VERSION 5.8 ;
BUSBITCHARS "[]" ;
DIVIDERCHAR "/" ;
UNITS
    DATABASE MICRONS 1000 ;
END UNITS

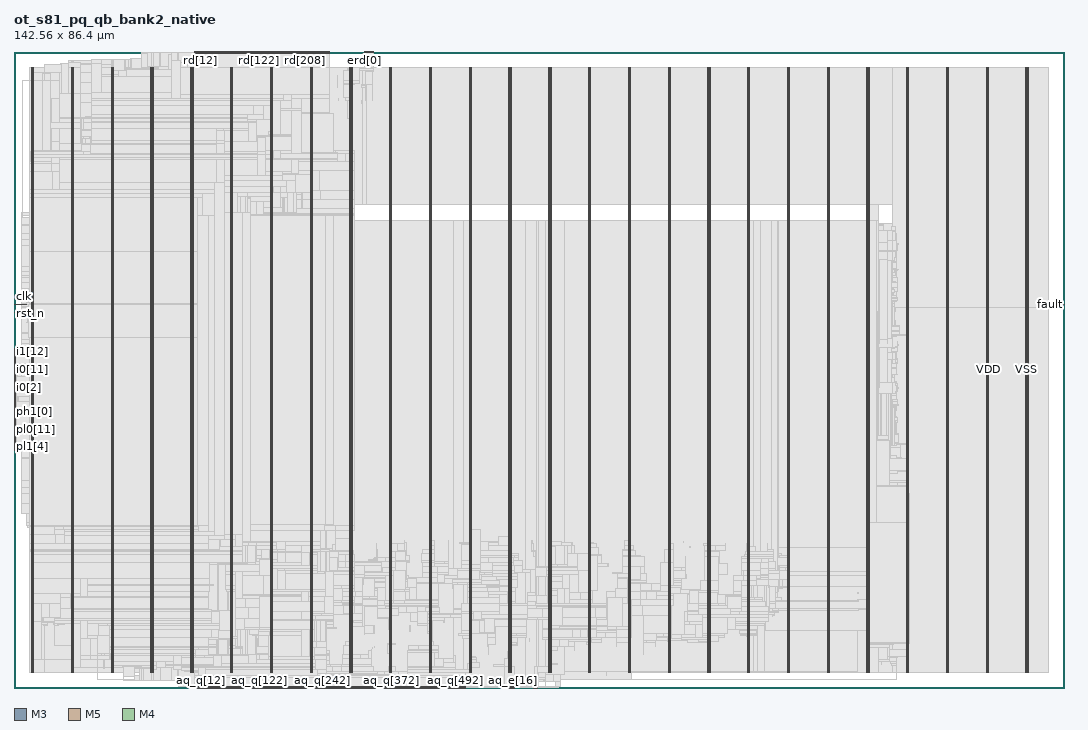
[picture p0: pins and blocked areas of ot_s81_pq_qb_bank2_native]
MACRO ot_s81_pq_qb_bank2_native
  FOREIGN ot_s81_pq_qb_bank2_native 0 0 ;
  CLASS BLOCK ;
  SIZE 142.56 BY 86.4 ;
  PIN aq_e[0]
    DIRECTION INPUT ;
    USE SIGNAL ;
    PORT
      LAYER M3 ;
        RECT  66.528 0 66.546 0.144 ;
    END
  END aq_e[0]
  PIN aq_e[10]
    DIRECTION INPUT ;
    USE SIGNAL ;
    PORT
      LAYER M3 ;
        RECT  67.248 0 67.266 0.144 ;
    END
  END aq_e[10]
  PIN aq_e[11]
    DIRECTION INPUT ;
    USE SIGNAL ;
    PORT
      LAYER M5 ;
        RECT  67.296 0 67.32 0.192 ;
    END
  END aq_e[11]
  PIN aq_e[12]
    DIRECTION INPUT ;
    USE SIGNAL ;
    PORT
      LAYER M3 ;
        RECT  67.392 0 67.41 0.144 ;
    END
  END aq_e[12]
  PIN aq_e[13]
    DIRECTION INPUT ;
    USE SIGNAL ;
    PORT
      LAYER M5 ;
        RECT  67.44 0 67.464 0.192 ;
    END
  END aq_e[13]
  PIN aq_e[14]
    DIRECTION INPUT ;
    USE SIGNAL ;
    PORT
      LAYER M3 ;
        RECT  67.536 0 67.554 0.144 ;
    END
  END aq_e[14]
  PIN aq_e[15]
    DIRECTION INPUT ;
    USE SIGNAL ;
    PORT
      LAYER M5 ;
        RECT  67.584 0 67.608 0.192 ;
    END
  END aq_e[15]
  PIN aq_e[16]
    DIRECTION INPUT ;
    USE SIGNAL ;
    PORT
      LAYER M3 ;
        RECT  67.68 0 67.698 0.144 ;
    END
  END aq_e[16]
  PIN aq_e[17]
    DIRECTION INPUT ;
    USE SIGNAL ;
    PORT
      LAYER M5 ;
        RECT  67.728 0 67.752 0.192 ;
    END
  END aq_e[17]
  PIN aq_e[18]
    DIRECTION INPUT ;
    USE SIGNAL ;
    PORT
      LAYER M3 ;
        RECT  67.824 0 67.842 0.144 ;
    END
  END aq_e[18]
  PIN aq_e[19]
    DIRECTION INPUT ;
    USE SIGNAL ;
    PORT
      LAYER M5 ;
        RECT  67.872 0 67.896 0.192 ;
    END
  END aq_e[19]
  PIN aq_e[1]
    DIRECTION INPUT ;
    USE SIGNAL ;
    PORT
      LAYER M5 ;
        RECT  66.576 0 66.6 0.192 ;
    END
  END aq_e[1]
  PIN aq_e[2]
    DIRECTION INPUT ;
    USE SIGNAL ;
    PORT
      LAYER M3 ;
        RECT  66.672 0 66.69 0.144 ;
    END
  END aq_e[2]
  PIN aq_e[3]
    DIRECTION INPUT ;
    USE SIGNAL ;
    PORT
      LAYER M5 ;
        RECT  66.72 0 66.744 0.192 ;
    END
  END aq_e[3]
  PIN aq_e[4]
    DIRECTION INPUT ;
    USE SIGNAL ;
    PORT
      LAYER M3 ;
        RECT  66.816 0 66.834 0.144 ;
    END
  END aq_e[4]
  PIN aq_e[5]
    DIRECTION INPUT ;
    USE SIGNAL ;
    PORT
      LAYER M5 ;
        RECT  66.864 0 66.888 0.192 ;
    END
  END aq_e[5]
  PIN aq_e[6]
    DIRECTION INPUT ;
    USE SIGNAL ;
    PORT
      LAYER M3 ;
        RECT  66.96 0 66.978 0.144 ;
    END
  END aq_e[6]
  PIN aq_e[7]
    DIRECTION INPUT ;
    USE SIGNAL ;
    PORT
      LAYER M5 ;
        RECT  67.008 0 67.032 0.192 ;
    END
  END aq_e[7]
  PIN aq_e[8]
    DIRECTION INPUT ;
    USE SIGNAL ;
    PORT
      LAYER M3 ;
        RECT  67.104 0 67.122 0.144 ;
    END
  END aq_e[8]
  PIN aq_e[9]
    DIRECTION INPUT ;
    USE SIGNAL ;
    PORT
      LAYER M5 ;
        RECT  67.152 0 67.176 0.192 ;
    END
  END aq_e[9]
  PIN aq_p[0]
    DIRECTION INPUT ;
    USE SIGNAL ;
    PORT
      LAYER M3 ;
        RECT  70.488 0 70.506 0.144 ;
    END
  END aq_p[0]
  PIN aq_p[1]
    DIRECTION INPUT ;
    USE SIGNAL ;
    PORT
      LAYER M5 ;
        RECT  70.512 0 70.536 0.192 ;
    END
  END aq_p[1]
  PIN aq_p[2]
    DIRECTION INPUT ;
    USE SIGNAL ;
    PORT
      LAYER M3 ;
        RECT  70.632 0 70.65 0.144 ;
    END
  END aq_p[2]
  PIN aq_p[3]
    DIRECTION INPUT ;
    USE SIGNAL ;
    PORT
      LAYER M5 ;
        RECT  70.656 0 70.68 0.192 ;
    END
  END aq_p[3]
  PIN aq_p[4]
    DIRECTION INPUT ;
    USE SIGNAL ;
    PORT
      LAYER M3 ;
        RECT  70.776 0 70.794 0.144 ;
    END
  END aq_p[4]
  PIN aq_p[5]
    DIRECTION INPUT ;
    USE SIGNAL ;
    PORT
      LAYER M5 ;
        RECT  70.8 0 70.824 0.192 ;
    END
  END aq_p[5]
  PIN aq_p[6]
    DIRECTION INPUT ;
    USE SIGNAL ;
    PORT
      LAYER M3 ;
        RECT  70.92 0 70.938 0.144 ;
    END
  END aq_p[6]
  PIN aq_p[7]
    DIRECTION INPUT ;
    USE SIGNAL ;
    PORT
      LAYER M5 ;
        RECT  70.944 0 70.968 0.192 ;
    END
  END aq_p[7]
  PIN aq_p[8]
    DIRECTION INPUT ;
    USE SIGNAL ;
    PORT
      LAYER M3 ;
        RECT  71.064 0 71.082 0.144 ;
    END
  END aq_p[8]
  PIN aq_p[9]
    DIRECTION INPUT ;
    USE SIGNAL ;
    PORT
      LAYER M5 ;
        RECT  71.088 0 71.112 0.192 ;
    END
  END aq_p[9]
  PIN aq_q[0]
    DIRECTION INPUT ;
    USE SIGNAL ;
    PORT
      LAYER M3 ;
        RECT  24.48 0 24.498 0.144 ;
    END
  END aq_q[0]
  PIN aq_q[100]
    DIRECTION INPUT ;
    USE SIGNAL ;
    PORT
      LAYER M3 ;
        RECT  31.68 0 31.698 0.144 ;
    END
  END aq_q[100]
  PIN aq_q[101]
    DIRECTION INPUT ;
    USE SIGNAL ;
    PORT
      LAYER M5 ;
        RECT  31.728 0 31.752 0.192 ;
    END
  END aq_q[101]
  PIN aq_q[102]
    DIRECTION INPUT ;
    USE SIGNAL ;
    PORT
      LAYER M3 ;
        RECT  31.824 0 31.842 0.144 ;
    END
  END aq_q[102]
  PIN aq_q[103]
    DIRECTION INPUT ;
    USE SIGNAL ;
    PORT
      LAYER M5 ;
        RECT  31.872 0 31.896 0.192 ;
    END
  END aq_q[103]
  PIN aq_q[104]
    DIRECTION INPUT ;
    USE SIGNAL ;
    PORT
      LAYER M3 ;
        RECT  31.968 0 31.986 0.144 ;
    END
  END aq_q[104]
  PIN aq_q[105]
    DIRECTION INPUT ;
    USE SIGNAL ;
    PORT
      LAYER M5 ;
        RECT  32.016 0 32.04 0.192 ;
    END
  END aq_q[105]
  PIN aq_q[106]
    DIRECTION INPUT ;
    USE SIGNAL ;
    PORT
      LAYER M3 ;
        RECT  32.112 0 32.13 0.144 ;
    END
  END aq_q[106]
  PIN aq_q[107]
    DIRECTION INPUT ;
    USE SIGNAL ;
    PORT
      LAYER M5 ;
        RECT  32.16 0 32.184 0.192 ;
    END
  END aq_q[107]
  PIN aq_q[108]
    DIRECTION INPUT ;
    USE SIGNAL ;
    PORT
      LAYER M3 ;
        RECT  32.256 0 32.274 0.144 ;
    END
  END aq_q[108]
  PIN aq_q[109]
    DIRECTION INPUT ;
    USE SIGNAL ;
    PORT
      LAYER M5 ;
        RECT  32.304 0 32.328 0.192 ;
    END
  END aq_q[109]
  PIN aq_q[10]
    DIRECTION INPUT ;
    USE SIGNAL ;
    PORT
      LAYER M3 ;
        RECT  25.2 0 25.218 0.144 ;
    END
  END aq_q[10]
  PIN aq_q[110]
    DIRECTION INPUT ;
    USE SIGNAL ;
    PORT
      LAYER M3 ;
        RECT  32.4 0 32.418 0.144 ;
    END
  END aq_q[110]
  PIN aq_q[111]
    DIRECTION INPUT ;
    USE SIGNAL ;
    PORT
      LAYER M5 ;
        RECT  32.448 0 32.472 0.192 ;
    END
  END aq_q[111]
  PIN aq_q[112]
    DIRECTION INPUT ;
    USE SIGNAL ;
    PORT
      LAYER M3 ;
        RECT  32.544 0 32.562 0.144 ;
    END
  END aq_q[112]
  PIN aq_q[113]
    DIRECTION INPUT ;
    USE SIGNAL ;
    PORT
      LAYER M5 ;
        RECT  32.592 0 32.616 0.192 ;
    END
  END aq_q[113]
  PIN aq_q[114]
    DIRECTION INPUT ;
    USE SIGNAL ;
    PORT
      LAYER M3 ;
        RECT  32.688 0 32.706 0.144 ;
    END
  END aq_q[114]
  PIN aq_q[115]
    DIRECTION INPUT ;
    USE SIGNAL ;
    PORT
      LAYER M5 ;
        RECT  32.736 0 32.76 0.192 ;
    END
  END aq_q[115]
  PIN aq_q[116]
    DIRECTION INPUT ;
    USE SIGNAL ;
    PORT
      LAYER M3 ;
        RECT  32.832 0 32.85 0.144 ;
    END
  END aq_q[116]
  PIN aq_q[117]
    DIRECTION INPUT ;
    USE SIGNAL ;
    PORT
      LAYER M5 ;
        RECT  32.88 0 32.904 0.192 ;
    END
  END aq_q[117]
  PIN aq_q[118]
    DIRECTION INPUT ;
    USE SIGNAL ;
    PORT
      LAYER M3 ;
        RECT  32.976 0 32.994 0.144 ;
    END
  END aq_q[118]
  PIN aq_q[119]
    DIRECTION INPUT ;
    USE SIGNAL ;
    PORT
      LAYER M5 ;
        RECT  33.024 0 33.048 0.192 ;
    END
  END aq_q[119]
  PIN aq_q[11]
    DIRECTION INPUT ;
    USE SIGNAL ;
    PORT
      LAYER M5 ;
        RECT  25.248 0 25.272 0.192 ;
    END
  END aq_q[11]
  PIN aq_q[120]
    DIRECTION INPUT ;
    USE SIGNAL ;
    PORT
      LAYER M3 ;
        RECT  33.12 0 33.138 0.144 ;
    END
  END aq_q[120]
  PIN aq_q[121]
    DIRECTION INPUT ;
    USE SIGNAL ;
    PORT
      LAYER M5 ;
        RECT  33.168 0 33.192 0.192 ;
    END
  END aq_q[121]
  PIN aq_q[122]
    DIRECTION INPUT ;
    USE SIGNAL ;
    PORT
      LAYER M3 ;
        RECT  33.264 0 33.282 0.144 ;
    END
  END aq_q[122]
  PIN aq_q[123]
    DIRECTION INPUT ;
    USE SIGNAL ;
    PORT
      LAYER M5 ;
        RECT  33.312 0 33.336 0.192 ;
    END
  END aq_q[123]
  PIN aq_q[124]
    DIRECTION INPUT ;
    USE SIGNAL ;
    PORT
      LAYER M3 ;
        RECT  33.408 0 33.426 0.144 ;
    END
  END aq_q[124]
  PIN aq_q[125]
    DIRECTION INPUT ;
    USE SIGNAL ;
    PORT
      LAYER M5 ;
        RECT  33.456 0 33.48 0.192 ;
    END
  END aq_q[125]
  PIN aq_q[126]
    DIRECTION INPUT ;
    USE SIGNAL ;
    PORT
      LAYER M3 ;
        RECT  33.552 0 33.57 0.144 ;
    END
  END aq_q[126]
  PIN aq_q[127]
    DIRECTION INPUT ;
    USE SIGNAL ;
    PORT
      LAYER M5 ;
        RECT  33.6 0 33.624 0.192 ;
    END
  END aq_q[127]
  PIN aq_q[128]
    DIRECTION INPUT ;
    USE SIGNAL ;
    PORT
      LAYER M3 ;
        RECT  33.696 0 33.714 0.144 ;
    END
  END aq_q[128]
  PIN aq_q[129]
    DIRECTION INPUT ;
    USE SIGNAL ;
    PORT
      LAYER M5 ;
        RECT  33.744 0 33.768 0.192 ;
    END
  END aq_q[129]
  PIN aq_q[12]
    DIRECTION INPUT ;
    USE SIGNAL ;
    PORT
      LAYER M3 ;
        RECT  25.344 0 25.362 0.144 ;
    END
  END aq_q[12]
  PIN aq_q[130]
    DIRECTION INPUT ;
    USE SIGNAL ;
    PORT
      LAYER M3 ;
        RECT  33.84 0 33.858 0.144 ;
    END
  END aq_q[130]
  PIN aq_q[131]
    DIRECTION INPUT ;
    USE SIGNAL ;
    PORT
      LAYER M5 ;
        RECT  33.888 0 33.912 0.192 ;
    END
  END aq_q[131]
  PIN aq_q[132]
    DIRECTION INPUT ;
    USE SIGNAL ;
    PORT
      LAYER M3 ;
        RECT  33.984 0 34.002 0.144 ;
    END
  END aq_q[132]
  PIN aq_q[133]
    DIRECTION INPUT ;
    USE SIGNAL ;
    PORT
      LAYER M5 ;
        RECT  34.032 0 34.056 0.192 ;
    END
  END aq_q[133]
  PIN aq_q[134]
    DIRECTION INPUT ;
    USE SIGNAL ;
    PORT
      LAYER M3 ;
        RECT  34.128 0 34.146 0.144 ;
    END
  END aq_q[134]
  PIN aq_q[135]
    DIRECTION INPUT ;
    USE SIGNAL ;
    PORT
      LAYER M5 ;
        RECT  34.176 0 34.2 0.192 ;
    END
  END aq_q[135]
  PIN aq_q[136]
    DIRECTION INPUT ;
    USE SIGNAL ;
    PORT
      LAYER M3 ;
        RECT  34.272 0 34.29 0.144 ;
    END
  END aq_q[136]
  PIN aq_q[137]
    DIRECTION INPUT ;
    USE SIGNAL ;
    PORT
      LAYER M5 ;
        RECT  34.32 0 34.344 0.192 ;
    END
  END aq_q[137]
  PIN aq_q[138]
    DIRECTION INPUT ;
    USE SIGNAL ;
    PORT
      LAYER M3 ;
        RECT  34.416 0 34.434 0.144 ;
    END
  END aq_q[138]
  PIN aq_q[139]
    DIRECTION INPUT ;
    USE SIGNAL ;
    PORT
      LAYER M5 ;
        RECT  34.464 0 34.488 0.192 ;
    END
  END aq_q[139]
  PIN aq_q[13]
    DIRECTION INPUT ;
    USE SIGNAL ;
    PORT
      LAYER M5 ;
        RECT  25.392 0 25.416 0.192 ;
    END
  END aq_q[13]
  PIN aq_q[140]
    DIRECTION INPUT ;
    USE SIGNAL ;
    PORT
      LAYER M3 ;
        RECT  34.56 0 34.578 0.144 ;
    END
  END aq_q[140]
  PIN aq_q[141]
    DIRECTION INPUT ;
    USE SIGNAL ;
    PORT
      LAYER M5 ;
        RECT  34.608 0 34.632 0.192 ;
    END
  END aq_q[141]
  PIN aq_q[142]
    DIRECTION INPUT ;
    USE SIGNAL ;
    PORT
      LAYER M3 ;
        RECT  34.704 0 34.722 0.144 ;
    END
  END aq_q[142]
  PIN aq_q[143]
    DIRECTION INPUT ;
    USE SIGNAL ;
    PORT
      LAYER M5 ;
        RECT  34.752 0 34.776 0.192 ;
    END
  END aq_q[143]
  PIN aq_q[144]
    DIRECTION INPUT ;
    USE SIGNAL ;
    PORT
      LAYER M3 ;
        RECT  34.848 0 34.866 0.144 ;
    END
  END aq_q[144]
  PIN aq_q[145]
    DIRECTION INPUT ;
    USE SIGNAL ;
    PORT
      LAYER M5 ;
        RECT  34.896 0 34.92 0.192 ;
    END
  END aq_q[145]
  PIN aq_q[146]
    DIRECTION INPUT ;
    USE SIGNAL ;
    PORT
      LAYER M3 ;
        RECT  34.992 0 35.01 0.144 ;
    END
  END aq_q[146]
  PIN aq_q[147]
    DIRECTION INPUT ;
    USE SIGNAL ;
    PORT
      LAYER M5 ;
        RECT  35.04 0 35.064 0.192 ;
    END
  END aq_q[147]
  PIN aq_q[148]
    DIRECTION INPUT ;
    USE SIGNAL ;
    PORT
      LAYER M3 ;
        RECT  35.136 0 35.154 0.144 ;
    END
  END aq_q[148]
  PIN aq_q[149]
    DIRECTION INPUT ;
    USE SIGNAL ;
    PORT
      LAYER M5 ;
        RECT  35.184 0 35.208 0.192 ;
    END
  END aq_q[149]
  PIN aq_q[14]
    DIRECTION INPUT ;
    USE SIGNAL ;
    PORT
      LAYER M3 ;
        RECT  25.488 0 25.506 0.144 ;
    END
  END aq_q[14]
  PIN aq_q[150]
    DIRECTION INPUT ;
    USE SIGNAL ;
    PORT
      LAYER M3 ;
        RECT  35.28 0 35.298 0.144 ;
    END
  END aq_q[150]
  PIN aq_q[151]
    DIRECTION INPUT ;
    USE SIGNAL ;
    PORT
      LAYER M5 ;
        RECT  35.328 0 35.352 0.192 ;
    END
  END aq_q[151]
  PIN aq_q[152]
    DIRECTION INPUT ;
    USE SIGNAL ;
    PORT
      LAYER M3 ;
        RECT  35.424 0 35.442 0.144 ;
    END
  END aq_q[152]
  PIN aq_q[153]
    DIRECTION INPUT ;
    USE SIGNAL ;
    PORT
      LAYER M5 ;
        RECT  35.472 0 35.496 0.192 ;
    END
  END aq_q[153]
  PIN aq_q[154]
    DIRECTION INPUT ;
    USE SIGNAL ;
    PORT
      LAYER M3 ;
        RECT  35.568 0 35.586 0.144 ;
    END
  END aq_q[154]
  PIN aq_q[155]
    DIRECTION INPUT ;
    USE SIGNAL ;
    PORT
      LAYER M5 ;
        RECT  35.616 0 35.64 0.192 ;
    END
  END aq_q[155]
  PIN aq_q[156]
    DIRECTION INPUT ;
    USE SIGNAL ;
    PORT
      LAYER M3 ;
        RECT  35.712 0 35.73 0.144 ;
    END
  END aq_q[156]
  PIN aq_q[157]
    DIRECTION INPUT ;
    USE SIGNAL ;
    PORT
      LAYER M5 ;
        RECT  35.76 0 35.784 0.192 ;
    END
  END aq_q[157]
  PIN aq_q[158]
    DIRECTION INPUT ;
    USE SIGNAL ;
    PORT
      LAYER M3 ;
        RECT  35.856 0 35.874 0.144 ;
    END
  END aq_q[158]
  PIN aq_q[159]
    DIRECTION INPUT ;
    USE SIGNAL ;
    PORT
      LAYER M5 ;
        RECT  35.904 0 35.928 0.192 ;
    END
  END aq_q[159]
  PIN aq_q[15]
    DIRECTION INPUT ;
    USE SIGNAL ;
    PORT
      LAYER M5 ;
        RECT  25.536 0 25.56 0.192 ;
    END
  END aq_q[15]
  PIN aq_q[160]
    DIRECTION INPUT ;
    USE SIGNAL ;
    PORT
      LAYER M3 ;
        RECT  36 0 36.018 0.144 ;
    END
  END aq_q[160]
  PIN aq_q[161]
    DIRECTION INPUT ;
    USE SIGNAL ;
    PORT
      LAYER M5 ;
        RECT  36.048 0 36.072 0.192 ;
    END
  END aq_q[161]
  PIN aq_q[162]
    DIRECTION INPUT ;
    USE SIGNAL ;
    PORT
      LAYER M3 ;
        RECT  36.144 0 36.162 0.144 ;
    END
  END aq_q[162]
  PIN aq_q[163]
    DIRECTION INPUT ;
    USE SIGNAL ;
    PORT
      LAYER M5 ;
        RECT  36.192 0 36.216 0.192 ;
    END
  END aq_q[163]
  PIN aq_q[164]
    DIRECTION INPUT ;
    USE SIGNAL ;
    PORT
      LAYER M3 ;
        RECT  36.288 0 36.306 0.144 ;
    END
  END aq_q[164]
  PIN aq_q[165]
    DIRECTION INPUT ;
    USE SIGNAL ;
    PORT
      LAYER M5 ;
        RECT  36.336 0 36.36 0.192 ;
    END
  END aq_q[165]
  PIN aq_q[166]
    DIRECTION INPUT ;
    USE SIGNAL ;
    PORT
      LAYER M3 ;
        RECT  36.432 0 36.45 0.144 ;
    END
  END aq_q[166]
  PIN aq_q[167]
    DIRECTION INPUT ;
    USE SIGNAL ;
    PORT
      LAYER M5 ;
        RECT  36.48 0 36.504 0.192 ;
    END
  END aq_q[167]
  PIN aq_q[168]
    DIRECTION INPUT ;
    USE SIGNAL ;
    PORT
      LAYER M3 ;
        RECT  36.576 0 36.594 0.144 ;
    END
  END aq_q[168]
  PIN aq_q[169]
    DIRECTION INPUT ;
    USE SIGNAL ;
    PORT
      LAYER M5 ;
        RECT  36.624 0 36.648 0.192 ;
    END
  END aq_q[169]
  PIN aq_q[16]
    DIRECTION INPUT ;
    USE SIGNAL ;
    PORT
      LAYER M3 ;
        RECT  25.632 0 25.65 0.144 ;
    END
  END aq_q[16]
  PIN aq_q[170]
    DIRECTION INPUT ;
    USE SIGNAL ;
    PORT
      LAYER M3 ;
        RECT  36.72 0 36.738 0.144 ;
    END
  END aq_q[170]
  PIN aq_q[171]
    DIRECTION INPUT ;
    USE SIGNAL ;
    PORT
      LAYER M5 ;
        RECT  36.768 0 36.792 0.192 ;
    END
  END aq_q[171]
  PIN aq_q[172]
    DIRECTION INPUT ;
    USE SIGNAL ;
    PORT
      LAYER M3 ;
        RECT  36.864 0 36.882 0.144 ;
    END
  END aq_q[172]
  PIN aq_q[173]
    DIRECTION INPUT ;
    USE SIGNAL ;
    PORT
      LAYER M5 ;
        RECT  36.912 0 36.936 0.192 ;
    END
  END aq_q[173]
  PIN aq_q[174]
    DIRECTION INPUT ;
    USE SIGNAL ;
    PORT
      LAYER M3 ;
        RECT  37.008 0 37.026 0.144 ;
    END
  END aq_q[174]
  PIN aq_q[175]
    DIRECTION INPUT ;
    USE SIGNAL ;
    PORT
      LAYER M5 ;
        RECT  37.056 0 37.08 0.192 ;
    END
  END aq_q[175]
  PIN aq_q[176]
    DIRECTION INPUT ;
    USE SIGNAL ;
    PORT
      LAYER M3 ;
        RECT  37.152 0 37.17 0.144 ;
    END
  END aq_q[176]
  PIN aq_q[177]
    DIRECTION INPUT ;
    USE SIGNAL ;
    PORT
      LAYER M5 ;
        RECT  37.2 0 37.224 0.192 ;
    END
  END aq_q[177]
  PIN aq_q[178]
    DIRECTION INPUT ;
    USE SIGNAL ;
    PORT
      LAYER M3 ;
        RECT  37.296 0 37.314 0.144 ;
    END
  END aq_q[178]
  PIN aq_q[179]
    DIRECTION INPUT ;
    USE SIGNAL ;
    PORT
      LAYER M5 ;
        RECT  37.344 0 37.368 0.192 ;
    END
  END aq_q[179]
  PIN aq_q[17]
    DIRECTION INPUT ;
    USE SIGNAL ;
    PORT
      LAYER M5 ;
        RECT  25.68 0 25.704 0.192 ;
    END
  END aq_q[17]
  PIN aq_q[180]
    DIRECTION INPUT ;
    USE SIGNAL ;
    PORT
      LAYER M3 ;
        RECT  37.44 0 37.458 0.144 ;
    END
  END aq_q[180]
  PIN aq_q[181]
    DIRECTION INPUT ;
    USE SIGNAL ;
    PORT
      LAYER M5 ;
        RECT  37.488 0 37.512 0.192 ;
    END
  END aq_q[181]
  PIN aq_q[182]
    DIRECTION INPUT ;
    USE SIGNAL ;
    PORT
      LAYER M3 ;
        RECT  37.584 0 37.602 0.144 ;
    END
  END aq_q[182]
  PIN aq_q[183]
    DIRECTION INPUT ;
    USE SIGNAL ;
    PORT
      LAYER M5 ;
        RECT  37.632 0 37.656 0.192 ;
    END
  END aq_q[183]
  PIN aq_q[184]
    DIRECTION INPUT ;
    USE SIGNAL ;
    PORT
      LAYER M3 ;
        RECT  37.728 0 37.746 0.144 ;
    END
  END aq_q[184]
  PIN aq_q[185]
    DIRECTION INPUT ;
    USE SIGNAL ;
    PORT
      LAYER M5 ;
        RECT  37.776 0 37.8 0.192 ;
    END
  END aq_q[185]
  PIN aq_q[186]
    DIRECTION INPUT ;
    USE SIGNAL ;
    PORT
      LAYER M3 ;
        RECT  37.872 0 37.89 0.144 ;
    END
  END aq_q[186]
  PIN aq_q[187]
    DIRECTION INPUT ;
    USE SIGNAL ;
    PORT
      LAYER M5 ;
        RECT  37.92 0 37.944 0.192 ;
    END
  END aq_q[187]
  PIN aq_q[188]
    DIRECTION INPUT ;
    USE SIGNAL ;
    PORT
      LAYER M3 ;
        RECT  38.016 0 38.034 0.144 ;
    END
  END aq_q[188]
  PIN aq_q[189]
    DIRECTION INPUT ;
    USE SIGNAL ;
    PORT
      LAYER M5 ;
        RECT  38.064 0 38.088 0.192 ;
    END
  END aq_q[189]
  PIN aq_q[18]
    DIRECTION INPUT ;
    USE SIGNAL ;
    PORT
      LAYER M3 ;
        RECT  25.776 0 25.794 0.144 ;
    END
  END aq_q[18]
  PIN aq_q[190]
    DIRECTION INPUT ;
    USE SIGNAL ;
    PORT
      LAYER M3 ;
        RECT  38.16 0 38.178 0.144 ;
    END
  END aq_q[190]
  PIN aq_q[191]
    DIRECTION INPUT ;
    USE SIGNAL ;
    PORT
      LAYER M5 ;
        RECT  38.208 0 38.232 0.192 ;
    END
  END aq_q[191]
  PIN aq_q[192]
    DIRECTION INPUT ;
    USE SIGNAL ;
    PORT
      LAYER M3 ;
        RECT  38.304 0 38.322 0.144 ;
    END
  END aq_q[192]
  PIN aq_q[193]
    DIRECTION INPUT ;
    USE SIGNAL ;
    PORT
      LAYER M5 ;
        RECT  38.352 0 38.376 0.192 ;
    END
  END aq_q[193]
  PIN aq_q[194]
    DIRECTION INPUT ;
    USE SIGNAL ;
    PORT
      LAYER M3 ;
        RECT  38.448 0 38.466 0.144 ;
    END
  END aq_q[194]
  PIN aq_q[195]
    DIRECTION INPUT ;
    USE SIGNAL ;
    PORT
      LAYER M5 ;
        RECT  38.496 0 38.52 0.192 ;
    END
  END aq_q[195]
  PIN aq_q[196]
    DIRECTION INPUT ;
    USE SIGNAL ;
    PORT
      LAYER M3 ;
        RECT  38.592 0 38.61 0.144 ;
    END
  END aq_q[196]
  PIN aq_q[197]
    DIRECTION INPUT ;
    USE SIGNAL ;
    PORT
      LAYER M5 ;
        RECT  38.64 0 38.664 0.192 ;
    END
  END aq_q[197]
  PIN aq_q[198]
    DIRECTION INPUT ;
    USE SIGNAL ;
    PORT
      LAYER M3 ;
        RECT  38.736 0 38.754 0.144 ;
    END
  END aq_q[198]
  PIN aq_q[199]
    DIRECTION INPUT ;
    USE SIGNAL ;
    PORT
      LAYER M5 ;
        RECT  38.784 0 38.808 0.192 ;
    END
  END aq_q[199]
  PIN aq_q[19]
    DIRECTION INPUT ;
    USE SIGNAL ;
    PORT
      LAYER M5 ;
        RECT  25.824 0 25.848 0.192 ;
    END
  END aq_q[19]
  PIN aq_q[1]
    DIRECTION INPUT ;
    USE SIGNAL ;
    PORT
      LAYER M5 ;
        RECT  24.528 0 24.552 0.192 ;
    END
  END aq_q[1]
  PIN aq_q[200]
    DIRECTION INPUT ;
    USE SIGNAL ;
    PORT
      LAYER M3 ;
        RECT  38.88 0 38.898 0.144 ;
    END
  END aq_q[200]
  PIN aq_q[201]
    DIRECTION INPUT ;
    USE SIGNAL ;
    PORT
      LAYER M5 ;
        RECT  38.928 0 38.952 0.192 ;
    END
  END aq_q[201]
  PIN aq_q[202]
    DIRECTION INPUT ;
    USE SIGNAL ;
    PORT
      LAYER M3 ;
        RECT  39.024 0 39.042 0.144 ;
    END
  END aq_q[202]
  PIN aq_q[203]
    DIRECTION INPUT ;
    USE SIGNAL ;
    PORT
      LAYER M5 ;
        RECT  39.072 0 39.096 0.192 ;
    END
  END aq_q[203]
  PIN aq_q[204]
    DIRECTION INPUT ;
    USE SIGNAL ;
    PORT
      LAYER M3 ;
        RECT  39.168 0 39.186 0.144 ;
    END
  END aq_q[204]
  PIN aq_q[205]
    DIRECTION INPUT ;
    USE SIGNAL ;
    PORT
      LAYER M5 ;
        RECT  39.216 0 39.24 0.192 ;
    END
  END aq_q[205]
  PIN aq_q[206]
    DIRECTION INPUT ;
    USE SIGNAL ;
    PORT
      LAYER M3 ;
        RECT  39.312 0 39.33 0.144 ;
    END
  END aq_q[206]
  PIN aq_q[207]
    DIRECTION INPUT ;
    USE SIGNAL ;
    PORT
      LAYER M5 ;
        RECT  39.36 0 39.384 0.192 ;
    END
  END aq_q[207]
  PIN aq_q[208]
    DIRECTION INPUT ;
    USE SIGNAL ;
    PORT
      LAYER M3 ;
        RECT  39.456 0 39.474 0.144 ;
    END
  END aq_q[208]
  PIN aq_q[209]
    DIRECTION INPUT ;
    USE SIGNAL ;
    PORT
      LAYER M5 ;
        RECT  39.504 0 39.528 0.192 ;
    END
  END aq_q[209]
  PIN aq_q[20]
    DIRECTION INPUT ;
    USE SIGNAL ;
    PORT
      LAYER M3 ;
        RECT  25.92 0 25.938 0.144 ;
    END
  END aq_q[20]
  PIN aq_q[210]
    DIRECTION INPUT ;
    USE SIGNAL ;
    PORT
      LAYER M3 ;
        RECT  39.6 0 39.618 0.144 ;
    END
  END aq_q[210]
  PIN aq_q[211]
    DIRECTION INPUT ;
    USE SIGNAL ;
    PORT
      LAYER M5 ;
        RECT  39.648 0 39.672 0.192 ;
    END
  END aq_q[211]
  PIN aq_q[212]
    DIRECTION INPUT ;
    USE SIGNAL ;
    PORT
      LAYER M3 ;
        RECT  39.744 0 39.762 0.144 ;
    END
  END aq_q[212]
  PIN aq_q[213]
    DIRECTION INPUT ;
    USE SIGNAL ;
    PORT
      LAYER M5 ;
        RECT  39.792 0 39.816 0.192 ;
    END
  END aq_q[213]
  PIN aq_q[214]
    DIRECTION INPUT ;
    USE SIGNAL ;
    PORT
      LAYER M3 ;
        RECT  39.888 0 39.906 0.144 ;
    END
  END aq_q[214]
  PIN aq_q[215]
    DIRECTION INPUT ;
    USE SIGNAL ;
    PORT
      LAYER M5 ;
        RECT  39.936 0 39.96 0.192 ;
    END
  END aq_q[215]
  PIN aq_q[216]
    DIRECTION INPUT ;
    USE SIGNAL ;
    PORT
      LAYER M3 ;
        RECT  40.032 0 40.05 0.144 ;
    END
  END aq_q[216]
  PIN aq_q[217]
    DIRECTION INPUT ;
    USE SIGNAL ;
    PORT
      LAYER M5 ;
        RECT  40.08 0 40.104 0.192 ;
    END
  END aq_q[217]
  PIN aq_q[218]
    DIRECTION INPUT ;
    USE SIGNAL ;
    PORT
      LAYER M3 ;
        RECT  40.176 0 40.194 0.144 ;
    END
  END aq_q[218]
  PIN aq_q[219]
    DIRECTION INPUT ;
    USE SIGNAL ;
    PORT
      LAYER M5 ;
        RECT  40.224 0 40.248 0.192 ;
    END
  END aq_q[219]
  PIN aq_q[21]
    DIRECTION INPUT ;
    USE SIGNAL ;
    PORT
      LAYER M5 ;
        RECT  25.968 0 25.992 0.192 ;
    END
  END aq_q[21]
  PIN aq_q[220]
    DIRECTION INPUT ;
    USE SIGNAL ;
    PORT
      LAYER M3 ;
        RECT  40.32 0 40.338 0.144 ;
    END
  END aq_q[220]
  PIN aq_q[221]
    DIRECTION INPUT ;
    USE SIGNAL ;
    PORT
      LAYER M5 ;
        RECT  40.368 0 40.392 0.192 ;
    END
  END aq_q[221]
  PIN aq_q[222]
    DIRECTION INPUT ;
    USE SIGNAL ;
    PORT
      LAYER M3 ;
        RECT  40.464 0 40.482 0.144 ;
    END
  END aq_q[222]
  PIN aq_q[223]
    DIRECTION INPUT ;
    USE SIGNAL ;
    PORT
      LAYER M5 ;
        RECT  40.512 0 40.536 0.192 ;
    END
  END aq_q[223]
  PIN aq_q[224]
    DIRECTION INPUT ;
    USE SIGNAL ;
    PORT
      LAYER M3 ;
        RECT  40.608 0 40.626 0.144 ;
    END
  END aq_q[224]
  PIN aq_q[225]
    DIRECTION INPUT ;
    USE SIGNAL ;
    PORT
      LAYER M5 ;
        RECT  40.656 0 40.68 0.192 ;
    END
  END aq_q[225]
  PIN aq_q[226]
    DIRECTION INPUT ;
    USE SIGNAL ;
    PORT
      LAYER M3 ;
        RECT  40.752 0 40.77 0.144 ;
    END
  END aq_q[226]
  PIN aq_q[227]
    DIRECTION INPUT ;
    USE SIGNAL ;
    PORT
      LAYER M5 ;
        RECT  40.8 0 40.824 0.192 ;
    END
  END aq_q[227]
  PIN aq_q[228]
    DIRECTION INPUT ;
    USE SIGNAL ;
    PORT
      LAYER M3 ;
        RECT  40.896 0 40.914 0.144 ;
    END
  END aq_q[228]
  PIN aq_q[229]
    DIRECTION INPUT ;
    USE SIGNAL ;
    PORT
      LAYER M5 ;
        RECT  40.944 0 40.968 0.192 ;
    END
  END aq_q[229]
  PIN aq_q[22]
    DIRECTION INPUT ;
    USE SIGNAL ;
    PORT
      LAYER M3 ;
        RECT  26.064 0 26.082 0.144 ;
    END
  END aq_q[22]
  PIN aq_q[230]
    DIRECTION INPUT ;
    USE SIGNAL ;
    PORT
      LAYER M3 ;
        RECT  41.04 0 41.058 0.144 ;
    END
  END aq_q[230]
  PIN aq_q[231]
    DIRECTION INPUT ;
    USE SIGNAL ;
    PORT
      LAYER M5 ;
        RECT  41.088 0 41.112 0.192 ;
    END
  END aq_q[231]
  PIN aq_q[232]
    DIRECTION INPUT ;
    USE SIGNAL ;
    PORT
      LAYER M3 ;
        RECT  41.184 0 41.202 0.144 ;
    END
  END aq_q[232]
  PIN aq_q[233]
    DIRECTION INPUT ;
    USE SIGNAL ;
    PORT
      LAYER M5 ;
        RECT  41.232 0 41.256 0.192 ;
    END
  END aq_q[233]
  PIN aq_q[234]
    DIRECTION INPUT ;
    USE SIGNAL ;
    PORT
      LAYER M3 ;
        RECT  41.328 0 41.346 0.144 ;
    END
  END aq_q[234]
  PIN aq_q[235]
    DIRECTION INPUT ;
    USE SIGNAL ;
    PORT
      LAYER M5 ;
        RECT  41.376 0 41.4 0.192 ;
    END
  END aq_q[235]
  PIN aq_q[236]
    DIRECTION INPUT ;
    USE SIGNAL ;
    PORT
      LAYER M3 ;
        RECT  41.472 0 41.49 0.144 ;
    END
  END aq_q[236]
  PIN aq_q[237]
    DIRECTION INPUT ;
    USE SIGNAL ;
    PORT
      LAYER M5 ;
        RECT  41.52 0 41.544 0.192 ;
    END
  END aq_q[237]
  PIN aq_q[238]
    DIRECTION INPUT ;
    USE SIGNAL ;
    PORT
      LAYER M3 ;
        RECT  41.616 0 41.634 0.144 ;
    END
  END aq_q[238]
  PIN aq_q[239]
    DIRECTION INPUT ;
    USE SIGNAL ;
    PORT
      LAYER M5 ;
        RECT  41.664 0 41.688 0.192 ;
    END
  END aq_q[239]
  PIN aq_q[23]
    DIRECTION INPUT ;
    USE SIGNAL ;
    PORT
      LAYER M5 ;
        RECT  26.112 0 26.136 0.192 ;
    END
  END aq_q[23]
  PIN aq_q[240]
    DIRECTION INPUT ;
    USE SIGNAL ;
    PORT
      LAYER M3 ;
        RECT  41.76 0 41.778 0.144 ;
    END
  END aq_q[240]
  PIN aq_q[241]
    DIRECTION INPUT ;
    USE SIGNAL ;
    PORT
      LAYER M5 ;
        RECT  41.808 0 41.832 0.192 ;
    END
  END aq_q[241]
  PIN aq_q[242]
    DIRECTION INPUT ;
    USE SIGNAL ;
    PORT
      LAYER M3 ;
        RECT  41.904 0 41.922 0.144 ;
    END
  END aq_q[242]
  PIN aq_q[243]
    DIRECTION INPUT ;
    USE SIGNAL ;
    PORT
      LAYER M5 ;
        RECT  41.952 0 41.976 0.192 ;
    END
  END aq_q[243]
  PIN aq_q[244]
    DIRECTION INPUT ;
    USE SIGNAL ;
    PORT
      LAYER M3 ;
        RECT  42.048 0 42.066 0.144 ;
    END
  END aq_q[244]
  PIN aq_q[245]
    DIRECTION INPUT ;
    USE SIGNAL ;
    PORT
      LAYER M5 ;
        RECT  42.096 0 42.12 0.192 ;
    END
  END aq_q[245]
  PIN aq_q[246]
    DIRECTION INPUT ;
    USE SIGNAL ;
    PORT
      LAYER M3 ;
        RECT  42.192 0 42.21 0.144 ;
    END
  END aq_q[246]
  PIN aq_q[247]
    DIRECTION INPUT ;
    USE SIGNAL ;
    PORT
      LAYER M5 ;
        RECT  42.24 0 42.264 0.192 ;
    END
  END aq_q[247]
  PIN aq_q[248]
    DIRECTION INPUT ;
    USE SIGNAL ;
    PORT
      LAYER M3 ;
        RECT  42.336 0 42.354 0.144 ;
    END
  END aq_q[248]
  PIN aq_q[249]
    DIRECTION INPUT ;
    USE SIGNAL ;
    PORT
      LAYER M5 ;
        RECT  42.384 0 42.408 0.192 ;
    END
  END aq_q[249]
  PIN aq_q[24]
    DIRECTION INPUT ;
    USE SIGNAL ;
    PORT
      LAYER M3 ;
        RECT  26.208 0 26.226 0.144 ;
    END
  END aq_q[24]
  PIN aq_q[250]
    DIRECTION INPUT ;
    USE SIGNAL ;
    PORT
      LAYER M3 ;
        RECT  42.48 0 42.498 0.144 ;
    END
  END aq_q[250]
  PIN aq_q[251]
    DIRECTION INPUT ;
    USE SIGNAL ;
    PORT
      LAYER M5 ;
        RECT  42.528 0 42.552 0.192 ;
    END
  END aq_q[251]
  PIN aq_q[252]
    DIRECTION INPUT ;
    USE SIGNAL ;
    PORT
      LAYER M3 ;
        RECT  42.624 0 42.642 0.144 ;
    END
  END aq_q[252]
  PIN aq_q[253]
    DIRECTION INPUT ;
    USE SIGNAL ;
    PORT
      LAYER M5 ;
        RECT  42.672 0 42.696 0.192 ;
    END
  END aq_q[253]
  PIN aq_q[254]
    DIRECTION INPUT ;
    USE SIGNAL ;
    PORT
      LAYER M3 ;
        RECT  42.768 0 42.786 0.144 ;
    END
  END aq_q[254]
  PIN aq_q[255]
    DIRECTION INPUT ;
    USE SIGNAL ;
    PORT
      LAYER M5 ;
        RECT  42.816 0 42.84 0.192 ;
    END
  END aq_q[255]
  PIN aq_q[256]
    DIRECTION INPUT ;
    USE SIGNAL ;
    PORT
      LAYER M3 ;
        RECT  42.912 0 42.93 0.144 ;
    END
  END aq_q[256]
  PIN aq_q[257]
    DIRECTION INPUT ;
    USE SIGNAL ;
    PORT
      LAYER M5 ;
        RECT  42.96 0 42.984 0.192 ;
    END
  END aq_q[257]
  PIN aq_q[258]
    DIRECTION INPUT ;
    USE SIGNAL ;
    PORT
      LAYER M3 ;
        RECT  43.056 0 43.074 0.144 ;
    END
  END aq_q[258]
  PIN aq_q[259]
    DIRECTION INPUT ;
    USE SIGNAL ;
    PORT
      LAYER M5 ;
        RECT  43.104 0 43.128 0.192 ;
    END
  END aq_q[259]
  PIN aq_q[25]
    DIRECTION INPUT ;
    USE SIGNAL ;
    PORT
      LAYER M5 ;
        RECT  26.256 0 26.28 0.192 ;
    END
  END aq_q[25]
  PIN aq_q[260]
    DIRECTION INPUT ;
    USE SIGNAL ;
    PORT
      LAYER M3 ;
        RECT  43.2 0 43.218 0.144 ;
    END
  END aq_q[260]
  PIN aq_q[261]
    DIRECTION INPUT ;
    USE SIGNAL ;
    PORT
      LAYER M5 ;
        RECT  43.248 0 43.272 0.192 ;
    END
  END aq_q[261]
  PIN aq_q[262]
    DIRECTION INPUT ;
    USE SIGNAL ;
    PORT
      LAYER M3 ;
        RECT  43.344 0 43.362 0.144 ;
    END
  END aq_q[262]
  PIN aq_q[263]
    DIRECTION INPUT ;
    USE SIGNAL ;
    PORT
      LAYER M5 ;
        RECT  43.392 0 43.416 0.192 ;
    END
  END aq_q[263]
  PIN aq_q[264]
    DIRECTION INPUT ;
    USE SIGNAL ;
    PORT
      LAYER M3 ;
        RECT  43.488 0 43.506 0.144 ;
    END
  END aq_q[264]
  PIN aq_q[265]
    DIRECTION INPUT ;
    USE SIGNAL ;
    PORT
      LAYER M5 ;
        RECT  43.536 0 43.56 0.192 ;
    END
  END aq_q[265]
  PIN aq_q[266]
    DIRECTION INPUT ;
    USE SIGNAL ;
    PORT
      LAYER M3 ;
        RECT  43.632 0 43.65 0.144 ;
    END
  END aq_q[266]
  PIN aq_q[267]
    DIRECTION INPUT ;
    USE SIGNAL ;
    PORT
      LAYER M5 ;
        RECT  43.68 0 43.704 0.192 ;
    END
  END aq_q[267]
  PIN aq_q[268]
    DIRECTION INPUT ;
    USE SIGNAL ;
    PORT
      LAYER M3 ;
        RECT  43.776 0 43.794 0.144 ;
    END
  END aq_q[268]
  PIN aq_q[269]
    DIRECTION INPUT ;
    USE SIGNAL ;
    PORT
      LAYER M5 ;
        RECT  43.824 0 43.848 0.192 ;
    END
  END aq_q[269]
  PIN aq_q[26]
    DIRECTION INPUT ;
    USE SIGNAL ;
    PORT
      LAYER M3 ;
        RECT  26.352 0 26.37 0.144 ;
    END
  END aq_q[26]
  PIN aq_q[270]
    DIRECTION INPUT ;
    USE SIGNAL ;
    PORT
      LAYER M3 ;
        RECT  43.92 0 43.938 0.144 ;
    END
  END aq_q[270]
  PIN aq_q[271]
    DIRECTION INPUT ;
    USE SIGNAL ;
    PORT
      LAYER M5 ;
        RECT  43.968 0 43.992 0.192 ;
    END
  END aq_q[271]
  PIN aq_q[272]
    DIRECTION INPUT ;
    USE SIGNAL ;
    PORT
      LAYER M3 ;
        RECT  44.064 0 44.082 0.144 ;
    END
  END aq_q[272]
  PIN aq_q[273]
    DIRECTION INPUT ;
    USE SIGNAL ;
    PORT
      LAYER M5 ;
        RECT  44.112 0 44.136 0.192 ;
    END
  END aq_q[273]
  PIN aq_q[274]
    DIRECTION INPUT ;
    USE SIGNAL ;
    PORT
      LAYER M3 ;
        RECT  44.208 0 44.226 0.144 ;
    END
  END aq_q[274]
  PIN aq_q[275]
    DIRECTION INPUT ;
    USE SIGNAL ;
    PORT
      LAYER M5 ;
        RECT  44.256 0 44.28 0.192 ;
    END
  END aq_q[275]
  PIN aq_q[276]
    DIRECTION INPUT ;
    USE SIGNAL ;
    PORT
      LAYER M3 ;
        RECT  44.352 0 44.37 0.144 ;
    END
  END aq_q[276]
  PIN aq_q[277]
    DIRECTION INPUT ;
    USE SIGNAL ;
    PORT
      LAYER M5 ;
        RECT  44.4 0 44.424 0.192 ;
    END
  END aq_q[277]
  PIN aq_q[278]
    DIRECTION INPUT ;
    USE SIGNAL ;
    PORT
      LAYER M3 ;
        RECT  44.496 0 44.514 0.144 ;
    END
  END aq_q[278]
  PIN aq_q[279]
    DIRECTION INPUT ;
    USE SIGNAL ;
    PORT
      LAYER M5 ;
        RECT  44.544 0 44.568 0.192 ;
    END
  END aq_q[279]
  PIN aq_q[27]
    DIRECTION INPUT ;
    USE SIGNAL ;
    PORT
      LAYER M5 ;
        RECT  26.4 0 26.424 0.192 ;
    END
  END aq_q[27]
  PIN aq_q[280]
    DIRECTION INPUT ;
    USE SIGNAL ;
    PORT
      LAYER M3 ;
        RECT  44.64 0 44.658 0.144 ;
    END
  END aq_q[280]
  PIN aq_q[281]
    DIRECTION INPUT ;
    USE SIGNAL ;
    PORT
      LAYER M5 ;
        RECT  44.688 0 44.712 0.192 ;
    END
  END aq_q[281]
  PIN aq_q[282]
    DIRECTION INPUT ;
    USE SIGNAL ;
    PORT
      LAYER M3 ;
        RECT  44.784 0 44.802 0.144 ;
    END
  END aq_q[282]
  PIN aq_q[283]
    DIRECTION INPUT ;
    USE SIGNAL ;
    PORT
      LAYER M5 ;
        RECT  44.832 0 44.856 0.192 ;
    END
  END aq_q[283]
  PIN aq_q[284]
    DIRECTION INPUT ;
    USE SIGNAL ;
    PORT
      LAYER M3 ;
        RECT  44.928 0 44.946 0.144 ;
    END
  END aq_q[284]
  PIN aq_q[285]
    DIRECTION INPUT ;
    USE SIGNAL ;
    PORT
      LAYER M5 ;
        RECT  44.976 0 45 0.192 ;
    END
  END aq_q[285]
  PIN aq_q[286]
    DIRECTION INPUT ;
    USE SIGNAL ;
    PORT
      LAYER M3 ;
        RECT  45.072 0 45.09 0.144 ;
    END
  END aq_q[286]
  PIN aq_q[287]
    DIRECTION INPUT ;
    USE SIGNAL ;
    PORT
      LAYER M5 ;
        RECT  45.12 0 45.144 0.192 ;
    END
  END aq_q[287]
  PIN aq_q[288]
    DIRECTION INPUT ;
    USE SIGNAL ;
    PORT
      LAYER M3 ;
        RECT  45.216 0 45.234 0.144 ;
    END
  END aq_q[288]
  PIN aq_q[289]
    DIRECTION INPUT ;
    USE SIGNAL ;
    PORT
      LAYER M5 ;
        RECT  45.264 0 45.288 0.192 ;
    END
  END aq_q[289]
  PIN aq_q[28]
    DIRECTION INPUT ;
    USE SIGNAL ;
    PORT
      LAYER M3 ;
        RECT  26.496 0 26.514 0.144 ;
    END
  END aq_q[28]
  PIN aq_q[290]
    DIRECTION INPUT ;
    USE SIGNAL ;
    PORT
      LAYER M3 ;
        RECT  45.36 0 45.378 0.144 ;
    END
  END aq_q[290]
  PIN aq_q[291]
    DIRECTION INPUT ;
    USE SIGNAL ;
    PORT
      LAYER M5 ;
        RECT  45.408 0 45.432 0.192 ;
    END
  END aq_q[291]
  PIN aq_q[292]
    DIRECTION INPUT ;
    USE SIGNAL ;
    PORT
      LAYER M3 ;
        RECT  45.504 0 45.522 0.144 ;
    END
  END aq_q[292]
  PIN aq_q[293]
    DIRECTION INPUT ;
    USE SIGNAL ;
    PORT
      LAYER M5 ;
        RECT  45.552 0 45.576 0.192 ;
    END
  END aq_q[293]
  PIN aq_q[294]
    DIRECTION INPUT ;
    USE SIGNAL ;
    PORT
      LAYER M3 ;
        RECT  45.648 0 45.666 0.144 ;
    END
  END aq_q[294]
  PIN aq_q[295]
    DIRECTION INPUT ;
    USE SIGNAL ;
    PORT
      LAYER M5 ;
        RECT  45.696 0 45.72 0.192 ;
    END
  END aq_q[295]
  PIN aq_q[296]
    DIRECTION INPUT ;
    USE SIGNAL ;
    PORT
      LAYER M3 ;
        RECT  45.792 0 45.81 0.144 ;
    END
  END aq_q[296]
  PIN aq_q[297]
    DIRECTION INPUT ;
    USE SIGNAL ;
    PORT
      LAYER M5 ;
        RECT  45.84 0 45.864 0.192 ;
    END
  END aq_q[297]
  PIN aq_q[298]
    DIRECTION INPUT ;
    USE SIGNAL ;
    PORT
      LAYER M3 ;
        RECT  45.936 0 45.954 0.144 ;
    END
  END aq_q[298]
  PIN aq_q[299]
    DIRECTION INPUT ;
    USE SIGNAL ;
    PORT
      LAYER M5 ;
        RECT  45.984 0 46.008 0.192 ;
    END
  END aq_q[299]
  PIN aq_q[29]
    DIRECTION INPUT ;
    USE SIGNAL ;
    PORT
      LAYER M5 ;
        RECT  26.544 0 26.568 0.192 ;
    END
  END aq_q[29]
  PIN aq_q[2]
    DIRECTION INPUT ;
    USE SIGNAL ;
    PORT
      LAYER M3 ;
        RECT  24.624 0 24.642 0.144 ;
    END
  END aq_q[2]
  PIN aq_q[300]
    DIRECTION INPUT ;
    USE SIGNAL ;
    PORT
      LAYER M3 ;
        RECT  46.08 0 46.098 0.144 ;
    END
  END aq_q[300]
  PIN aq_q[301]
    DIRECTION INPUT ;
    USE SIGNAL ;
    PORT
      LAYER M5 ;
        RECT  46.128 0 46.152 0.192 ;
    END
  END aq_q[301]
  PIN aq_q[302]
    DIRECTION INPUT ;
    USE SIGNAL ;
    PORT
      LAYER M3 ;
        RECT  46.224 0 46.242 0.144 ;
    END
  END aq_q[302]
  PIN aq_q[303]
    DIRECTION INPUT ;
    USE SIGNAL ;
    PORT
      LAYER M5 ;
        RECT  46.272 0 46.296 0.192 ;
    END
  END aq_q[303]
  PIN aq_q[304]
    DIRECTION INPUT ;
    USE SIGNAL ;
    PORT
      LAYER M3 ;
        RECT  46.368 0 46.386 0.144 ;
    END
  END aq_q[304]
  PIN aq_q[305]
    DIRECTION INPUT ;
    USE SIGNAL ;
    PORT
      LAYER M5 ;
        RECT  46.416 0 46.44 0.192 ;
    END
  END aq_q[305]
  PIN aq_q[306]
    DIRECTION INPUT ;
    USE SIGNAL ;
    PORT
      LAYER M3 ;
        RECT  46.512 0 46.53 0.144 ;
    END
  END aq_q[306]
  PIN aq_q[307]
    DIRECTION INPUT ;
    USE SIGNAL ;
    PORT
      LAYER M5 ;
        RECT  46.56 0 46.584 0.192 ;
    END
  END aq_q[307]
  PIN aq_q[308]
    DIRECTION INPUT ;
    USE SIGNAL ;
    PORT
      LAYER M3 ;
        RECT  46.656 0 46.674 0.144 ;
    END
  END aq_q[308]
  PIN aq_q[309]
    DIRECTION INPUT ;
    USE SIGNAL ;
    PORT
      LAYER M5 ;
        RECT  46.704 0 46.728 0.192 ;
    END
  END aq_q[309]
  PIN aq_q[30]
    DIRECTION INPUT ;
    USE SIGNAL ;
    PORT
      LAYER M3 ;
        RECT  26.64 0 26.658 0.144 ;
    END
  END aq_q[30]
  PIN aq_q[310]
    DIRECTION INPUT ;
    USE SIGNAL ;
    PORT
      LAYER M3 ;
        RECT  46.8 0 46.818 0.144 ;
    END
  END aq_q[310]
  PIN aq_q[311]
    DIRECTION INPUT ;
    USE SIGNAL ;
    PORT
      LAYER M5 ;
        RECT  46.848 0 46.872 0.192 ;
    END
  END aq_q[311]
  PIN aq_q[312]
    DIRECTION INPUT ;
    USE SIGNAL ;
    PORT
      LAYER M3 ;
        RECT  46.944 0 46.962 0.144 ;
    END
  END aq_q[312]
  PIN aq_q[313]
    DIRECTION INPUT ;
    USE SIGNAL ;
    PORT
      LAYER M5 ;
        RECT  46.992 0 47.016 0.192 ;
    END
  END aq_q[313]
  PIN aq_q[314]
    DIRECTION INPUT ;
    USE SIGNAL ;
    PORT
      LAYER M3 ;
        RECT  47.088 0 47.106 0.144 ;
    END
  END aq_q[314]
  PIN aq_q[315]
    DIRECTION INPUT ;
    USE SIGNAL ;
    PORT
      LAYER M5 ;
        RECT  47.136 0 47.16 0.192 ;
    END
  END aq_q[315]
  PIN aq_q[316]
    DIRECTION INPUT ;
    USE SIGNAL ;
    PORT
      LAYER M3 ;
        RECT  47.232 0 47.25 0.144 ;
    END
  END aq_q[316]
  PIN aq_q[317]
    DIRECTION INPUT ;
    USE SIGNAL ;
    PORT
      LAYER M5 ;
        RECT  47.28 0 47.304 0.192 ;
    END
  END aq_q[317]
  PIN aq_q[318]
    DIRECTION INPUT ;
    USE SIGNAL ;
    PORT
      LAYER M3 ;
        RECT  47.376 0 47.394 0.144 ;
    END
  END aq_q[318]
  PIN aq_q[319]
    DIRECTION INPUT ;
    USE SIGNAL ;
    PORT
      LAYER M5 ;
        RECT  47.424 0 47.448 0.192 ;
    END
  END aq_q[319]
  PIN aq_q[31]
    DIRECTION INPUT ;
    USE SIGNAL ;
    PORT
      LAYER M5 ;
        RECT  26.688 0 26.712 0.192 ;
    END
  END aq_q[31]
  PIN aq_q[320]
    DIRECTION INPUT ;
    USE SIGNAL ;
    PORT
      LAYER M3 ;
        RECT  47.52 0 47.538 0.144 ;
    END
  END aq_q[320]
  PIN aq_q[321]
    DIRECTION INPUT ;
    USE SIGNAL ;
    PORT
      LAYER M5 ;
        RECT  47.568 0 47.592 0.192 ;
    END
  END aq_q[321]
  PIN aq_q[322]
    DIRECTION INPUT ;
    USE SIGNAL ;
    PORT
      LAYER M3 ;
        RECT  47.664 0 47.682 0.144 ;
    END
  END aq_q[322]
  PIN aq_q[323]
    DIRECTION INPUT ;
    USE SIGNAL ;
    PORT
      LAYER M5 ;
        RECT  47.712 0 47.736 0.192 ;
    END
  END aq_q[323]
  PIN aq_q[324]
    DIRECTION INPUT ;
    USE SIGNAL ;
    PORT
      LAYER M3 ;
        RECT  47.808 0 47.826 0.144 ;
    END
  END aq_q[324]
  PIN aq_q[325]
    DIRECTION INPUT ;
    USE SIGNAL ;
    PORT
      LAYER M5 ;
        RECT  47.856 0 47.88 0.192 ;
    END
  END aq_q[325]
  PIN aq_q[326]
    DIRECTION INPUT ;
    USE SIGNAL ;
    PORT
      LAYER M3 ;
        RECT  47.952 0 47.97 0.144 ;
    END
  END aq_q[326]
  PIN aq_q[327]
    DIRECTION INPUT ;
    USE SIGNAL ;
    PORT
      LAYER M5 ;
        RECT  48 0 48.024 0.192 ;
    END
  END aq_q[327]
  PIN aq_q[328]
    DIRECTION INPUT ;
    USE SIGNAL ;
    PORT
      LAYER M3 ;
        RECT  48.096 0 48.114 0.144 ;
    END
  END aq_q[328]
  PIN aq_q[329]
    DIRECTION INPUT ;
    USE SIGNAL ;
    PORT
      LAYER M5 ;
        RECT  48.144 0 48.168 0.192 ;
    END
  END aq_q[329]
  PIN aq_q[32]
    DIRECTION INPUT ;
    USE SIGNAL ;
    PORT
      LAYER M3 ;
        RECT  26.784 0 26.802 0.144 ;
    END
  END aq_q[32]
  PIN aq_q[330]
    DIRECTION INPUT ;
    USE SIGNAL ;
    PORT
      LAYER M3 ;
        RECT  48.24 0 48.258 0.144 ;
    END
  END aq_q[330]
  PIN aq_q[331]
    DIRECTION INPUT ;
    USE SIGNAL ;
    PORT
      LAYER M5 ;
        RECT  48.288 0 48.312 0.192 ;
    END
  END aq_q[331]
  PIN aq_q[332]
    DIRECTION INPUT ;
    USE SIGNAL ;
    PORT
      LAYER M3 ;
        RECT  48.384 0 48.402 0.144 ;
    END
  END aq_q[332]
  PIN aq_q[333]
    DIRECTION INPUT ;
    USE SIGNAL ;
    PORT
      LAYER M5 ;
        RECT  48.432 0 48.456 0.192 ;
    END
  END aq_q[333]
  PIN aq_q[334]
    DIRECTION INPUT ;
    USE SIGNAL ;
    PORT
      LAYER M3 ;
        RECT  48.528 0 48.546 0.144 ;
    END
  END aq_q[334]
  PIN aq_q[335]
    DIRECTION INPUT ;
    USE SIGNAL ;
    PORT
      LAYER M5 ;
        RECT  48.576 0 48.6 0.192 ;
    END
  END aq_q[335]
  PIN aq_q[336]
    DIRECTION INPUT ;
    USE SIGNAL ;
    PORT
      LAYER M3 ;
        RECT  48.672 0 48.69 0.144 ;
    END
  END aq_q[336]
  PIN aq_q[337]
    DIRECTION INPUT ;
    USE SIGNAL ;
    PORT
      LAYER M5 ;
        RECT  48.72 0 48.744 0.192 ;
    END
  END aq_q[337]
  PIN aq_q[338]
    DIRECTION INPUT ;
    USE SIGNAL ;
    PORT
      LAYER M3 ;
        RECT  48.816 0 48.834 0.144 ;
    END
  END aq_q[338]
  PIN aq_q[339]
    DIRECTION INPUT ;
    USE SIGNAL ;
    PORT
      LAYER M5 ;
        RECT  48.864 0 48.888 0.192 ;
    END
  END aq_q[339]
  PIN aq_q[33]
    DIRECTION INPUT ;
    USE SIGNAL ;
    PORT
      LAYER M5 ;
        RECT  26.832 0 26.856 0.192 ;
    END
  END aq_q[33]
  PIN aq_q[340]
    DIRECTION INPUT ;
    USE SIGNAL ;
    PORT
      LAYER M3 ;
        RECT  48.96 0 48.978 0.144 ;
    END
  END aq_q[340]
  PIN aq_q[341]
    DIRECTION INPUT ;
    USE SIGNAL ;
    PORT
      LAYER M5 ;
        RECT  49.008 0 49.032 0.192 ;
    END
  END aq_q[341]
  PIN aq_q[342]
    DIRECTION INPUT ;
    USE SIGNAL ;
    PORT
      LAYER M3 ;
        RECT  49.104 0 49.122 0.144 ;
    END
  END aq_q[342]
  PIN aq_q[343]
    DIRECTION INPUT ;
    USE SIGNAL ;
    PORT
      LAYER M5 ;
        RECT  49.152 0 49.176 0.192 ;
    END
  END aq_q[343]
  PIN aq_q[344]
    DIRECTION INPUT ;
    USE SIGNAL ;
    PORT
      LAYER M3 ;
        RECT  49.248 0 49.266 0.144 ;
    END
  END aq_q[344]
  PIN aq_q[345]
    DIRECTION INPUT ;
    USE SIGNAL ;
    PORT
      LAYER M5 ;
        RECT  49.296 0 49.32 0.192 ;
    END
  END aq_q[345]
  PIN aq_q[346]
    DIRECTION INPUT ;
    USE SIGNAL ;
    PORT
      LAYER M3 ;
        RECT  49.392 0 49.41 0.144 ;
    END
  END aq_q[346]
  PIN aq_q[347]
    DIRECTION INPUT ;
    USE SIGNAL ;
    PORT
      LAYER M5 ;
        RECT  49.44 0 49.464 0.192 ;
    END
  END aq_q[347]
  PIN aq_q[348]
    DIRECTION INPUT ;
    USE SIGNAL ;
    PORT
      LAYER M3 ;
        RECT  49.536 0 49.554 0.144 ;
    END
  END aq_q[348]
  PIN aq_q[349]
    DIRECTION INPUT ;
    USE SIGNAL ;
    PORT
      LAYER M5 ;
        RECT  49.584 0 49.608 0.192 ;
    END
  END aq_q[349]
  PIN aq_q[34]
    DIRECTION INPUT ;
    USE SIGNAL ;
    PORT
      LAYER M3 ;
        RECT  26.928 0 26.946 0.144 ;
    END
  END aq_q[34]
  PIN aq_q[350]
    DIRECTION INPUT ;
    USE SIGNAL ;
    PORT
      LAYER M3 ;
        RECT  49.68 0 49.698 0.144 ;
    END
  END aq_q[350]
  PIN aq_q[351]
    DIRECTION INPUT ;
    USE SIGNAL ;
    PORT
      LAYER M5 ;
        RECT  49.728 0 49.752 0.192 ;
    END
  END aq_q[351]
  PIN aq_q[352]
    DIRECTION INPUT ;
    USE SIGNAL ;
    PORT
      LAYER M3 ;
        RECT  49.824 0 49.842 0.144 ;
    END
  END aq_q[352]
  PIN aq_q[353]
    DIRECTION INPUT ;
    USE SIGNAL ;
    PORT
      LAYER M5 ;
        RECT  49.872 0 49.896 0.192 ;
    END
  END aq_q[353]
  PIN aq_q[354]
    DIRECTION INPUT ;
    USE SIGNAL ;
    PORT
      LAYER M3 ;
        RECT  49.968 0 49.986 0.144 ;
    END
  END aq_q[354]
  PIN aq_q[355]
    DIRECTION INPUT ;
    USE SIGNAL ;
    PORT
      LAYER M5 ;
        RECT  50.016 0 50.04 0.192 ;
    END
  END aq_q[355]
  PIN aq_q[356]
    DIRECTION INPUT ;
    USE SIGNAL ;
    PORT
      LAYER M3 ;
        RECT  50.112 0 50.13 0.144 ;
    END
  END aq_q[356]
  PIN aq_q[357]
    DIRECTION INPUT ;
    USE SIGNAL ;
    PORT
      LAYER M5 ;
        RECT  50.16 0 50.184 0.192 ;
    END
  END aq_q[357]
  PIN aq_q[358]
    DIRECTION INPUT ;
    USE SIGNAL ;
    PORT
      LAYER M3 ;
        RECT  50.256 0 50.274 0.144 ;
    END
  END aq_q[358]
  PIN aq_q[359]
    DIRECTION INPUT ;
    USE SIGNAL ;
    PORT
      LAYER M5 ;
        RECT  50.304 0 50.328 0.192 ;
    END
  END aq_q[359]
  PIN aq_q[35]
    DIRECTION INPUT ;
    USE SIGNAL ;
    PORT
      LAYER M5 ;
        RECT  26.976 0 27 0.192 ;
    END
  END aq_q[35]
  PIN aq_q[360]
    DIRECTION INPUT ;
    USE SIGNAL ;
    PORT
      LAYER M3 ;
        RECT  50.4 0 50.418 0.144 ;
    END
  END aq_q[360]
  PIN aq_q[361]
    DIRECTION INPUT ;
    USE SIGNAL ;
    PORT
      LAYER M5 ;
        RECT  50.448 0 50.472 0.192 ;
    END
  END aq_q[361]
  PIN aq_q[362]
    DIRECTION INPUT ;
    USE SIGNAL ;
    PORT
      LAYER M3 ;
        RECT  50.544 0 50.562 0.144 ;
    END
  END aq_q[362]
  PIN aq_q[363]
    DIRECTION INPUT ;
    USE SIGNAL ;
    PORT
      LAYER M5 ;
        RECT  50.592 0 50.616 0.192 ;
    END
  END aq_q[363]
  PIN aq_q[364]
    DIRECTION INPUT ;
    USE SIGNAL ;
    PORT
      LAYER M3 ;
        RECT  50.688 0 50.706 0.144 ;
    END
  END aq_q[364]
  PIN aq_q[365]
    DIRECTION INPUT ;
    USE SIGNAL ;
    PORT
      LAYER M5 ;
        RECT  50.736 0 50.76 0.192 ;
    END
  END aq_q[365]
  PIN aq_q[366]
    DIRECTION INPUT ;
    USE SIGNAL ;
    PORT
      LAYER M3 ;
        RECT  50.832 0 50.85 0.144 ;
    END
  END aq_q[366]
  PIN aq_q[367]
    DIRECTION INPUT ;
    USE SIGNAL ;
    PORT
      LAYER M5 ;
        RECT  50.88 0 50.904 0.192 ;
    END
  END aq_q[367]
  PIN aq_q[368]
    DIRECTION INPUT ;
    USE SIGNAL ;
    PORT
      LAYER M3 ;
        RECT  50.976 0 50.994 0.144 ;
    END
  END aq_q[368]
  PIN aq_q[369]
    DIRECTION INPUT ;
    USE SIGNAL ;
    PORT
      LAYER M5 ;
        RECT  51.024 0 51.048 0.192 ;
    END
  END aq_q[369]
  PIN aq_q[36]
    DIRECTION INPUT ;
    USE SIGNAL ;
    PORT
      LAYER M3 ;
        RECT  27.072 0 27.09 0.144 ;
    END
  END aq_q[36]
  PIN aq_q[370]
    DIRECTION INPUT ;
    USE SIGNAL ;
    PORT
      LAYER M3 ;
        RECT  51.12 0 51.138 0.144 ;
    END
  END aq_q[370]
  PIN aq_q[371]
    DIRECTION INPUT ;
    USE SIGNAL ;
    PORT
      LAYER M5 ;
        RECT  51.168 0 51.192 0.192 ;
    END
  END aq_q[371]
  PIN aq_q[372]
    DIRECTION INPUT ;
    USE SIGNAL ;
    PORT
      LAYER M3 ;
        RECT  51.264 0 51.282 0.144 ;
    END
  END aq_q[372]
  PIN aq_q[373]
    DIRECTION INPUT ;
    USE SIGNAL ;
    PORT
      LAYER M5 ;
        RECT  51.312 0 51.336 0.192 ;
    END
  END aq_q[373]
  PIN aq_q[374]
    DIRECTION INPUT ;
    USE SIGNAL ;
    PORT
      LAYER M3 ;
        RECT  51.408 0 51.426 0.144 ;
    END
  END aq_q[374]
  PIN aq_q[375]
    DIRECTION INPUT ;
    USE SIGNAL ;
    PORT
      LAYER M5 ;
        RECT  51.456 0 51.48 0.192 ;
    END
  END aq_q[375]
  PIN aq_q[376]
    DIRECTION INPUT ;
    USE SIGNAL ;
    PORT
      LAYER M3 ;
        RECT  51.552 0 51.57 0.144 ;
    END
  END aq_q[376]
  PIN aq_q[377]
    DIRECTION INPUT ;
    USE SIGNAL ;
    PORT
      LAYER M5 ;
        RECT  51.6 0 51.624 0.192 ;
    END
  END aq_q[377]
  PIN aq_q[378]
    DIRECTION INPUT ;
    USE SIGNAL ;
    PORT
      LAYER M3 ;
        RECT  51.696 0 51.714 0.144 ;
    END
  END aq_q[378]
  PIN aq_q[379]
    DIRECTION INPUT ;
    USE SIGNAL ;
    PORT
      LAYER M5 ;
        RECT  51.744 0 51.768 0.192 ;
    END
  END aq_q[379]
  PIN aq_q[37]
    DIRECTION INPUT ;
    USE SIGNAL ;
    PORT
      LAYER M5 ;
        RECT  27.12 0 27.144 0.192 ;
    END
  END aq_q[37]
  PIN aq_q[380]
    DIRECTION INPUT ;
    USE SIGNAL ;
    PORT
      LAYER M3 ;
        RECT  51.84 0 51.858 0.144 ;
    END
  END aq_q[380]
  PIN aq_q[381]
    DIRECTION INPUT ;
    USE SIGNAL ;
    PORT
      LAYER M5 ;
        RECT  51.888 0 51.912 0.192 ;
    END
  END aq_q[381]
  PIN aq_q[382]
    DIRECTION INPUT ;
    USE SIGNAL ;
    PORT
      LAYER M3 ;
        RECT  51.984 0 52.002 0.144 ;
    END
  END aq_q[382]
  PIN aq_q[383]
    DIRECTION INPUT ;
    USE SIGNAL ;
    PORT
      LAYER M5 ;
        RECT  52.032 0 52.056 0.192 ;
    END
  END aq_q[383]
  PIN aq_q[384]
    DIRECTION INPUT ;
    USE SIGNAL ;
    PORT
      LAYER M3 ;
        RECT  52.128 0 52.146 0.144 ;
    END
  END aq_q[384]
  PIN aq_q[385]
    DIRECTION INPUT ;
    USE SIGNAL ;
    PORT
      LAYER M5 ;
        RECT  52.176 0 52.2 0.192 ;
    END
  END aq_q[385]
  PIN aq_q[386]
    DIRECTION INPUT ;
    USE SIGNAL ;
    PORT
      LAYER M3 ;
        RECT  52.272 0 52.29 0.144 ;
    END
  END aq_q[386]
  PIN aq_q[387]
    DIRECTION INPUT ;
    USE SIGNAL ;
    PORT
      LAYER M5 ;
        RECT  52.32 0 52.344 0.192 ;
    END
  END aq_q[387]
  PIN aq_q[388]
    DIRECTION INPUT ;
    USE SIGNAL ;
    PORT
      LAYER M3 ;
        RECT  52.416 0 52.434 0.144 ;
    END
  END aq_q[388]
  PIN aq_q[389]
    DIRECTION INPUT ;
    USE SIGNAL ;
    PORT
      LAYER M5 ;
        RECT  52.464 0 52.488 0.192 ;
    END
  END aq_q[389]
  PIN aq_q[38]
    DIRECTION INPUT ;
    USE SIGNAL ;
    PORT
      LAYER M3 ;
        RECT  27.216 0 27.234 0.144 ;
    END
  END aq_q[38]
  PIN aq_q[390]
    DIRECTION INPUT ;
    USE SIGNAL ;
    PORT
      LAYER M3 ;
        RECT  52.56 0 52.578 0.144 ;
    END
  END aq_q[390]
  PIN aq_q[391]
    DIRECTION INPUT ;
    USE SIGNAL ;
    PORT
      LAYER M5 ;
        RECT  52.608 0 52.632 0.192 ;
    END
  END aq_q[391]
  PIN aq_q[392]
    DIRECTION INPUT ;
    USE SIGNAL ;
    PORT
      LAYER M3 ;
        RECT  52.704 0 52.722 0.144 ;
    END
  END aq_q[392]
  PIN aq_q[393]
    DIRECTION INPUT ;
    USE SIGNAL ;
    PORT
      LAYER M5 ;
        RECT  52.752 0 52.776 0.192 ;
    END
  END aq_q[393]
  PIN aq_q[394]
    DIRECTION INPUT ;
    USE SIGNAL ;
    PORT
      LAYER M3 ;
        RECT  52.848 0 52.866 0.144 ;
    END
  END aq_q[394]
  PIN aq_q[395]
    DIRECTION INPUT ;
    USE SIGNAL ;
    PORT
      LAYER M5 ;
        RECT  52.896 0 52.92 0.192 ;
    END
  END aq_q[395]
  PIN aq_q[396]
    DIRECTION INPUT ;
    USE SIGNAL ;
    PORT
      LAYER M3 ;
        RECT  52.992 0 53.01 0.144 ;
    END
  END aq_q[396]
  PIN aq_q[397]
    DIRECTION INPUT ;
    USE SIGNAL ;
    PORT
      LAYER M5 ;
        RECT  53.04 0 53.064 0.192 ;
    END
  END aq_q[397]
  PIN aq_q[398]
    DIRECTION INPUT ;
    USE SIGNAL ;
    PORT
      LAYER M3 ;
        RECT  53.136 0 53.154 0.144 ;
    END
  END aq_q[398]
  PIN aq_q[399]
    DIRECTION INPUT ;
    USE SIGNAL ;
    PORT
      LAYER M5 ;
        RECT  53.184 0 53.208 0.192 ;
    END
  END aq_q[399]
  PIN aq_q[39]
    DIRECTION INPUT ;
    USE SIGNAL ;
    PORT
      LAYER M5 ;
        RECT  27.264 0 27.288 0.192 ;
    END
  END aq_q[39]
  PIN aq_q[3]
    DIRECTION INPUT ;
    USE SIGNAL ;
    PORT
      LAYER M5 ;
        RECT  24.672 0 24.696 0.192 ;
    END
  END aq_q[3]
  PIN aq_q[400]
    DIRECTION INPUT ;
    USE SIGNAL ;
    PORT
      LAYER M3 ;
        RECT  53.28 0 53.298 0.144 ;
    END
  END aq_q[400]
  PIN aq_q[401]
    DIRECTION INPUT ;
    USE SIGNAL ;
    PORT
      LAYER M5 ;
        RECT  53.328 0 53.352 0.192 ;
    END
  END aq_q[401]
  PIN aq_q[402]
    DIRECTION INPUT ;
    USE SIGNAL ;
    PORT
      LAYER M3 ;
        RECT  53.424 0 53.442 0.144 ;
    END
  END aq_q[402]
  PIN aq_q[403]
    DIRECTION INPUT ;
    USE SIGNAL ;
    PORT
      LAYER M5 ;
        RECT  53.472 0 53.496 0.192 ;
    END
  END aq_q[403]
  PIN aq_q[404]
    DIRECTION INPUT ;
    USE SIGNAL ;
    PORT
      LAYER M3 ;
        RECT  53.568 0 53.586 0.144 ;
    END
  END aq_q[404]
  PIN aq_q[405]
    DIRECTION INPUT ;
    USE SIGNAL ;
    PORT
      LAYER M5 ;
        RECT  53.616 0 53.64 0.192 ;
    END
  END aq_q[405]
  PIN aq_q[406]
    DIRECTION INPUT ;
    USE SIGNAL ;
    PORT
      LAYER M3 ;
        RECT  53.712 0 53.73 0.144 ;
    END
  END aq_q[406]
  PIN aq_q[407]
    DIRECTION INPUT ;
    USE SIGNAL ;
    PORT
      LAYER M5 ;
        RECT  53.76 0 53.784 0.192 ;
    END
  END aq_q[407]
  PIN aq_q[408]
    DIRECTION INPUT ;
    USE SIGNAL ;
    PORT
      LAYER M3 ;
        RECT  53.856 0 53.874 0.144 ;
    END
  END aq_q[408]
  PIN aq_q[409]
    DIRECTION INPUT ;
    USE SIGNAL ;
    PORT
      LAYER M5 ;
        RECT  53.904 0 53.928 0.192 ;
    END
  END aq_q[409]
  PIN aq_q[40]
    DIRECTION INPUT ;
    USE SIGNAL ;
    PORT
      LAYER M3 ;
        RECT  27.36 0 27.378 0.144 ;
    END
  END aq_q[40]
  PIN aq_q[410]
    DIRECTION INPUT ;
    USE SIGNAL ;
    PORT
      LAYER M3 ;
        RECT  54 0 54.018 0.144 ;
    END
  END aq_q[410]
  PIN aq_q[411]
    DIRECTION INPUT ;
    USE SIGNAL ;
    PORT
      LAYER M5 ;
        RECT  54.048 0 54.072 0.192 ;
    END
  END aq_q[411]
  PIN aq_q[412]
    DIRECTION INPUT ;
    USE SIGNAL ;
    PORT
      LAYER M3 ;
        RECT  54.144 0 54.162 0.144 ;
    END
  END aq_q[412]
  PIN aq_q[413]
    DIRECTION INPUT ;
    USE SIGNAL ;
    PORT
      LAYER M5 ;
        RECT  54.192 0 54.216 0.192 ;
    END
  END aq_q[413]
  PIN aq_q[414]
    DIRECTION INPUT ;
    USE SIGNAL ;
    PORT
      LAYER M3 ;
        RECT  54.288 0 54.306 0.144 ;
    END
  END aq_q[414]
  PIN aq_q[415]
    DIRECTION INPUT ;
    USE SIGNAL ;
    PORT
      LAYER M5 ;
        RECT  54.336 0 54.36 0.192 ;
    END
  END aq_q[415]
  PIN aq_q[416]
    DIRECTION INPUT ;
    USE SIGNAL ;
    PORT
      LAYER M3 ;
        RECT  54.432 0 54.45 0.144 ;
    END
  END aq_q[416]
  PIN aq_q[417]
    DIRECTION INPUT ;
    USE SIGNAL ;
    PORT
      LAYER M5 ;
        RECT  54.48 0 54.504 0.192 ;
    END
  END aq_q[417]
  PIN aq_q[418]
    DIRECTION INPUT ;
    USE SIGNAL ;
    PORT
      LAYER M3 ;
        RECT  54.576 0 54.594 0.144 ;
    END
  END aq_q[418]
  PIN aq_q[419]
    DIRECTION INPUT ;
    USE SIGNAL ;
    PORT
      LAYER M5 ;
        RECT  54.624 0 54.648 0.192 ;
    END
  END aq_q[419]
  PIN aq_q[41]
    DIRECTION INPUT ;
    USE SIGNAL ;
    PORT
      LAYER M5 ;
        RECT  27.408 0 27.432 0.192 ;
    END
  END aq_q[41]
  PIN aq_q[420]
    DIRECTION INPUT ;
    USE SIGNAL ;
    PORT
      LAYER M3 ;
        RECT  54.72 0 54.738 0.144 ;
    END
  END aq_q[420]
  PIN aq_q[421]
    DIRECTION INPUT ;
    USE SIGNAL ;
    PORT
      LAYER M5 ;
        RECT  54.768 0 54.792 0.192 ;
    END
  END aq_q[421]
  PIN aq_q[422]
    DIRECTION INPUT ;
    USE SIGNAL ;
    PORT
      LAYER M3 ;
        RECT  54.864 0 54.882 0.144 ;
    END
  END aq_q[422]
  PIN aq_q[423]
    DIRECTION INPUT ;
    USE SIGNAL ;
    PORT
      LAYER M5 ;
        RECT  54.912 0 54.936 0.192 ;
    END
  END aq_q[423]
  PIN aq_q[424]
    DIRECTION INPUT ;
    USE SIGNAL ;
    PORT
      LAYER M3 ;
        RECT  55.008 0 55.026 0.144 ;
    END
  END aq_q[424]
  PIN aq_q[425]
    DIRECTION INPUT ;
    USE SIGNAL ;
    PORT
      LAYER M5 ;
        RECT  55.056 0 55.08 0.192 ;
    END
  END aq_q[425]
  PIN aq_q[426]
    DIRECTION INPUT ;
    USE SIGNAL ;
    PORT
      LAYER M3 ;
        RECT  55.152 0 55.17 0.144 ;
    END
  END aq_q[426]
  PIN aq_q[427]
    DIRECTION INPUT ;
    USE SIGNAL ;
    PORT
      LAYER M5 ;
        RECT  55.2 0 55.224 0.192 ;
    END
  END aq_q[427]
  PIN aq_q[428]
    DIRECTION INPUT ;
    USE SIGNAL ;
    PORT
      LAYER M3 ;
        RECT  55.296 0 55.314 0.144 ;
    END
  END aq_q[428]
  PIN aq_q[429]
    DIRECTION INPUT ;
    USE SIGNAL ;
    PORT
      LAYER M5 ;
        RECT  55.344 0 55.368 0.192 ;
    END
  END aq_q[429]
  PIN aq_q[42]
    DIRECTION INPUT ;
    USE SIGNAL ;
    PORT
      LAYER M3 ;
        RECT  27.504 0 27.522 0.144 ;
    END
  END aq_q[42]
  PIN aq_q[430]
    DIRECTION INPUT ;
    USE SIGNAL ;
    PORT
      LAYER M3 ;
        RECT  55.44 0 55.458 0.144 ;
    END
  END aq_q[430]
  PIN aq_q[431]
    DIRECTION INPUT ;
    USE SIGNAL ;
    PORT
      LAYER M5 ;
        RECT  55.488 0 55.512 0.192 ;
    END
  END aq_q[431]
  PIN aq_q[432]
    DIRECTION INPUT ;
    USE SIGNAL ;
    PORT
      LAYER M3 ;
        RECT  55.584 0 55.602 0.144 ;
    END
  END aq_q[432]
  PIN aq_q[433]
    DIRECTION INPUT ;
    USE SIGNAL ;
    PORT
      LAYER M5 ;
        RECT  55.632 0 55.656 0.192 ;
    END
  END aq_q[433]
  PIN aq_q[434]
    DIRECTION INPUT ;
    USE SIGNAL ;
    PORT
      LAYER M3 ;
        RECT  55.728 0 55.746 0.144 ;
    END
  END aq_q[434]
  PIN aq_q[435]
    DIRECTION INPUT ;
    USE SIGNAL ;
    PORT
      LAYER M5 ;
        RECT  55.776 0 55.8 0.192 ;
    END
  END aq_q[435]
  PIN aq_q[436]
    DIRECTION INPUT ;
    USE SIGNAL ;
    PORT
      LAYER M3 ;
        RECT  55.872 0 55.89 0.144 ;
    END
  END aq_q[436]
  PIN aq_q[437]
    DIRECTION INPUT ;
    USE SIGNAL ;
    PORT
      LAYER M5 ;
        RECT  55.92 0 55.944 0.192 ;
    END
  END aq_q[437]
  PIN aq_q[438]
    DIRECTION INPUT ;
    USE SIGNAL ;
    PORT
      LAYER M3 ;
        RECT  56.016 0 56.034 0.144 ;
    END
  END aq_q[438]
  PIN aq_q[439]
    DIRECTION INPUT ;
    USE SIGNAL ;
    PORT
      LAYER M5 ;
        RECT  56.064 0 56.088 0.192 ;
    END
  END aq_q[439]
  PIN aq_q[43]
    DIRECTION INPUT ;
    USE SIGNAL ;
    PORT
      LAYER M5 ;
        RECT  27.552 0 27.576 0.192 ;
    END
  END aq_q[43]
  PIN aq_q[440]
    DIRECTION INPUT ;
    USE SIGNAL ;
    PORT
      LAYER M3 ;
        RECT  56.16 0 56.178 0.144 ;
    END
  END aq_q[440]
  PIN aq_q[441]
    DIRECTION INPUT ;
    USE SIGNAL ;
    PORT
      LAYER M5 ;
        RECT  56.208 0 56.232 0.192 ;
    END
  END aq_q[441]
  PIN aq_q[442]
    DIRECTION INPUT ;
    USE SIGNAL ;
    PORT
      LAYER M3 ;
        RECT  56.304 0 56.322 0.144 ;
    END
  END aq_q[442]
  PIN aq_q[443]
    DIRECTION INPUT ;
    USE SIGNAL ;
    PORT
      LAYER M5 ;
        RECT  56.352 0 56.376 0.192 ;
    END
  END aq_q[443]
  PIN aq_q[444]
    DIRECTION INPUT ;
    USE SIGNAL ;
    PORT
      LAYER M3 ;
        RECT  56.448 0 56.466 0.144 ;
    END
  END aq_q[444]
  PIN aq_q[445]
    DIRECTION INPUT ;
    USE SIGNAL ;
    PORT
      LAYER M5 ;
        RECT  56.496 0 56.52 0.192 ;
    END
  END aq_q[445]
  PIN aq_q[446]
    DIRECTION INPUT ;
    USE SIGNAL ;
    PORT
      LAYER M3 ;
        RECT  56.592 0 56.61 0.144 ;
    END
  END aq_q[446]
  PIN aq_q[447]
    DIRECTION INPUT ;
    USE SIGNAL ;
    PORT
      LAYER M5 ;
        RECT  56.64 0 56.664 0.192 ;
    END
  END aq_q[447]
  PIN aq_q[448]
    DIRECTION INPUT ;
    USE SIGNAL ;
    PORT
      LAYER M3 ;
        RECT  56.736 0 56.754 0.144 ;
    END
  END aq_q[448]
  PIN aq_q[449]
    DIRECTION INPUT ;
    USE SIGNAL ;
    PORT
      LAYER M5 ;
        RECT  56.784 0 56.808 0.192 ;
    END
  END aq_q[449]
  PIN aq_q[44]
    DIRECTION INPUT ;
    USE SIGNAL ;
    PORT
      LAYER M3 ;
        RECT  27.648 0 27.666 0.144 ;
    END
  END aq_q[44]
  PIN aq_q[450]
    DIRECTION INPUT ;
    USE SIGNAL ;
    PORT
      LAYER M3 ;
        RECT  56.88 0 56.898 0.144 ;
    END
  END aq_q[450]
  PIN aq_q[451]
    DIRECTION INPUT ;
    USE SIGNAL ;
    PORT
      LAYER M5 ;
        RECT  56.928 0 56.952 0.192 ;
    END
  END aq_q[451]
  PIN aq_q[452]
    DIRECTION INPUT ;
    USE SIGNAL ;
    PORT
      LAYER M3 ;
        RECT  57.024 0 57.042 0.144 ;
    END
  END aq_q[452]
  PIN aq_q[453]
    DIRECTION INPUT ;
    USE SIGNAL ;
    PORT
      LAYER M5 ;
        RECT  57.072 0 57.096 0.192 ;
    END
  END aq_q[453]
  PIN aq_q[454]
    DIRECTION INPUT ;
    USE SIGNAL ;
    PORT
      LAYER M3 ;
        RECT  57.168 0 57.186 0.144 ;
    END
  END aq_q[454]
  PIN aq_q[455]
    DIRECTION INPUT ;
    USE SIGNAL ;
    PORT
      LAYER M5 ;
        RECT  57.216 0 57.24 0.192 ;
    END
  END aq_q[455]
  PIN aq_q[456]
    DIRECTION INPUT ;
    USE SIGNAL ;
    PORT
      LAYER M3 ;
        RECT  57.312 0 57.33 0.144 ;
    END
  END aq_q[456]
  PIN aq_q[457]
    DIRECTION INPUT ;
    USE SIGNAL ;
    PORT
      LAYER M5 ;
        RECT  57.36 0 57.384 0.192 ;
    END
  END aq_q[457]
  PIN aq_q[458]
    DIRECTION INPUT ;
    USE SIGNAL ;
    PORT
      LAYER M3 ;
        RECT  57.456 0 57.474 0.144 ;
    END
  END aq_q[458]
  PIN aq_q[459]
    DIRECTION INPUT ;
    USE SIGNAL ;
    PORT
      LAYER M5 ;
        RECT  57.504 0 57.528 0.192 ;
    END
  END aq_q[459]
  PIN aq_q[45]
    DIRECTION INPUT ;
    USE SIGNAL ;
    PORT
      LAYER M5 ;
        RECT  27.696 0 27.72 0.192 ;
    END
  END aq_q[45]
  PIN aq_q[460]
    DIRECTION INPUT ;
    USE SIGNAL ;
    PORT
      LAYER M3 ;
        RECT  57.6 0 57.618 0.144 ;
    END
  END aq_q[460]
  PIN aq_q[461]
    DIRECTION INPUT ;
    USE SIGNAL ;
    PORT
      LAYER M5 ;
        RECT  57.648 0 57.672 0.192 ;
    END
  END aq_q[461]
  PIN aq_q[462]
    DIRECTION INPUT ;
    USE SIGNAL ;
    PORT
      LAYER M3 ;
        RECT  57.744 0 57.762 0.144 ;
    END
  END aq_q[462]
  PIN aq_q[463]
    DIRECTION INPUT ;
    USE SIGNAL ;
    PORT
      LAYER M5 ;
        RECT  57.792 0 57.816 0.192 ;
    END
  END aq_q[463]
  PIN aq_q[464]
    DIRECTION INPUT ;
    USE SIGNAL ;
    PORT
      LAYER M3 ;
        RECT  57.888 0 57.906 0.144 ;
    END
  END aq_q[464]
  PIN aq_q[465]
    DIRECTION INPUT ;
    USE SIGNAL ;
    PORT
      LAYER M5 ;
        RECT  57.936 0 57.96 0.192 ;
    END
  END aq_q[465]
  PIN aq_q[466]
    DIRECTION INPUT ;
    USE SIGNAL ;
    PORT
      LAYER M3 ;
        RECT  58.032 0 58.05 0.144 ;
    END
  END aq_q[466]
  PIN aq_q[467]
    DIRECTION INPUT ;
    USE SIGNAL ;
    PORT
      LAYER M5 ;
        RECT  58.08 0 58.104 0.192 ;
    END
  END aq_q[467]
  PIN aq_q[468]
    DIRECTION INPUT ;
    USE SIGNAL ;
    PORT
      LAYER M3 ;
        RECT  58.176 0 58.194 0.144 ;
    END
  END aq_q[468]
  PIN aq_q[469]
    DIRECTION INPUT ;
    USE SIGNAL ;
    PORT
      LAYER M5 ;
        RECT  58.224 0 58.248 0.192 ;
    END
  END aq_q[469]
  PIN aq_q[46]
    DIRECTION INPUT ;
    USE SIGNAL ;
    PORT
      LAYER M3 ;
        RECT  27.792 0 27.81 0.144 ;
    END
  END aq_q[46]
  PIN aq_q[470]
    DIRECTION INPUT ;
    USE SIGNAL ;
    PORT
      LAYER M3 ;
        RECT  58.32 0 58.338 0.144 ;
    END
  END aq_q[470]
  PIN aq_q[471]
    DIRECTION INPUT ;
    USE SIGNAL ;
    PORT
      LAYER M5 ;
        RECT  58.368 0 58.392 0.192 ;
    END
  END aq_q[471]
  PIN aq_q[472]
    DIRECTION INPUT ;
    USE SIGNAL ;
    PORT
      LAYER M3 ;
        RECT  58.464 0 58.482 0.144 ;
    END
  END aq_q[472]
  PIN aq_q[473]
    DIRECTION INPUT ;
    USE SIGNAL ;
    PORT
      LAYER M5 ;
        RECT  58.512 0 58.536 0.192 ;
    END
  END aq_q[473]
  PIN aq_q[474]
    DIRECTION INPUT ;
    USE SIGNAL ;
    PORT
      LAYER M3 ;
        RECT  58.608 0 58.626 0.144 ;
    END
  END aq_q[474]
  PIN aq_q[475]
    DIRECTION INPUT ;
    USE SIGNAL ;
    PORT
      LAYER M5 ;
        RECT  58.656 0 58.68 0.192 ;
    END
  END aq_q[475]
  PIN aq_q[476]
    DIRECTION INPUT ;
    USE SIGNAL ;
    PORT
      LAYER M3 ;
        RECT  58.752 0 58.77 0.144 ;
    END
  END aq_q[476]
  PIN aq_q[477]
    DIRECTION INPUT ;
    USE SIGNAL ;
    PORT
      LAYER M5 ;
        RECT  58.8 0 58.824 0.192 ;
    END
  END aq_q[477]
  PIN aq_q[478]
    DIRECTION INPUT ;
    USE SIGNAL ;
    PORT
      LAYER M3 ;
        RECT  58.896 0 58.914 0.144 ;
    END
  END aq_q[478]
  PIN aq_q[479]
    DIRECTION INPUT ;
    USE SIGNAL ;
    PORT
      LAYER M5 ;
        RECT  58.944 0 58.968 0.192 ;
    END
  END aq_q[479]
  PIN aq_q[47]
    DIRECTION INPUT ;
    USE SIGNAL ;
    PORT
      LAYER M5 ;
        RECT  27.84 0 27.864 0.192 ;
    END
  END aq_q[47]
  PIN aq_q[480]
    DIRECTION INPUT ;
    USE SIGNAL ;
    PORT
      LAYER M3 ;
        RECT  59.04 0 59.058 0.144 ;
    END
  END aq_q[480]
  PIN aq_q[481]
    DIRECTION INPUT ;
    USE SIGNAL ;
    PORT
      LAYER M5 ;
        RECT  59.088 0 59.112 0.192 ;
    END
  END aq_q[481]
  PIN aq_q[482]
    DIRECTION INPUT ;
    USE SIGNAL ;
    PORT
      LAYER M3 ;
        RECT  59.184 0 59.202 0.144 ;
    END
  END aq_q[482]
  PIN aq_q[483]
    DIRECTION INPUT ;
    USE SIGNAL ;
    PORT
      LAYER M5 ;
        RECT  59.232 0 59.256 0.192 ;
    END
  END aq_q[483]
  PIN aq_q[484]
    DIRECTION INPUT ;
    USE SIGNAL ;
    PORT
      LAYER M3 ;
        RECT  59.328 0 59.346 0.144 ;
    END
  END aq_q[484]
  PIN aq_q[485]
    DIRECTION INPUT ;
    USE SIGNAL ;
    PORT
      LAYER M5 ;
        RECT  59.376 0 59.4 0.192 ;
    END
  END aq_q[485]
  PIN aq_q[486]
    DIRECTION INPUT ;
    USE SIGNAL ;
    PORT
      LAYER M3 ;
        RECT  59.472 0 59.49 0.144 ;
    END
  END aq_q[486]
  PIN aq_q[487]
    DIRECTION INPUT ;
    USE SIGNAL ;
    PORT
      LAYER M5 ;
        RECT  59.52 0 59.544 0.192 ;
    END
  END aq_q[487]
  PIN aq_q[488]
    DIRECTION INPUT ;
    USE SIGNAL ;
    PORT
      LAYER M3 ;
        RECT  59.616 0 59.634 0.144 ;
    END
  END aq_q[488]
  PIN aq_q[489]
    DIRECTION INPUT ;
    USE SIGNAL ;
    PORT
      LAYER M5 ;
        RECT  59.664 0 59.688 0.192 ;
    END
  END aq_q[489]
  PIN aq_q[48]
    DIRECTION INPUT ;
    USE SIGNAL ;
    PORT
      LAYER M3 ;
        RECT  27.936 0 27.954 0.144 ;
    END
  END aq_q[48]
  PIN aq_q[490]
    DIRECTION INPUT ;
    USE SIGNAL ;
    PORT
      LAYER M3 ;
        RECT  59.76 0 59.778 0.144 ;
    END
  END aq_q[490]
  PIN aq_q[491]
    DIRECTION INPUT ;
    USE SIGNAL ;
    PORT
      LAYER M5 ;
        RECT  59.808 0 59.832 0.192 ;
    END
  END aq_q[491]
  PIN aq_q[492]
    DIRECTION INPUT ;
    USE SIGNAL ;
    PORT
      LAYER M3 ;
        RECT  59.904 0 59.922 0.144 ;
    END
  END aq_q[492]
  PIN aq_q[493]
    DIRECTION INPUT ;
    USE SIGNAL ;
    PORT
      LAYER M5 ;
        RECT  59.952 0 59.976 0.192 ;
    END
  END aq_q[493]
  PIN aq_q[494]
    DIRECTION INPUT ;
    USE SIGNAL ;
    PORT
      LAYER M3 ;
        RECT  60.048 0 60.066 0.144 ;
    END
  END aq_q[494]
  PIN aq_q[495]
    DIRECTION INPUT ;
    USE SIGNAL ;
    PORT
      LAYER M5 ;
        RECT  60.096 0 60.12 0.192 ;
    END
  END aq_q[495]
  PIN aq_q[496]
    DIRECTION INPUT ;
    USE SIGNAL ;
    PORT
      LAYER M3 ;
        RECT  60.192 0 60.21 0.144 ;
    END
  END aq_q[496]
  PIN aq_q[497]
    DIRECTION INPUT ;
    USE SIGNAL ;
    PORT
      LAYER M5 ;
        RECT  60.24 0 60.264 0.192 ;
    END
  END aq_q[497]
  PIN aq_q[498]
    DIRECTION INPUT ;
    USE SIGNAL ;
    PORT
      LAYER M3 ;
        RECT  60.336 0 60.354 0.144 ;
    END
  END aq_q[498]
  PIN aq_q[499]
    DIRECTION INPUT ;
    USE SIGNAL ;
    PORT
      LAYER M5 ;
        RECT  60.384 0 60.408 0.192 ;
    END
  END aq_q[499]
  PIN aq_q[49]
    DIRECTION INPUT ;
    USE SIGNAL ;
    PORT
      LAYER M5 ;
        RECT  27.984 0 28.008 0.192 ;
    END
  END aq_q[49]
  PIN aq_q[4]
    DIRECTION INPUT ;
    USE SIGNAL ;
    PORT
      LAYER M3 ;
        RECT  24.768 0 24.786 0.144 ;
    END
  END aq_q[4]
  PIN aq_q[500]
    DIRECTION INPUT ;
    USE SIGNAL ;
    PORT
      LAYER M3 ;
        RECT  60.48 0 60.498 0.144 ;
    END
  END aq_q[500]
  PIN aq_q[501]
    DIRECTION INPUT ;
    USE SIGNAL ;
    PORT
      LAYER M5 ;
        RECT  60.528 0 60.552 0.192 ;
    END
  END aq_q[501]
  PIN aq_q[502]
    DIRECTION INPUT ;
    USE SIGNAL ;
    PORT
      LAYER M3 ;
        RECT  60.624 0 60.642 0.144 ;
    END
  END aq_q[502]
  PIN aq_q[503]
    DIRECTION INPUT ;
    USE SIGNAL ;
    PORT
      LAYER M5 ;
        RECT  60.672 0 60.696 0.192 ;
    END
  END aq_q[503]
  PIN aq_q[504]
    DIRECTION INPUT ;
    USE SIGNAL ;
    PORT
      LAYER M3 ;
        RECT  60.768 0 60.786 0.144 ;
    END
  END aq_q[504]
  PIN aq_q[505]
    DIRECTION INPUT ;
    USE SIGNAL ;
    PORT
      LAYER M5 ;
        RECT  60.816 0 60.84 0.192 ;
    END
  END aq_q[505]
  PIN aq_q[506]
    DIRECTION INPUT ;
    USE SIGNAL ;
    PORT
      LAYER M3 ;
        RECT  60.912 0 60.93 0.144 ;
    END
  END aq_q[506]
  PIN aq_q[507]
    DIRECTION INPUT ;
    USE SIGNAL ;
    PORT
      LAYER M5 ;
        RECT  60.96 0 60.984 0.192 ;
    END
  END aq_q[507]
  PIN aq_q[508]
    DIRECTION INPUT ;
    USE SIGNAL ;
    PORT
      LAYER M3 ;
        RECT  61.056 0 61.074 0.144 ;
    END
  END aq_q[508]
  PIN aq_q[509]
    DIRECTION INPUT ;
    USE SIGNAL ;
    PORT
      LAYER M5 ;
        RECT  61.104 0 61.128 0.192 ;
    END
  END aq_q[509]
  PIN aq_q[50]
    DIRECTION INPUT ;
    USE SIGNAL ;
    PORT
      LAYER M3 ;
        RECT  28.08 0 28.098 0.144 ;
    END
  END aq_q[50]
  PIN aq_q[510]
    DIRECTION INPUT ;
    USE SIGNAL ;
    PORT
      LAYER M3 ;
        RECT  61.2 0 61.218 0.144 ;
    END
  END aq_q[510]
  PIN aq_q[511]
    DIRECTION INPUT ;
    USE SIGNAL ;
    PORT
      LAYER M5 ;
        RECT  61.248 0 61.272 0.192 ;
    END
  END aq_q[511]
  PIN aq_q[51]
    DIRECTION INPUT ;
    USE SIGNAL ;
    PORT
      LAYER M5 ;
        RECT  28.128 0 28.152 0.192 ;
    END
  END aq_q[51]
  PIN aq_q[52]
    DIRECTION INPUT ;
    USE SIGNAL ;
    PORT
      LAYER M3 ;
        RECT  28.224 0 28.242 0.144 ;
    END
  END aq_q[52]
  PIN aq_q[53]
    DIRECTION INPUT ;
    USE SIGNAL ;
    PORT
      LAYER M5 ;
        RECT  28.272 0 28.296 0.192 ;
    END
  END aq_q[53]
  PIN aq_q[54]
    DIRECTION INPUT ;
    USE SIGNAL ;
    PORT
      LAYER M3 ;
        RECT  28.368 0 28.386 0.144 ;
    END
  END aq_q[54]
  PIN aq_q[55]
    DIRECTION INPUT ;
    USE SIGNAL ;
    PORT
      LAYER M5 ;
        RECT  28.416 0 28.44 0.192 ;
    END
  END aq_q[55]
  PIN aq_q[56]
    DIRECTION INPUT ;
    USE SIGNAL ;
    PORT
      LAYER M3 ;
        RECT  28.512 0 28.53 0.144 ;
    END
  END aq_q[56]
  PIN aq_q[57]
    DIRECTION INPUT ;
    USE SIGNAL ;
    PORT
      LAYER M5 ;
        RECT  28.56 0 28.584 0.192 ;
    END
  END aq_q[57]
  PIN aq_q[58]
    DIRECTION INPUT ;
    USE SIGNAL ;
    PORT
      LAYER M3 ;
        RECT  28.656 0 28.674 0.144 ;
    END
  END aq_q[58]
  PIN aq_q[59]
    DIRECTION INPUT ;
    USE SIGNAL ;
    PORT
      LAYER M5 ;
        RECT  28.704 0 28.728 0.192 ;
    END
  END aq_q[59]
  PIN aq_q[5]
    DIRECTION INPUT ;
    USE SIGNAL ;
    PORT
      LAYER M5 ;
        RECT  24.816 0 24.84 0.192 ;
    END
  END aq_q[5]
  PIN aq_q[60]
    DIRECTION INPUT ;
    USE SIGNAL ;
    PORT
      LAYER M3 ;
        RECT  28.8 0 28.818 0.144 ;
    END
  END aq_q[60]
  PIN aq_q[61]
    DIRECTION INPUT ;
    USE SIGNAL ;
    PORT
      LAYER M5 ;
        RECT  28.848 0 28.872 0.192 ;
    END
  END aq_q[61]
  PIN aq_q[62]
    DIRECTION INPUT ;
    USE SIGNAL ;
    PORT
      LAYER M3 ;
        RECT  28.944 0 28.962 0.144 ;
    END
  END aq_q[62]
  PIN aq_q[63]
    DIRECTION INPUT ;
    USE SIGNAL ;
    PORT
      LAYER M5 ;
        RECT  28.992 0 29.016 0.192 ;
    END
  END aq_q[63]
  PIN aq_q[64]
    DIRECTION INPUT ;
    USE SIGNAL ;
    PORT
      LAYER M3 ;
        RECT  29.088 0 29.106 0.144 ;
    END
  END aq_q[64]
  PIN aq_q[65]
    DIRECTION INPUT ;
    USE SIGNAL ;
    PORT
      LAYER M5 ;
        RECT  29.136 0 29.16 0.192 ;
    END
  END aq_q[65]
  PIN aq_q[66]
    DIRECTION INPUT ;
    USE SIGNAL ;
    PORT
      LAYER M3 ;
        RECT  29.232 0 29.25 0.144 ;
    END
  END aq_q[66]
  PIN aq_q[67]
    DIRECTION INPUT ;
    USE SIGNAL ;
    PORT
      LAYER M5 ;
        RECT  29.28 0 29.304 0.192 ;
    END
  END aq_q[67]
  PIN aq_q[68]
    DIRECTION INPUT ;
    USE SIGNAL ;
    PORT
      LAYER M3 ;
        RECT  29.376 0 29.394 0.144 ;
    END
  END aq_q[68]
  PIN aq_q[69]
    DIRECTION INPUT ;
    USE SIGNAL ;
    PORT
      LAYER M5 ;
        RECT  29.424 0 29.448 0.192 ;
    END
  END aq_q[69]
  PIN aq_q[6]
    DIRECTION INPUT ;
    USE SIGNAL ;
    PORT
      LAYER M3 ;
        RECT  24.912 0 24.93 0.144 ;
    END
  END aq_q[6]
  PIN aq_q[70]
    DIRECTION INPUT ;
    USE SIGNAL ;
    PORT
      LAYER M3 ;
        RECT  29.52 0 29.538 0.144 ;
    END
  END aq_q[70]
  PIN aq_q[71]
    DIRECTION INPUT ;
    USE SIGNAL ;
    PORT
      LAYER M5 ;
        RECT  29.568 0 29.592 0.192 ;
    END
  END aq_q[71]
  PIN aq_q[72]
    DIRECTION INPUT ;
    USE SIGNAL ;
    PORT
      LAYER M3 ;
        RECT  29.664 0 29.682 0.144 ;
    END
  END aq_q[72]
  PIN aq_q[73]
    DIRECTION INPUT ;
    USE SIGNAL ;
    PORT
      LAYER M5 ;
        RECT  29.712 0 29.736 0.192 ;
    END
  END aq_q[73]
  PIN aq_q[74]
    DIRECTION INPUT ;
    USE SIGNAL ;
    PORT
      LAYER M3 ;
        RECT  29.808 0 29.826 0.144 ;
    END
  END aq_q[74]
  PIN aq_q[75]
    DIRECTION INPUT ;
    USE SIGNAL ;
    PORT
      LAYER M5 ;
        RECT  29.856 0 29.88 0.192 ;
    END
  END aq_q[75]
  PIN aq_q[76]
    DIRECTION INPUT ;
    USE SIGNAL ;
    PORT
      LAYER M3 ;
        RECT  29.952 0 29.97 0.144 ;
    END
  END aq_q[76]
  PIN aq_q[77]
    DIRECTION INPUT ;
    USE SIGNAL ;
    PORT
      LAYER M5 ;
        RECT  30 0 30.024 0.192 ;
    END
  END aq_q[77]
  PIN aq_q[78]
    DIRECTION INPUT ;
    USE SIGNAL ;
    PORT
      LAYER M3 ;
        RECT  30.096 0 30.114 0.144 ;
    END
  END aq_q[78]
  PIN aq_q[79]
    DIRECTION INPUT ;
    USE SIGNAL ;
    PORT
      LAYER M5 ;
        RECT  30.144 0 30.168 0.192 ;
    END
  END aq_q[79]
  PIN aq_q[7]
    DIRECTION INPUT ;
    USE SIGNAL ;
    PORT
      LAYER M5 ;
        RECT  24.96 0 24.984 0.192 ;
    END
  END aq_q[7]
  PIN aq_q[80]
    DIRECTION INPUT ;
    USE SIGNAL ;
    PORT
      LAYER M3 ;
        RECT  30.24 0 30.258 0.144 ;
    END
  END aq_q[80]
  PIN aq_q[81]
    DIRECTION INPUT ;
    USE SIGNAL ;
    PORT
      LAYER M5 ;
        RECT  30.288 0 30.312 0.192 ;
    END
  END aq_q[81]
  PIN aq_q[82]
    DIRECTION INPUT ;
    USE SIGNAL ;
    PORT
      LAYER M3 ;
        RECT  30.384 0 30.402 0.144 ;
    END
  END aq_q[82]
  PIN aq_q[83]
    DIRECTION INPUT ;
    USE SIGNAL ;
    PORT
      LAYER M5 ;
        RECT  30.432 0 30.456 0.192 ;
    END
  END aq_q[83]
  PIN aq_q[84]
    DIRECTION INPUT ;
    USE SIGNAL ;
    PORT
      LAYER M3 ;
        RECT  30.528 0 30.546 0.144 ;
    END
  END aq_q[84]
  PIN aq_q[85]
    DIRECTION INPUT ;
    USE SIGNAL ;
    PORT
      LAYER M5 ;
        RECT  30.576 0 30.6 0.192 ;
    END
  END aq_q[85]
  PIN aq_q[86]
    DIRECTION INPUT ;
    USE SIGNAL ;
    PORT
      LAYER M3 ;
        RECT  30.672 0 30.69 0.144 ;
    END
  END aq_q[86]
  PIN aq_q[87]
    DIRECTION INPUT ;
    USE SIGNAL ;
    PORT
      LAYER M5 ;
        RECT  30.72 0 30.744 0.192 ;
    END
  END aq_q[87]
  PIN aq_q[88]
    DIRECTION INPUT ;
    USE SIGNAL ;
    PORT
      LAYER M3 ;
        RECT  30.816 0 30.834 0.144 ;
    END
  END aq_q[88]
  PIN aq_q[89]
    DIRECTION INPUT ;
    USE SIGNAL ;
    PORT
      LAYER M5 ;
        RECT  30.864 0 30.888 0.192 ;
    END
  END aq_q[89]
  PIN aq_q[8]
    DIRECTION INPUT ;
    USE SIGNAL ;
    PORT
      LAYER M3 ;
        RECT  25.056 0 25.074 0.144 ;
    END
  END aq_q[8]
  PIN aq_q[90]
    DIRECTION INPUT ;
    USE SIGNAL ;
    PORT
      LAYER M3 ;
        RECT  30.96 0 30.978 0.144 ;
    END
  END aq_q[90]
  PIN aq_q[91]
    DIRECTION INPUT ;
    USE SIGNAL ;
    PORT
      LAYER M5 ;
        RECT  31.008 0 31.032 0.192 ;
    END
  END aq_q[91]
  PIN aq_q[92]
    DIRECTION INPUT ;
    USE SIGNAL ;
    PORT
      LAYER M3 ;
        RECT  31.104 0 31.122 0.144 ;
    END
  END aq_q[92]
  PIN aq_q[93]
    DIRECTION INPUT ;
    USE SIGNAL ;
    PORT
      LAYER M5 ;
        RECT  31.152 0 31.176 0.192 ;
    END
  END aq_q[93]
  PIN aq_q[94]
    DIRECTION INPUT ;
    USE SIGNAL ;
    PORT
      LAYER M3 ;
        RECT  31.248 0 31.266 0.144 ;
    END
  END aq_q[94]
  PIN aq_q[95]
    DIRECTION INPUT ;
    USE SIGNAL ;
    PORT
      LAYER M5 ;
        RECT  31.296 0 31.32 0.192 ;
    END
  END aq_q[95]
  PIN aq_q[96]
    DIRECTION INPUT ;
    USE SIGNAL ;
    PORT
      LAYER M3 ;
        RECT  31.392 0 31.41 0.144 ;
    END
  END aq_q[96]
  PIN aq_q[97]
    DIRECTION INPUT ;
    USE SIGNAL ;
    PORT
      LAYER M5 ;
        RECT  31.44 0 31.464 0.192 ;
    END
  END aq_q[97]
  PIN aq_q[98]
    DIRECTION INPUT ;
    USE SIGNAL ;
    PORT
      LAYER M3 ;
        RECT  31.536 0 31.554 0.144 ;
    END
  END aq_q[98]
  PIN aq_q[99]
    DIRECTION INPUT ;
    USE SIGNAL ;
    PORT
      LAYER M5 ;
        RECT  31.584 0 31.608 0.192 ;
    END
  END aq_q[99]
  PIN aq_q[9]
    DIRECTION INPUT ;
    USE SIGNAL ;
    PORT
      LAYER M5 ;
        RECT  25.104 0 25.128 0.192 ;
    END
  END aq_q[9]
  PIN clk
    DIRECTION INPUT ;
    USE SIGNAL ;
    PORT
      LAYER M4 ;
        RECT  0 52.032 0.192 52.056 ;
    END
    PORT
      LAYER M4 ;
        RECT  0.156 52.032 1.681 52.056 ;
    END
  END clk
  PIN erd[0]
    DIRECTION OUTPUT ;
    USE SIGNAL ;
    PORT
      LAYER M3 ;
        RECT  47.52 86.256 47.538 86.4 ;
    END
  END erd[0]
  PIN erd[1]
    DIRECTION OUTPUT ;
    USE SIGNAL ;
    PORT
      LAYER M3 ;
        RECT  47.664 86.256 47.682 86.4 ;
    END
  END erd[1]
  PIN erd[2]
    DIRECTION OUTPUT ;
    USE SIGNAL ;
    PORT
      LAYER M3 ;
        RECT  47.808 86.256 47.826 86.4 ;
    END
  END erd[2]
  PIN erd[3]
    DIRECTION OUTPUT ;
    USE SIGNAL ;
    PORT
      LAYER M3 ;
        RECT  47.952 86.256 47.97 86.4 ;
    END
  END erd[3]
  PIN erd[4]
    DIRECTION OUTPUT ;
    USE SIGNAL ;
    PORT
      LAYER M3 ;
        RECT  48.096 86.256 48.114 86.4 ;
    END
  END erd[4]
  PIN erd[5]
    DIRECTION OUTPUT ;
    USE SIGNAL ;
    PORT
      LAYER M3 ;
        RECT  48.24 86.256 48.258 86.4 ;
    END
  END erd[5]
  PIN erd[6]
    DIRECTION OUTPUT ;
    USE SIGNAL ;
    PORT
      LAYER M3 ;
        RECT  48.384 86.256 48.402 86.4 ;
    END
  END erd[6]
  PIN erd[7]
    DIRECTION OUTPUT ;
    USE SIGNAL ;
    PORT
      LAYER M3 ;
        RECT  48.528 86.256 48.546 86.4 ;
    END
  END erd[7]
  PIN erd[8]
    DIRECTION OUTPUT ;
    USE SIGNAL ;
    PORT
      LAYER M3 ;
        RECT  48.672 86.256 48.69 86.4 ;
    END
  END erd[8]
  PIN erd[9]
    DIRECTION OUTPUT ;
    USE SIGNAL ;
    PORT
      LAYER M3 ;
        RECT  48.816 86.256 48.834 86.4 ;
    END
  END erd[9]
  PIN fault
    DIRECTION OUTPUT ;
    USE SIGNAL ;
    PORT
      LAYER M4 ;
        RECT  142.368 52.032 142.56 52.056 ;
    END
    PORT
      LAYER M4 ;
        RECT  141.361 52.032 142.38 52.056 ;
    END
  END fault
  PIN i0[0]
    DIRECTION INPUT ;
    USE SIGNAL ;
    PORT
      LAYER M4 ;
        RECT  0 41.616 0.192 41.64 ;
    END
  END i0[0]
  PIN i0[10]
    DIRECTION INPUT ;
    USE SIGNAL ;
    PORT
      LAYER M4 ;
        RECT  0 43.056 0.192 43.08 ;
    END
  END i0[10]
  PIN i0[11]
    DIRECTION INPUT ;
    USE SIGNAL ;
    PORT
      LAYER M4 ;
        RECT  0 43.2 0.192 43.224 ;
    END
  END i0[11]
  PIN i0[12]
    DIRECTION INPUT ;
    USE SIGNAL ;
    PORT
      LAYER M4 ;
        RECT  0 43.344 0.192 43.368 ;
    END
  END i0[12]
  PIN i0[13]
    DIRECTION INPUT ;
    USE SIGNAL ;
    PORT
      LAYER M4 ;
        RECT  0 43.488 0.192 43.512 ;
    END
  END i0[13]
  PIN i0[14]
    DIRECTION INPUT ;
    USE SIGNAL ;
    PORT
      LAYER M4 ;
        RECT  0 43.632 0.192 43.656 ;
    END
  END i0[14]
  PIN i0[15]
    DIRECTION INPUT ;
    USE SIGNAL ;
    PORT
      LAYER M4 ;
        RECT  0 43.776 0.192 43.8 ;
    END
  END i0[15]
  PIN i0[1]
    DIRECTION INPUT ;
    USE SIGNAL ;
    PORT
      LAYER M4 ;
        RECT  0 41.76 0.192 41.784 ;
    END
  END i0[1]
  PIN i0[2]
    DIRECTION INPUT ;
    USE SIGNAL ;
    PORT
      LAYER M4 ;
        RECT  0 41.904 0.192 41.928 ;
    END
  END i0[2]
  PIN i0[3]
    DIRECTION INPUT ;
    USE SIGNAL ;
    PORT
      LAYER M4 ;
        RECT  0 42.048 0.192 42.072 ;
    END
  END i0[3]
  PIN i0[4]
    DIRECTION INPUT ;
    USE SIGNAL ;
    PORT
      LAYER M4 ;
        RECT  0 42.192 0.192 42.216 ;
    END
  END i0[4]
  PIN i0[5]
    DIRECTION INPUT ;
    USE SIGNAL ;
    PORT
      LAYER M4 ;
        RECT  0 42.336 0.192 42.36 ;
    END
  END i0[5]
  PIN i0[6]
    DIRECTION INPUT ;
    USE SIGNAL ;
    PORT
      LAYER M4 ;
        RECT  0 42.48 0.192 42.504 ;
    END
  END i0[6]
  PIN i0[7]
    DIRECTION INPUT ;
    USE SIGNAL ;
    PORT
      LAYER M4 ;
        RECT  0 42.624 0.192 42.648 ;
    END
  END i0[7]
  PIN i0[8]
    DIRECTION INPUT ;
    USE SIGNAL ;
    PORT
      LAYER M4 ;
        RECT  0 42.768 0.192 42.792 ;
    END
  END i0[8]
  PIN i0[9]
    DIRECTION INPUT ;
    USE SIGNAL ;
    PORT
      LAYER M4 ;
        RECT  0 42.912 0.192 42.936 ;
    END
  END i0[9]
  PIN i1[0]
    DIRECTION INPUT ;
    USE SIGNAL ;
    PORT
      LAYER M4 ;
        RECT  0 43.92 0.192 43.944 ;
    END
  END i1[0]
  PIN i1[10]
    DIRECTION INPUT ;
    USE SIGNAL ;
    PORT
      LAYER M4 ;
        RECT  0 45.36 0.192 45.384 ;
    END
  END i1[10]
  PIN i1[11]
    DIRECTION INPUT ;
    USE SIGNAL ;
    PORT
      LAYER M4 ;
        RECT  0 45.504 0.192 45.528 ;
    END
  END i1[11]
  PIN i1[12]
    DIRECTION INPUT ;
    USE SIGNAL ;
    PORT
      LAYER M4 ;
        RECT  0 45.648 0.192 45.672 ;
    END
  END i1[12]
  PIN i1[13]
    DIRECTION INPUT ;
    USE SIGNAL ;
    PORT
      LAYER M4 ;
        RECT  0 45.792 0.192 45.816 ;
    END
  END i1[13]
  PIN i1[14]
    DIRECTION INPUT ;
    USE SIGNAL ;
    PORT
      LAYER M4 ;
        RECT  0 45.936 0.192 45.96 ;
    END
  END i1[14]
  PIN i1[15]
    DIRECTION INPUT ;
    USE SIGNAL ;
    PORT
      LAYER M4 ;
        RECT  0 46.08 0.192 46.104 ;
    END
  END i1[15]
  PIN i1[1]
    DIRECTION INPUT ;
    USE SIGNAL ;
    PORT
      LAYER M4 ;
        RECT  0 44.064 0.192 44.088 ;
    END
  END i1[1]
  PIN i1[2]
    DIRECTION INPUT ;
    USE SIGNAL ;
    PORT
      LAYER M4 ;
        RECT  0 44.208 0.192 44.232 ;
    END
  END i1[2]
  PIN i1[3]
    DIRECTION INPUT ;
    USE SIGNAL ;
    PORT
      LAYER M4 ;
        RECT  0 44.352 0.192 44.376 ;
    END
  END i1[3]
  PIN i1[4]
    DIRECTION INPUT ;
    USE SIGNAL ;
    PORT
      LAYER M4 ;
        RECT  0 44.496 0.192 44.52 ;
    END
  END i1[4]
  PIN i1[5]
    DIRECTION INPUT ;
    USE SIGNAL ;
    PORT
      LAYER M4 ;
        RECT  0 44.64 0.192 44.664 ;
    END
  END i1[5]
  PIN i1[6]
    DIRECTION INPUT ;
    USE SIGNAL ;
    PORT
      LAYER M4 ;
        RECT  0 44.784 0.192 44.808 ;
    END
  END i1[6]
  PIN i1[7]
    DIRECTION INPUT ;
    USE SIGNAL ;
    PORT
      LAYER M4 ;
        RECT  0 44.928 0.192 44.952 ;
    END
  END i1[7]
  PIN i1[8]
    DIRECTION INPUT ;
    USE SIGNAL ;
    PORT
      LAYER M4 ;
        RECT  0 45.072 0.192 45.096 ;
    END
  END i1[8]
  PIN i1[9]
    DIRECTION INPUT ;
    USE SIGNAL ;
    PORT
      LAYER M4 ;
        RECT  0 45.216 0.192 45.24 ;
    END
  END i1[9]
  PIN ph0[0]
    DIRECTION INPUT ;
    USE SIGNAL ;
    PORT
      LAYER M4 ;
        RECT  0 38.448 0.192 38.472 ;
    END
  END ph0[0]
  PIN ph0[1]
    DIRECTION INPUT ;
    USE SIGNAL ;
    PORT
      LAYER M4 ;
        RECT  0 38.304 0.192 38.328 ;
    END
  END ph0[1]
  PIN ph0[2]
    DIRECTION INPUT ;
    USE SIGNAL ;
    PORT
      LAYER M4 ;
        RECT  0 38.16 0.192 38.184 ;
    END
  END ph0[2]
  PIN ph0[3]
    DIRECTION INPUT ;
    USE SIGNAL ;
    PORT
      LAYER M4 ;
        RECT  0 38.016 0.192 38.04 ;
    END
  END ph0[3]
  PIN ph0[4]
    DIRECTION INPUT ;
    USE SIGNAL ;
    PORT
      LAYER M4 ;
        RECT  0 37.872 0.192 37.896 ;
    END
  END ph0[4]
  PIN ph0[5]
    DIRECTION INPUT ;
    USE SIGNAL ;
    PORT
      LAYER M4 ;
        RECT  0 37.728 0.192 37.752 ;
    END
  END ph0[5]
  PIN ph1[0]
    DIRECTION INPUT ;
    USE SIGNAL ;
    PORT
      LAYER M4 ;
        RECT  0 37.584 0.192 37.608 ;
    END
  END ph1[0]
  PIN ph1[1]
    DIRECTION INPUT ;
    USE SIGNAL ;
    PORT
      LAYER M4 ;
        RECT  0 37.44 0.192 37.464 ;
    END
  END ph1[1]
  PIN ph1[2]
    DIRECTION INPUT ;
    USE SIGNAL ;
    PORT
      LAYER M4 ;
        RECT  0 37.296 0.192 37.32 ;
    END
  END ph1[2]
  PIN ph1[3]
    DIRECTION INPUT ;
    USE SIGNAL ;
    PORT
      LAYER M4 ;
        RECT  0 37.152 0.192 37.176 ;
    END
  END ph1[3]
  PIN ph1[4]
    DIRECTION INPUT ;
    USE SIGNAL ;
    PORT
      LAYER M4 ;
        RECT  0 37.008 0.192 37.032 ;
    END
  END ph1[4]
  PIN ph1[5]
    DIRECTION INPUT ;
    USE SIGNAL ;
    PORT
      LAYER M4 ;
        RECT  0 36.864 0.192 36.888 ;
    END
  END ph1[5]
  PIN pl0[0]
    DIRECTION INPUT ;
    USE SIGNAL ;
    PORT
      LAYER M4 ;
        RECT  0 36.72 0.192 36.744 ;
    END
  END pl0[0]
  PIN pl0[10]
    DIRECTION INPUT ;
    USE SIGNAL ;
    PORT
      LAYER M4 ;
        RECT  0 35.28 0.192 35.304 ;
    END
  END pl0[10]
  PIN pl0[11]
    DIRECTION INPUT ;
    USE SIGNAL ;
    PORT
      LAYER M4 ;
        RECT  0 35.136 0.192 35.16 ;
    END
  END pl0[11]
  PIN pl0[12]
    DIRECTION INPUT ;
    USE SIGNAL ;
    PORT
      LAYER M4 ;
        RECT  0 34.992 0.192 35.016 ;
    END
  END pl0[12]
  PIN pl0[13]
    DIRECTION INPUT ;
    USE SIGNAL ;
    PORT
      LAYER M4 ;
        RECT  0 34.848 0.192 34.872 ;
    END
  END pl0[13]
  PIN pl0[14]
    DIRECTION INPUT ;
    USE SIGNAL ;
    PORT
      LAYER M4 ;
        RECT  0 34.704 0.192 34.728 ;
    END
  END pl0[14]
  PIN pl0[15]
    DIRECTION INPUT ;
    USE SIGNAL ;
    PORT
      LAYER M4 ;
        RECT  0 34.56 0.192 34.584 ;
    END
  END pl0[15]
  PIN pl0[1]
    DIRECTION INPUT ;
    USE SIGNAL ;
    PORT
      LAYER M4 ;
        RECT  0 36.576 0.192 36.6 ;
    END
  END pl0[1]
  PIN pl0[2]
    DIRECTION INPUT ;
    USE SIGNAL ;
    PORT
      LAYER M4 ;
        RECT  0 36.432 0.192 36.456 ;
    END
  END pl0[2]
  PIN pl0[3]
    DIRECTION INPUT ;
    USE SIGNAL ;
    PORT
      LAYER M4 ;
        RECT  0 36.288 0.192 36.312 ;
    END
  END pl0[3]
  PIN pl0[4]
    DIRECTION INPUT ;
    USE SIGNAL ;
    PORT
      LAYER M4 ;
        RECT  0 36.144 0.192 36.168 ;
    END
  END pl0[4]
  PIN pl0[5]
    DIRECTION INPUT ;
    USE SIGNAL ;
    PORT
      LAYER M4 ;
        RECT  0 36 0.192 36.024 ;
    END
  END pl0[5]
  PIN pl0[6]
    DIRECTION INPUT ;
    USE SIGNAL ;
    PORT
      LAYER M4 ;
        RECT  0 35.856 0.192 35.88 ;
    END
  END pl0[6]
  PIN pl0[7]
    DIRECTION INPUT ;
    USE SIGNAL ;
    PORT
      LAYER M4 ;
        RECT  0 35.712 0.192 35.736 ;
    END
  END pl0[7]
  PIN pl0[8]
    DIRECTION INPUT ;
    USE SIGNAL ;
    PORT
      LAYER M4 ;
        RECT  0 35.568 0.192 35.592 ;
    END
  END pl0[8]
  PIN pl0[9]
    DIRECTION INPUT ;
    USE SIGNAL ;
    PORT
      LAYER M4 ;
        RECT  0 35.424 0.192 35.448 ;
    END
  END pl0[9]
  PIN pl1[0]
    DIRECTION INPUT ;
    USE SIGNAL ;
    PORT
      LAYER M4 ;
        RECT  0 34.416 0.192 34.44 ;
    END
  END pl1[0]
  PIN pl1[10]
    DIRECTION INPUT ;
    USE SIGNAL ;
    PORT
      LAYER M4 ;
        RECT  0 32.976 0.192 33 ;
    END
  END pl1[10]
  PIN pl1[11]
    DIRECTION INPUT ;
    USE SIGNAL ;
    PORT
      LAYER M4 ;
        RECT  0 32.832 0.192 32.856 ;
    END
  END pl1[11]
  PIN pl1[12]
    DIRECTION INPUT ;
    USE SIGNAL ;
    PORT
      LAYER M4 ;
        RECT  0 32.688 0.192 32.712 ;
    END
  END pl1[12]
  PIN pl1[13]
    DIRECTION INPUT ;
    USE SIGNAL ;
    PORT
      LAYER M4 ;
        RECT  0 32.544 0.192 32.568 ;
    END
  END pl1[13]
  PIN pl1[14]
    DIRECTION INPUT ;
    USE SIGNAL ;
    PORT
      LAYER M4 ;
        RECT  0 32.4 0.192 32.424 ;
    END
  END pl1[14]
  PIN pl1[15]
    DIRECTION INPUT ;
    USE SIGNAL ;
    PORT
      LAYER M4 ;
        RECT  0 32.256 0.192 32.28 ;
    END
  END pl1[15]
  PIN pl1[1]
    DIRECTION INPUT ;
    USE SIGNAL ;
    PORT
      LAYER M4 ;
        RECT  0 34.272 0.192 34.296 ;
    END
  END pl1[1]
  PIN pl1[2]
    DIRECTION INPUT ;
    USE SIGNAL ;
    PORT
      LAYER M4 ;
        RECT  0 34.128 0.192 34.152 ;
    END
  END pl1[2]
  PIN pl1[3]
    DIRECTION INPUT ;
    USE SIGNAL ;
    PORT
      LAYER M4 ;
        RECT  0 33.984 0.192 34.008 ;
    END
  END pl1[3]
  PIN pl1[4]
    DIRECTION INPUT ;
    USE SIGNAL ;
    PORT
      LAYER M4 ;
        RECT  0 33.84 0.192 33.864 ;
    END
  END pl1[4]
  PIN pl1[5]
    DIRECTION INPUT ;
    USE SIGNAL ;
    PORT
      LAYER M4 ;
        RECT  0 33.696 0.192 33.72 ;
    END
  END pl1[5]
  PIN pl1[6]
    DIRECTION INPUT ;
    USE SIGNAL ;
    PORT
      LAYER M4 ;
        RECT  0 33.552 0.192 33.576 ;
    END
  END pl1[6]
  PIN pl1[7]
    DIRECTION INPUT ;
    USE SIGNAL ;
    PORT
      LAYER M4 ;
        RECT  0 33.408 0.192 33.432 ;
    END
  END pl1[7]
  PIN pl1[8]
    DIRECTION INPUT ;
    USE SIGNAL ;
    PORT
      LAYER M4 ;
        RECT  0 33.264 0.192 33.288 ;
    END
  END pl1[8]
  PIN pl1[9]
    DIRECTION INPUT ;
    USE SIGNAL ;
    PORT
      LAYER M4 ;
        RECT  0 33.12 0.192 33.144 ;
    END
  END pl1[9]
  PIN rd[0]
    DIRECTION OUTPUT ;
    USE SIGNAL ;
    PORT
      LAYER M3 ;
        RECT  24.48 86.256 24.498 86.4 ;
    END
  END rd[0]
  PIN rd[100]
    DIRECTION OUTPUT ;
    USE SIGNAL ;
    PORT
      LAYER M3 ;
        RECT  31.68 86.256 31.698 86.4 ;
    END
  END rd[100]
  PIN rd[101]
    DIRECTION OUTPUT ;
    USE SIGNAL ;
    PORT
      LAYER M5 ;
        RECT  31.728 86.208 31.752 86.4 ;
    END
  END rd[101]
  PIN rd[102]
    DIRECTION OUTPUT ;
    USE SIGNAL ;
    PORT
      LAYER M3 ;
        RECT  31.824 86.256 31.842 86.4 ;
    END
  END rd[102]
  PIN rd[103]
    DIRECTION OUTPUT ;
    USE SIGNAL ;
    PORT
      LAYER M5 ;
        RECT  31.872 86.208 31.896 86.4 ;
    END
  END rd[103]
  PIN rd[104]
    DIRECTION OUTPUT ;
    USE SIGNAL ;
    PORT
      LAYER M3 ;
        RECT  31.968 86.256 31.986 86.4 ;
    END
  END rd[104]
  PIN rd[105]
    DIRECTION OUTPUT ;
    USE SIGNAL ;
    PORT
      LAYER M5 ;
        RECT  32.016 86.208 32.04 86.4 ;
    END
  END rd[105]
  PIN rd[106]
    DIRECTION OUTPUT ;
    USE SIGNAL ;
    PORT
      LAYER M3 ;
        RECT  32.112 86.256 32.13 86.4 ;
    END
  END rd[106]
  PIN rd[107]
    DIRECTION OUTPUT ;
    USE SIGNAL ;
    PORT
      LAYER M5 ;
        RECT  32.16 86.208 32.184 86.4 ;
    END
  END rd[107]
  PIN rd[108]
    DIRECTION OUTPUT ;
    USE SIGNAL ;
    PORT
      LAYER M3 ;
        RECT  32.256 86.256 32.274 86.4 ;
    END
  END rd[108]
  PIN rd[109]
    DIRECTION OUTPUT ;
    USE SIGNAL ;
    PORT
      LAYER M5 ;
        RECT  32.304 86.208 32.328 86.4 ;
    END
  END rd[109]
  PIN rd[10]
    DIRECTION OUTPUT ;
    USE SIGNAL ;
    PORT
      LAYER M3 ;
        RECT  25.2 86.256 25.218 86.4 ;
    END
  END rd[10]
  PIN rd[110]
    DIRECTION OUTPUT ;
    USE SIGNAL ;
    PORT
      LAYER M3 ;
        RECT  32.4 86.256 32.418 86.4 ;
    END
  END rd[110]
  PIN rd[111]
    DIRECTION OUTPUT ;
    USE SIGNAL ;
    PORT
      LAYER M5 ;
        RECT  32.448 86.208 32.472 86.4 ;
    END
  END rd[111]
  PIN rd[112]
    DIRECTION OUTPUT ;
    USE SIGNAL ;
    PORT
      LAYER M3 ;
        RECT  32.544 86.256 32.562 86.4 ;
    END
  END rd[112]
  PIN rd[113]
    DIRECTION OUTPUT ;
    USE SIGNAL ;
    PORT
      LAYER M5 ;
        RECT  32.592 86.208 32.616 86.4 ;
    END
  END rd[113]
  PIN rd[114]
    DIRECTION OUTPUT ;
    USE SIGNAL ;
    PORT
      LAYER M3 ;
        RECT  32.688 86.256 32.706 86.4 ;
    END
  END rd[114]
  PIN rd[115]
    DIRECTION OUTPUT ;
    USE SIGNAL ;
    PORT
      LAYER M5 ;
        RECT  32.736 86.208 32.76 86.4 ;
    END
  END rd[115]
  PIN rd[116]
    DIRECTION OUTPUT ;
    USE SIGNAL ;
    PORT
      LAYER M3 ;
        RECT  32.832 86.256 32.85 86.4 ;
    END
  END rd[116]
  PIN rd[117]
    DIRECTION OUTPUT ;
    USE SIGNAL ;
    PORT
      LAYER M5 ;
        RECT  32.88 86.208 32.904 86.4 ;
    END
  END rd[117]
  PIN rd[118]
    DIRECTION OUTPUT ;
    USE SIGNAL ;
    PORT
      LAYER M3 ;
        RECT  32.976 86.256 32.994 86.4 ;
    END
  END rd[118]
  PIN rd[119]
    DIRECTION OUTPUT ;
    USE SIGNAL ;
    PORT
      LAYER M5 ;
        RECT  33.024 86.208 33.048 86.4 ;
    END
  END rd[119]
  PIN rd[11]
    DIRECTION OUTPUT ;
    USE SIGNAL ;
    PORT
      LAYER M5 ;
        RECT  25.248 86.208 25.272 86.4 ;
    END
  END rd[11]
  PIN rd[120]
    DIRECTION OUTPUT ;
    USE SIGNAL ;
    PORT
      LAYER M3 ;
        RECT  33.12 86.256 33.138 86.4 ;
    END
  END rd[120]
  PIN rd[121]
    DIRECTION OUTPUT ;
    USE SIGNAL ;
    PORT
      LAYER M5 ;
        RECT  33.168 86.208 33.192 86.4 ;
    END
  END rd[121]
  PIN rd[122]
    DIRECTION OUTPUT ;
    USE SIGNAL ;
    PORT
      LAYER M3 ;
        RECT  33.264 86.256 33.282 86.4 ;
    END
  END rd[122]
  PIN rd[123]
    DIRECTION OUTPUT ;
    USE SIGNAL ;
    PORT
      LAYER M5 ;
        RECT  33.312 86.208 33.336 86.4 ;
    END
  END rd[123]
  PIN rd[124]
    DIRECTION OUTPUT ;
    USE SIGNAL ;
    PORT
      LAYER M3 ;
        RECT  33.408 86.256 33.426 86.4 ;
    END
  END rd[124]
  PIN rd[125]
    DIRECTION OUTPUT ;
    USE SIGNAL ;
    PORT
      LAYER M5 ;
        RECT  33.456 86.208 33.48 86.4 ;
    END
  END rd[125]
  PIN rd[126]
    DIRECTION OUTPUT ;
    USE SIGNAL ;
    PORT
      LAYER M3 ;
        RECT  33.552 86.256 33.57 86.4 ;
    END
  END rd[126]
  PIN rd[127]
    DIRECTION OUTPUT ;
    USE SIGNAL ;
    PORT
      LAYER M5 ;
        RECT  33.6 86.208 33.624 86.4 ;
    END
  END rd[127]
  PIN rd[128]
    DIRECTION OUTPUT ;
    USE SIGNAL ;
    PORT
      LAYER M3 ;
        RECT  33.696 86.256 33.714 86.4 ;
    END
    PORT
      LAYER M3 ;
        RECT  33.66 86.268 33.786 86.333 ;
    END
  END rd[128]
  PIN rd[129]
    DIRECTION OUTPUT ;
    USE SIGNAL ;
    PORT
      LAYER M5 ;
        RECT  33.744 86.208 33.768 86.4 ;
    END
  END rd[129]
  PIN rd[12]
    DIRECTION OUTPUT ;
    USE SIGNAL ;
    PORT
      LAYER M3 ;
        RECT  25.344 86.256 25.362 86.4 ;
    END
  END rd[12]
  PIN rd[130]
    DIRECTION OUTPUT ;
    USE SIGNAL ;
    PORT
      LAYER M3 ;
        RECT  33.84 86.256 33.858 86.4 ;
    END
  END rd[130]
  PIN rd[131]
    DIRECTION OUTPUT ;
    USE SIGNAL ;
    PORT
      LAYER M5 ;
        RECT  33.888 86.208 33.912 86.4 ;
    END
  END rd[131]
  PIN rd[132]
    DIRECTION OUTPUT ;
    USE SIGNAL ;
    PORT
      LAYER M3 ;
        RECT  33.984 86.256 34.002 86.4 ;
    END
  END rd[132]
  PIN rd[133]
    DIRECTION OUTPUT ;
    USE SIGNAL ;
    PORT
      LAYER M5 ;
        RECT  34.032 86.208 34.056 86.4 ;
    END
  END rd[133]
  PIN rd[134]
    DIRECTION OUTPUT ;
    USE SIGNAL ;
    PORT
      LAYER M3 ;
        RECT  34.128 86.256 34.146 86.4 ;
    END
  END rd[134]
  PIN rd[135]
    DIRECTION OUTPUT ;
    USE SIGNAL ;
    PORT
      LAYER M5 ;
        RECT  34.176 86.208 34.2 86.4 ;
    END
  END rd[135]
  PIN rd[136]
    DIRECTION OUTPUT ;
    USE SIGNAL ;
    PORT
      LAYER M3 ;
        RECT  34.272 86.256 34.29 86.4 ;
    END
  END rd[136]
  PIN rd[137]
    DIRECTION OUTPUT ;
    USE SIGNAL ;
    PORT
      LAYER M5 ;
        RECT  34.32 86.208 34.344 86.4 ;
    END
  END rd[137]
  PIN rd[138]
    DIRECTION OUTPUT ;
    USE SIGNAL ;
    PORT
      LAYER M3 ;
        RECT  34.416 86.256 34.434 86.4 ;
    END
  END rd[138]
  PIN rd[139]
    DIRECTION OUTPUT ;
    USE SIGNAL ;
    PORT
      LAYER M5 ;
        RECT  34.464 86.208 34.488 86.4 ;
    END
  END rd[139]
  PIN rd[13]
    DIRECTION OUTPUT ;
    USE SIGNAL ;
    PORT
      LAYER M5 ;
        RECT  25.392 86.208 25.416 86.4 ;
    END
  END rd[13]
  PIN rd[140]
    DIRECTION OUTPUT ;
    USE SIGNAL ;
    PORT
      LAYER M3 ;
        RECT  34.56 86.256 34.578 86.4 ;
    END
  END rd[140]
  PIN rd[141]
    DIRECTION OUTPUT ;
    USE SIGNAL ;
    PORT
      LAYER M5 ;
        RECT  34.608 86.208 34.632 86.4 ;
    END
  END rd[141]
  PIN rd[142]
    DIRECTION OUTPUT ;
    USE SIGNAL ;
    PORT
      LAYER M3 ;
        RECT  34.704 86.256 34.722 86.4 ;
    END
  END rd[142]
  PIN rd[143]
    DIRECTION OUTPUT ;
    USE SIGNAL ;
    PORT
      LAYER M5 ;
        RECT  34.752 86.208 34.776 86.4 ;
    END
  END rd[143]
  PIN rd[144]
    DIRECTION OUTPUT ;
    USE SIGNAL ;
    PORT
      LAYER M3 ;
        RECT  34.848 86.256 34.866 86.4 ;
    END
  END rd[144]
  PIN rd[145]
    DIRECTION OUTPUT ;
    USE SIGNAL ;
    PORT
      LAYER M5 ;
        RECT  34.896 86.208 34.92 86.4 ;
    END
  END rd[145]
  PIN rd[146]
    DIRECTION OUTPUT ;
    USE SIGNAL ;
    PORT
      LAYER M3 ;
        RECT  34.992 86.256 35.01 86.4 ;
    END
  END rd[146]
  PIN rd[147]
    DIRECTION OUTPUT ;
    USE SIGNAL ;
    PORT
      LAYER M5 ;
        RECT  35.04 86.208 35.064 86.4 ;
    END
  END rd[147]
  PIN rd[148]
    DIRECTION OUTPUT ;
    USE SIGNAL ;
    PORT
      LAYER M3 ;
        RECT  35.136 86.256 35.154 86.4 ;
    END
  END rd[148]
  PIN rd[149]
    DIRECTION OUTPUT ;
    USE SIGNAL ;
    PORT
      LAYER M5 ;
        RECT  35.184 86.208 35.208 86.4 ;
    END
  END rd[149]
  PIN rd[14]
    DIRECTION OUTPUT ;
    USE SIGNAL ;
    PORT
      LAYER M3 ;
        RECT  25.488 86.256 25.506 86.4 ;
    END
  END rd[14]
  PIN rd[150]
    DIRECTION OUTPUT ;
    USE SIGNAL ;
    PORT
      LAYER M3 ;
        RECT  35.28 86.256 35.298 86.4 ;
    END
  END rd[150]
  PIN rd[151]
    DIRECTION OUTPUT ;
    USE SIGNAL ;
    PORT
      LAYER M5 ;
        RECT  35.328 86.208 35.352 86.4 ;
    END
  END rd[151]
  PIN rd[152]
    DIRECTION OUTPUT ;
    USE SIGNAL ;
    PORT
      LAYER M3 ;
        RECT  35.424 86.256 35.442 86.4 ;
    END
  END rd[152]
  PIN rd[153]
    DIRECTION OUTPUT ;
    USE SIGNAL ;
    PORT
      LAYER M5 ;
        RECT  35.472 86.208 35.496 86.4 ;
    END
  END rd[153]
  PIN rd[154]
    DIRECTION OUTPUT ;
    USE SIGNAL ;
    PORT
      LAYER M3 ;
        RECT  35.568 86.256 35.586 86.4 ;
    END
  END rd[154]
  PIN rd[155]
    DIRECTION OUTPUT ;
    USE SIGNAL ;
    PORT
      LAYER M5 ;
        RECT  35.616 86.208 35.64 86.4 ;
    END
  END rd[155]
  PIN rd[156]
    DIRECTION OUTPUT ;
    USE SIGNAL ;
    PORT
      LAYER M3 ;
        RECT  35.712 86.256 35.73 86.4 ;
    END
  END rd[156]
  PIN rd[157]
    DIRECTION OUTPUT ;
    USE SIGNAL ;
    PORT
      LAYER M5 ;
        RECT  35.76 86.208 35.784 86.4 ;
    END
  END rd[157]
  PIN rd[158]
    DIRECTION OUTPUT ;
    USE SIGNAL ;
    PORT
      LAYER M3 ;
        RECT  35.856 86.256 35.874 86.4 ;
    END
  END rd[158]
  PIN rd[159]
    DIRECTION OUTPUT ;
    USE SIGNAL ;
    PORT
      LAYER M5 ;
        RECT  35.904 86.208 35.928 86.4 ;
    END
  END rd[159]
  PIN rd[15]
    DIRECTION OUTPUT ;
    USE SIGNAL ;
    PORT
      LAYER M5 ;
        RECT  25.536 86.208 25.56 86.4 ;
    END
  END rd[15]
  PIN rd[160]
    DIRECTION OUTPUT ;
    USE SIGNAL ;
    PORT
      LAYER M3 ;
        RECT  36 86.256 36.018 86.4 ;
    END
  END rd[160]
  PIN rd[161]
    DIRECTION OUTPUT ;
    USE SIGNAL ;
    PORT
      LAYER M5 ;
        RECT  36.048 86.208 36.072 86.4 ;
    END
  END rd[161]
  PIN rd[162]
    DIRECTION OUTPUT ;
    USE SIGNAL ;
    PORT
      LAYER M3 ;
        RECT  36.144 86.256 36.162 86.4 ;
    END
  END rd[162]
  PIN rd[163]
    DIRECTION OUTPUT ;
    USE SIGNAL ;
    PORT
      LAYER M5 ;
        RECT  36.192 86.208 36.216 86.4 ;
    END
  END rd[163]
  PIN rd[164]
    DIRECTION OUTPUT ;
    USE SIGNAL ;
    PORT
      LAYER M3 ;
        RECT  36.288 86.256 36.306 86.4 ;
    END
  END rd[164]
  PIN rd[165]
    DIRECTION OUTPUT ;
    USE SIGNAL ;
    PORT
      LAYER M5 ;
        RECT  36.336 86.208 36.36 86.4 ;
    END
  END rd[165]
  PIN rd[166]
    DIRECTION OUTPUT ;
    USE SIGNAL ;
    PORT
      LAYER M3 ;
        RECT  36.432 86.256 36.45 86.4 ;
    END
  END rd[166]
  PIN rd[167]
    DIRECTION OUTPUT ;
    USE SIGNAL ;
    PORT
      LAYER M5 ;
        RECT  36.48 86.208 36.504 86.4 ;
    END
  END rd[167]
  PIN rd[168]
    DIRECTION OUTPUT ;
    USE SIGNAL ;
    PORT
      LAYER M3 ;
        RECT  36.576 86.256 36.594 86.4 ;
    END
  END rd[168]
  PIN rd[169]
    DIRECTION OUTPUT ;
    USE SIGNAL ;
    PORT
      LAYER M5 ;
        RECT  36.624 86.208 36.648 86.4 ;
    END
  END rd[169]
  PIN rd[16]
    DIRECTION OUTPUT ;
    USE SIGNAL ;
    PORT
      LAYER M3 ;
        RECT  25.632 86.256 25.65 86.4 ;
    END
  END rd[16]
  PIN rd[170]
    DIRECTION OUTPUT ;
    USE SIGNAL ;
    PORT
      LAYER M3 ;
        RECT  36.72 86.256 36.738 86.4 ;
    END
  END rd[170]
  PIN rd[171]
    DIRECTION OUTPUT ;
    USE SIGNAL ;
    PORT
      LAYER M5 ;
        RECT  36.768 86.208 36.792 86.4 ;
    END
  END rd[171]
  PIN rd[172]
    DIRECTION OUTPUT ;
    USE SIGNAL ;
    PORT
      LAYER M3 ;
        RECT  36.864 86.256 36.882 86.4 ;
    END
  END rd[172]
  PIN rd[173]
    DIRECTION OUTPUT ;
    USE SIGNAL ;
    PORT
      LAYER M5 ;
        RECT  36.912 86.208 36.936 86.4 ;
    END
  END rd[173]
  PIN rd[174]
    DIRECTION OUTPUT ;
    USE SIGNAL ;
    PORT
      LAYER M3 ;
        RECT  37.008 86.256 37.026 86.4 ;
    END
  END rd[174]
  PIN rd[175]
    DIRECTION OUTPUT ;
    USE SIGNAL ;
    PORT
      LAYER M5 ;
        RECT  37.056 86.208 37.08 86.4 ;
    END
  END rd[175]
  PIN rd[176]
    DIRECTION OUTPUT ;
    USE SIGNAL ;
    PORT
      LAYER M3 ;
        RECT  37.152 86.256 37.17 86.4 ;
    END
  END rd[176]
  PIN rd[177]
    DIRECTION OUTPUT ;
    USE SIGNAL ;
    PORT
      LAYER M5 ;
        RECT  37.2 86.208 37.224 86.4 ;
    END
  END rd[177]
  PIN rd[178]
    DIRECTION OUTPUT ;
    USE SIGNAL ;
    PORT
      LAYER M3 ;
        RECT  37.296 86.256 37.314 86.4 ;
    END
    PORT
      LAYER M3 ;
        RECT  37.26 86.268 37.386 86.333 ;
    END
  END rd[178]
  PIN rd[179]
    DIRECTION OUTPUT ;
    USE SIGNAL ;
    PORT
      LAYER M5 ;
        RECT  37.344 86.208 37.368 86.4 ;
    END
  END rd[179]
  PIN rd[17]
    DIRECTION OUTPUT ;
    USE SIGNAL ;
    PORT
      LAYER M5 ;
        RECT  25.68 86.208 25.704 86.4 ;
    END
  END rd[17]
  PIN rd[180]
    DIRECTION OUTPUT ;
    USE SIGNAL ;
    PORT
      LAYER M3 ;
        RECT  37.44 86.256 37.458 86.4 ;
    END
  END rd[180]
  PIN rd[181]
    DIRECTION OUTPUT ;
    USE SIGNAL ;
    PORT
      LAYER M5 ;
        RECT  37.488 86.208 37.512 86.4 ;
    END
  END rd[181]
  PIN rd[182]
    DIRECTION OUTPUT ;
    USE SIGNAL ;
    PORT
      LAYER M3 ;
        RECT  37.584 86.256 37.602 86.4 ;
    END
  END rd[182]
  PIN rd[183]
    DIRECTION OUTPUT ;
    USE SIGNAL ;
    PORT
      LAYER M5 ;
        RECT  37.632 86.208 37.656 86.4 ;
    END
  END rd[183]
  PIN rd[184]
    DIRECTION OUTPUT ;
    USE SIGNAL ;
    PORT
      LAYER M3 ;
        RECT  37.728 86.256 37.746 86.4 ;
    END
  END rd[184]
  PIN rd[185]
    DIRECTION OUTPUT ;
    USE SIGNAL ;
    PORT
      LAYER M5 ;
        RECT  37.776 86.208 37.8 86.4 ;
    END
  END rd[185]
  PIN rd[186]
    DIRECTION OUTPUT ;
    USE SIGNAL ;
    PORT
      LAYER M3 ;
        RECT  37.872 86.256 37.89 86.4 ;
    END
  END rd[186]
  PIN rd[187]
    DIRECTION OUTPUT ;
    USE SIGNAL ;
    PORT
      LAYER M5 ;
        RECT  37.92 86.208 37.944 86.4 ;
    END
  END rd[187]
  PIN rd[188]
    DIRECTION OUTPUT ;
    USE SIGNAL ;
    PORT
      LAYER M3 ;
        RECT  38.016 86.256 38.034 86.4 ;
    END
  END rd[188]
  PIN rd[189]
    DIRECTION OUTPUT ;
    USE SIGNAL ;
    PORT
      LAYER M5 ;
        RECT  38.064 86.208 38.088 86.4 ;
    END
  END rd[189]
  PIN rd[18]
    DIRECTION OUTPUT ;
    USE SIGNAL ;
    PORT
      LAYER M3 ;
        RECT  25.776 86.256 25.794 86.4 ;
    END
  END rd[18]
  PIN rd[190]
    DIRECTION OUTPUT ;
    USE SIGNAL ;
    PORT
      LAYER M3 ;
        RECT  38.16 86.256 38.178 86.4 ;
    END
  END rd[190]
  PIN rd[191]
    DIRECTION OUTPUT ;
    USE SIGNAL ;
    PORT
      LAYER M5 ;
        RECT  38.208 86.208 38.232 86.4 ;
    END
  END rd[191]
  PIN rd[192]
    DIRECTION OUTPUT ;
    USE SIGNAL ;
    PORT
      LAYER M3 ;
        RECT  38.304 86.256 38.322 86.4 ;
    END
  END rd[192]
  PIN rd[193]
    DIRECTION OUTPUT ;
    USE SIGNAL ;
    PORT
      LAYER M5 ;
        RECT  38.352 86.208 38.376 86.4 ;
    END
  END rd[193]
  PIN rd[194]
    DIRECTION OUTPUT ;
    USE SIGNAL ;
    PORT
      LAYER M3 ;
        RECT  38.448 86.256 38.466 86.4 ;
    END
  END rd[194]
  PIN rd[195]
    DIRECTION OUTPUT ;
    USE SIGNAL ;
    PORT
      LAYER M5 ;
        RECT  38.496 86.208 38.52 86.4 ;
    END
  END rd[195]
  PIN rd[196]
    DIRECTION OUTPUT ;
    USE SIGNAL ;
    PORT
      LAYER M3 ;
        RECT  38.592 86.256 38.61 86.4 ;
    END
  END rd[196]
  PIN rd[197]
    DIRECTION OUTPUT ;
    USE SIGNAL ;
    PORT
      LAYER M5 ;
        RECT  38.64 86.208 38.664 86.4 ;
    END
  END rd[197]
  PIN rd[198]
    DIRECTION OUTPUT ;
    USE SIGNAL ;
    PORT
      LAYER M3 ;
        RECT  38.736 86.256 38.754 86.4 ;
    END
  END rd[198]
  PIN rd[199]
    DIRECTION OUTPUT ;
    USE SIGNAL ;
    PORT
      LAYER M5 ;
        RECT  38.784 86.208 38.808 86.4 ;
    END
  END rd[199]
  PIN rd[19]
    DIRECTION OUTPUT ;
    USE SIGNAL ;
    PORT
      LAYER M5 ;
        RECT  25.824 86.208 25.848 86.4 ;
    END
  END rd[19]
  PIN rd[1]
    DIRECTION OUTPUT ;
    USE SIGNAL ;
    PORT
      LAYER M5 ;
        RECT  24.528 86.208 24.552 86.4 ;
    END
  END rd[1]
  PIN rd[200]
    DIRECTION OUTPUT ;
    USE SIGNAL ;
    PORT
      LAYER M3 ;
        RECT  38.88 86.256 38.898 86.4 ;
    END
  END rd[200]
  PIN rd[201]
    DIRECTION OUTPUT ;
    USE SIGNAL ;
    PORT
      LAYER M5 ;
        RECT  38.928 86.208 38.952 86.4 ;
    END
  END rd[201]
  PIN rd[202]
    DIRECTION OUTPUT ;
    USE SIGNAL ;
    PORT
      LAYER M3 ;
        RECT  39.024 86.256 39.042 86.4 ;
    END
  END rd[202]
  PIN rd[203]
    DIRECTION OUTPUT ;
    USE SIGNAL ;
    PORT
      LAYER M5 ;
        RECT  39.072 86.208 39.096 86.4 ;
    END
  END rd[203]
  PIN rd[204]
    DIRECTION OUTPUT ;
    USE SIGNAL ;
    PORT
      LAYER M3 ;
        RECT  39.168 86.256 39.186 86.4 ;
    END
  END rd[204]
  PIN rd[205]
    DIRECTION OUTPUT ;
    USE SIGNAL ;
    PORT
      LAYER M5 ;
        RECT  39.216 86.208 39.24 86.4 ;
    END
  END rd[205]
  PIN rd[206]
    DIRECTION OUTPUT ;
    USE SIGNAL ;
    PORT
      LAYER M3 ;
        RECT  39.312 86.256 39.33 86.4 ;
    END
  END rd[206]
  PIN rd[207]
    DIRECTION OUTPUT ;
    USE SIGNAL ;
    PORT
      LAYER M5 ;
        RECT  39.36 86.208 39.384 86.4 ;
    END
  END rd[207]
  PIN rd[208]
    DIRECTION OUTPUT ;
    USE SIGNAL ;
    PORT
      LAYER M3 ;
        RECT  39.456 86.256 39.474 86.4 ;
    END
  END rd[208]
  PIN rd[209]
    DIRECTION OUTPUT ;
    USE SIGNAL ;
    PORT
      LAYER M5 ;
        RECT  39.504 86.208 39.528 86.4 ;
    END
  END rd[209]
  PIN rd[20]
    DIRECTION OUTPUT ;
    USE SIGNAL ;
    PORT
      LAYER M3 ;
        RECT  25.92 86.256 25.938 86.4 ;
    END
  END rd[20]
  PIN rd[210]
    DIRECTION OUTPUT ;
    USE SIGNAL ;
    PORT
      LAYER M3 ;
        RECT  39.6 86.256 39.618 86.4 ;
    END
  END rd[210]
  PIN rd[211]
    DIRECTION OUTPUT ;
    USE SIGNAL ;
    PORT
      LAYER M5 ;
        RECT  39.648 86.208 39.672 86.4 ;
    END
  END rd[211]
  PIN rd[212]
    DIRECTION OUTPUT ;
    USE SIGNAL ;
    PORT
      LAYER M3 ;
        RECT  39.744 86.256 39.762 86.4 ;
    END
  END rd[212]
  PIN rd[213]
    DIRECTION OUTPUT ;
    USE SIGNAL ;
    PORT
      LAYER M5 ;
        RECT  39.792 86.208 39.816 86.4 ;
    END
  END rd[213]
  PIN rd[214]
    DIRECTION OUTPUT ;
    USE SIGNAL ;
    PORT
      LAYER M3 ;
        RECT  39.888 86.256 39.906 86.4 ;
    END
  END rd[214]
  PIN rd[215]
    DIRECTION OUTPUT ;
    USE SIGNAL ;
    PORT
      LAYER M5 ;
        RECT  39.936 86.208 39.96 86.4 ;
    END
  END rd[215]
  PIN rd[216]
    DIRECTION OUTPUT ;
    USE SIGNAL ;
    PORT
      LAYER M3 ;
        RECT  40.032 86.256 40.05 86.4 ;
    END
  END rd[216]
  PIN rd[217]
    DIRECTION OUTPUT ;
    USE SIGNAL ;
    PORT
      LAYER M5 ;
        RECT  40.08 86.208 40.104 86.4 ;
    END
  END rd[217]
  PIN rd[218]
    DIRECTION OUTPUT ;
    USE SIGNAL ;
    PORT
      LAYER M3 ;
        RECT  40.176 86.256 40.194 86.4 ;
    END
  END rd[218]
  PIN rd[219]
    DIRECTION OUTPUT ;
    USE SIGNAL ;
    PORT
      LAYER M5 ;
        RECT  40.224 86.208 40.248 86.4 ;
    END
  END rd[219]
  PIN rd[21]
    DIRECTION OUTPUT ;
    USE SIGNAL ;
    PORT
      LAYER M5 ;
        RECT  25.968 86.208 25.992 86.4 ;
    END
  END rd[21]
  PIN rd[220]
    DIRECTION OUTPUT ;
    USE SIGNAL ;
    PORT
      LAYER M3 ;
        RECT  40.32 86.256 40.338 86.4 ;
    END
  END rd[220]
  PIN rd[221]
    DIRECTION OUTPUT ;
    USE SIGNAL ;
    PORT
      LAYER M5 ;
        RECT  40.368 86.208 40.392 86.4 ;
    END
  END rd[221]
  PIN rd[222]
    DIRECTION OUTPUT ;
    USE SIGNAL ;
    PORT
      LAYER M3 ;
        RECT  40.464 86.256 40.482 86.4 ;
    END
  END rd[222]
  PIN rd[223]
    DIRECTION OUTPUT ;
    USE SIGNAL ;
    PORT
      LAYER M5 ;
        RECT  40.512 86.208 40.536 86.4 ;
    END
  END rd[223]
  PIN rd[224]
    DIRECTION OUTPUT ;
    USE SIGNAL ;
    PORT
      LAYER M3 ;
        RECT  40.608 86.256 40.626 86.4 ;
    END
  END rd[224]
  PIN rd[225]
    DIRECTION OUTPUT ;
    USE SIGNAL ;
    PORT
      LAYER M5 ;
        RECT  40.656 86.208 40.68 86.4 ;
    END
  END rd[225]
  PIN rd[226]
    DIRECTION OUTPUT ;
    USE SIGNAL ;
    PORT
      LAYER M3 ;
        RECT  40.752 86.256 40.77 86.4 ;
    END
  END rd[226]
  PIN rd[227]
    DIRECTION OUTPUT ;
    USE SIGNAL ;
    PORT
      LAYER M5 ;
        RECT  40.8 86.208 40.824 86.4 ;
    END
  END rd[227]
  PIN rd[228]
    DIRECTION OUTPUT ;
    USE SIGNAL ;
    PORT
      LAYER M3 ;
        RECT  40.896 86.256 40.914 86.4 ;
    END
  END rd[228]
  PIN rd[229]
    DIRECTION OUTPUT ;
    USE SIGNAL ;
    PORT
      LAYER M5 ;
        RECT  40.944 86.208 40.968 86.4 ;
    END
  END rd[229]
  PIN rd[22]
    DIRECTION OUTPUT ;
    USE SIGNAL ;
    PORT
      LAYER M3 ;
        RECT  26.064 86.256 26.082 86.4 ;
    END
  END rd[22]
  PIN rd[230]
    DIRECTION OUTPUT ;
    USE SIGNAL ;
    PORT
      LAYER M3 ;
        RECT  41.04 86.256 41.058 86.4 ;
    END
  END rd[230]
  PIN rd[231]
    DIRECTION OUTPUT ;
    USE SIGNAL ;
    PORT
      LAYER M5 ;
        RECT  41.088 86.208 41.112 86.4 ;
    END
  END rd[231]
  PIN rd[232]
    DIRECTION OUTPUT ;
    USE SIGNAL ;
    PORT
      LAYER M3 ;
        RECT  41.184 86.256 41.202 86.4 ;
    END
  END rd[232]
  PIN rd[233]
    DIRECTION OUTPUT ;
    USE SIGNAL ;
    PORT
      LAYER M5 ;
        RECT  41.232 86.208 41.256 86.4 ;
    END
  END rd[233]
  PIN rd[234]
    DIRECTION OUTPUT ;
    USE SIGNAL ;
    PORT
      LAYER M3 ;
        RECT  41.328 86.256 41.346 86.4 ;
    END
  END rd[234]
  PIN rd[235]
    DIRECTION OUTPUT ;
    USE SIGNAL ;
    PORT
      LAYER M5 ;
        RECT  41.376 86.208 41.4 86.4 ;
    END
  END rd[235]
  PIN rd[236]
    DIRECTION OUTPUT ;
    USE SIGNAL ;
    PORT
      LAYER M3 ;
        RECT  41.472 86.256 41.49 86.4 ;
    END
  END rd[236]
  PIN rd[237]
    DIRECTION OUTPUT ;
    USE SIGNAL ;
    PORT
      LAYER M5 ;
        RECT  41.52 86.208 41.544 86.4 ;
    END
  END rd[237]
  PIN rd[238]
    DIRECTION OUTPUT ;
    USE SIGNAL ;
    PORT
      LAYER M3 ;
        RECT  41.616 86.256 41.634 86.4 ;
    END
  END rd[238]
  PIN rd[239]
    DIRECTION OUTPUT ;
    USE SIGNAL ;
    PORT
      LAYER M5 ;
        RECT  41.664 86.208 41.688 86.4 ;
    END
  END rd[239]
  PIN rd[23]
    DIRECTION OUTPUT ;
    USE SIGNAL ;
    PORT
      LAYER M5 ;
        RECT  26.112 86.208 26.136 86.4 ;
    END
  END rd[23]
  PIN rd[240]
    DIRECTION OUTPUT ;
    USE SIGNAL ;
    PORT
      LAYER M3 ;
        RECT  41.76 86.256 41.778 86.4 ;
    END
  END rd[240]
  PIN rd[241]
    DIRECTION OUTPUT ;
    USE SIGNAL ;
    PORT
      LAYER M5 ;
        RECT  41.808 86.208 41.832 86.4 ;
    END
  END rd[241]
  PIN rd[242]
    DIRECTION OUTPUT ;
    USE SIGNAL ;
    PORT
      LAYER M3 ;
        RECT  41.904 86.256 41.922 86.4 ;
    END
  END rd[242]
  PIN rd[243]
    DIRECTION OUTPUT ;
    USE SIGNAL ;
    PORT
      LAYER M5 ;
        RECT  41.952 86.208 41.976 86.4 ;
    END
  END rd[243]
  PIN rd[244]
    DIRECTION OUTPUT ;
    USE SIGNAL ;
    PORT
      LAYER M3 ;
        RECT  42.048 86.256 42.066 86.4 ;
    END
  END rd[244]
  PIN rd[245]
    DIRECTION OUTPUT ;
    USE SIGNAL ;
    PORT
      LAYER M5 ;
        RECT  42.096 86.208 42.12 86.4 ;
    END
  END rd[245]
  PIN rd[246]
    DIRECTION OUTPUT ;
    USE SIGNAL ;
    PORT
      LAYER M3 ;
        RECT  42.192 86.256 42.21 86.4 ;
    END
  END rd[246]
  PIN rd[247]
    DIRECTION OUTPUT ;
    USE SIGNAL ;
    PORT
      LAYER M5 ;
        RECT  42.24 86.208 42.264 86.4 ;
    END
  END rd[247]
  PIN rd[248]
    DIRECTION OUTPUT ;
    USE SIGNAL ;
    PORT
      LAYER M3 ;
        RECT  42.336 86.256 42.354 86.4 ;
    END
  END rd[248]
  PIN rd[249]
    DIRECTION OUTPUT ;
    USE SIGNAL ;
    PORT
      LAYER M5 ;
        RECT  42.384 86.208 42.408 86.4 ;
    END
  END rd[249]
  PIN rd[24]
    DIRECTION OUTPUT ;
    USE SIGNAL ;
    PORT
      LAYER M3 ;
        RECT  26.208 86.256 26.226 86.4 ;
    END
  END rd[24]
  PIN rd[250]
    DIRECTION OUTPUT ;
    USE SIGNAL ;
    PORT
      LAYER M3 ;
        RECT  42.48 86.256 42.498 86.4 ;
    END
  END rd[250]
  PIN rd[251]
    DIRECTION OUTPUT ;
    USE SIGNAL ;
    PORT
      LAYER M5 ;
        RECT  42.528 86.208 42.552 86.4 ;
    END
  END rd[251]
  PIN rd[252]
    DIRECTION OUTPUT ;
    USE SIGNAL ;
    PORT
      LAYER M3 ;
        RECT  42.624 86.256 42.642 86.4 ;
    END
  END rd[252]
  PIN rd[253]
    DIRECTION OUTPUT ;
    USE SIGNAL ;
    PORT
      LAYER M5 ;
        RECT  42.672 86.208 42.696 86.4 ;
    END
  END rd[253]
  PIN rd[254]
    DIRECTION OUTPUT ;
    USE SIGNAL ;
    PORT
      LAYER M3 ;
        RECT  42.768 86.256 42.786 86.4 ;
    END
  END rd[254]
  PIN rd[255]
    DIRECTION OUTPUT ;
    USE SIGNAL ;
    PORT
      LAYER M5 ;
        RECT  42.816 86.208 42.84 86.4 ;
    END
  END rd[255]
  PIN rd[25]
    DIRECTION OUTPUT ;
    USE SIGNAL ;
    PORT
      LAYER M5 ;
        RECT  26.256 86.208 26.28 86.4 ;
    END
  END rd[25]
  PIN rd[26]
    DIRECTION OUTPUT ;
    USE SIGNAL ;
    PORT
      LAYER M3 ;
        RECT  26.352 86.256 26.37 86.4 ;
    END
  END rd[26]
  PIN rd[27]
    DIRECTION OUTPUT ;
    USE SIGNAL ;
    PORT
      LAYER M5 ;
        RECT  26.4 86.208 26.424 86.4 ;
    END
  END rd[27]
  PIN rd[28]
    DIRECTION OUTPUT ;
    USE SIGNAL ;
    PORT
      LAYER M3 ;
        RECT  26.496 86.256 26.514 86.4 ;
    END
  END rd[28]
  PIN rd[29]
    DIRECTION OUTPUT ;
    USE SIGNAL ;
    PORT
      LAYER M5 ;
        RECT  26.544 86.208 26.568 86.4 ;
    END
  END rd[29]
  PIN rd[2]
    DIRECTION OUTPUT ;
    USE SIGNAL ;
    PORT
      LAYER M3 ;
        RECT  24.624 86.256 24.642 86.4 ;
    END
  END rd[2]
  PIN rd[30]
    DIRECTION OUTPUT ;
    USE SIGNAL ;
    PORT
      LAYER M3 ;
        RECT  26.64 86.256 26.658 86.4 ;
    END
  END rd[30]
  PIN rd[31]
    DIRECTION OUTPUT ;
    USE SIGNAL ;
    PORT
      LAYER M5 ;
        RECT  26.688 86.208 26.712 86.4 ;
    END
  END rd[31]
  PIN rd[32]
    DIRECTION OUTPUT ;
    USE SIGNAL ;
    PORT
      LAYER M3 ;
        RECT  26.784 86.256 26.802 86.4 ;
    END
  END rd[32]
  PIN rd[33]
    DIRECTION OUTPUT ;
    USE SIGNAL ;
    PORT
      LAYER M5 ;
        RECT  26.832 86.208 26.856 86.4 ;
    END
  END rd[33]
  PIN rd[34]
    DIRECTION OUTPUT ;
    USE SIGNAL ;
    PORT
      LAYER M3 ;
        RECT  26.928 86.256 26.946 86.4 ;
    END
  END rd[34]
  PIN rd[35]
    DIRECTION OUTPUT ;
    USE SIGNAL ;
    PORT
      LAYER M5 ;
        RECT  26.976 86.208 27 86.4 ;
    END
  END rd[35]
  PIN rd[36]
    DIRECTION OUTPUT ;
    USE SIGNAL ;
    PORT
      LAYER M3 ;
        RECT  27.072 86.256 27.09 86.4 ;
    END
  END rd[36]
  PIN rd[37]
    DIRECTION OUTPUT ;
    USE SIGNAL ;
    PORT
      LAYER M5 ;
        RECT  27.12 86.208 27.144 86.4 ;
    END
  END rd[37]
  PIN rd[38]
    DIRECTION OUTPUT ;
    USE SIGNAL ;
    PORT
      LAYER M3 ;
        RECT  27.216 86.256 27.234 86.4 ;
    END
  END rd[38]
  PIN rd[39]
    DIRECTION OUTPUT ;
    USE SIGNAL ;
    PORT
      LAYER M5 ;
        RECT  27.264 86.208 27.288 86.4 ;
    END
  END rd[39]
  PIN rd[3]
    DIRECTION OUTPUT ;
    USE SIGNAL ;
    PORT
      LAYER M5 ;
        RECT  24.672 86.208 24.696 86.4 ;
    END
  END rd[3]
  PIN rd[40]
    DIRECTION OUTPUT ;
    USE SIGNAL ;
    PORT
      LAYER M3 ;
        RECT  27.36 86.256 27.378 86.4 ;
    END
  END rd[40]
  PIN rd[41]
    DIRECTION OUTPUT ;
    USE SIGNAL ;
    PORT
      LAYER M5 ;
        RECT  27.408 86.208 27.432 86.4 ;
    END
  END rd[41]
  PIN rd[42]
    DIRECTION OUTPUT ;
    USE SIGNAL ;
    PORT
      LAYER M3 ;
        RECT  27.504 86.256 27.522 86.4 ;
    END
    PORT
      LAYER M3 ;
        RECT  27.468 86.268 27.594 86.333 ;
    END
  END rd[42]
  PIN rd[43]
    DIRECTION OUTPUT ;
    USE SIGNAL ;
    PORT
      LAYER M5 ;
        RECT  27.552 86.208 27.576 86.4 ;
    END
  END rd[43]
  PIN rd[44]
    DIRECTION OUTPUT ;
    USE SIGNAL ;
    PORT
      LAYER M3 ;
        RECT  27.648 86.256 27.666 86.4 ;
    END
  END rd[44]
  PIN rd[45]
    DIRECTION OUTPUT ;
    USE SIGNAL ;
    PORT
      LAYER M5 ;
        RECT  27.696 86.208 27.72 86.4 ;
    END
  END rd[45]
  PIN rd[46]
    DIRECTION OUTPUT ;
    USE SIGNAL ;
    PORT
      LAYER M3 ;
        RECT  27.792 86.256 27.81 86.4 ;
    END
  END rd[46]
  PIN rd[47]
    DIRECTION OUTPUT ;
    USE SIGNAL ;
    PORT
      LAYER M5 ;
        RECT  27.84 86.208 27.864 86.4 ;
    END
  END rd[47]
  PIN rd[48]
    DIRECTION OUTPUT ;
    USE SIGNAL ;
    PORT
      LAYER M3 ;
        RECT  27.936 86.256 27.954 86.4 ;
    END
  END rd[48]
  PIN rd[49]
    DIRECTION OUTPUT ;
    USE SIGNAL ;
    PORT
      LAYER M5 ;
        RECT  27.984 86.208 28.008 86.4 ;
    END
  END rd[49]
  PIN rd[4]
    DIRECTION OUTPUT ;
    USE SIGNAL ;
    PORT
      LAYER M3 ;
        RECT  24.768 86.256 24.786 86.4 ;
    END
  END rd[4]
  PIN rd[50]
    DIRECTION OUTPUT ;
    USE SIGNAL ;
    PORT
      LAYER M3 ;
        RECT  28.08 86.256 28.098 86.4 ;
    END
  END rd[50]
  PIN rd[51]
    DIRECTION OUTPUT ;
    USE SIGNAL ;
    PORT
      LAYER M5 ;
        RECT  28.128 86.208 28.152 86.4 ;
    END
  END rd[51]
  PIN rd[52]
    DIRECTION OUTPUT ;
    USE SIGNAL ;
    PORT
      LAYER M3 ;
        RECT  28.224 86.256 28.242 86.4 ;
    END
  END rd[52]
  PIN rd[53]
    DIRECTION OUTPUT ;
    USE SIGNAL ;
    PORT
      LAYER M5 ;
        RECT  28.272 86.208 28.296 86.4 ;
    END
  END rd[53]
  PIN rd[54]
    DIRECTION OUTPUT ;
    USE SIGNAL ;
    PORT
      LAYER M3 ;
        RECT  28.368 86.256 28.386 86.4 ;
    END
  END rd[54]
  PIN rd[55]
    DIRECTION OUTPUT ;
    USE SIGNAL ;
    PORT
      LAYER M5 ;
        RECT  28.416 86.208 28.44 86.4 ;
    END
  END rd[55]
  PIN rd[56]
    DIRECTION OUTPUT ;
    USE SIGNAL ;
    PORT
      LAYER M3 ;
        RECT  28.512 86.256 28.53 86.4 ;
    END
  END rd[56]
  PIN rd[57]
    DIRECTION OUTPUT ;
    USE SIGNAL ;
    PORT
      LAYER M5 ;
        RECT  28.56 86.208 28.584 86.4 ;
    END
  END rd[57]
  PIN rd[58]
    DIRECTION OUTPUT ;
    USE SIGNAL ;
    PORT
      LAYER M3 ;
        RECT  28.656 86.256 28.674 86.4 ;
    END
  END rd[58]
  PIN rd[59]
    DIRECTION OUTPUT ;
    USE SIGNAL ;
    PORT
      LAYER M5 ;
        RECT  28.704 86.208 28.728 86.4 ;
    END
  END rd[59]
  PIN rd[5]
    DIRECTION OUTPUT ;
    USE SIGNAL ;
    PORT
      LAYER M5 ;
        RECT  24.816 86.208 24.84 86.4 ;
    END
  END rd[5]
  PIN rd[60]
    DIRECTION OUTPUT ;
    USE SIGNAL ;
    PORT
      LAYER M3 ;
        RECT  28.8 86.256 28.818 86.4 ;
    END
  END rd[60]
  PIN rd[61]
    DIRECTION OUTPUT ;
    USE SIGNAL ;
    PORT
      LAYER M5 ;
        RECT  28.848 86.208 28.872 86.4 ;
    END
  END rd[61]
  PIN rd[62]
    DIRECTION OUTPUT ;
    USE SIGNAL ;
    PORT
      LAYER M3 ;
        RECT  28.944 86.256 28.962 86.4 ;
    END
  END rd[62]
  PIN rd[63]
    DIRECTION OUTPUT ;
    USE SIGNAL ;
    PORT
      LAYER M5 ;
        RECT  28.992 86.208 29.016 86.4 ;
    END
  END rd[63]
  PIN rd[64]
    DIRECTION OUTPUT ;
    USE SIGNAL ;
    PORT
      LAYER M3 ;
        RECT  29.088 86.256 29.106 86.4 ;
    END
  END rd[64]
  PIN rd[65]
    DIRECTION OUTPUT ;
    USE SIGNAL ;
    PORT
      LAYER M5 ;
        RECT  29.136 86.208 29.16 86.4 ;
    END
  END rd[65]
  PIN rd[66]
    DIRECTION OUTPUT ;
    USE SIGNAL ;
    PORT
      LAYER M3 ;
        RECT  29.232 86.256 29.25 86.4 ;
    END
  END rd[66]
  PIN rd[67]
    DIRECTION OUTPUT ;
    USE SIGNAL ;
    PORT
      LAYER M5 ;
        RECT  29.28 86.208 29.304 86.4 ;
    END
  END rd[67]
  PIN rd[68]
    DIRECTION OUTPUT ;
    USE SIGNAL ;
    PORT
      LAYER M3 ;
        RECT  29.376 86.256 29.394 86.4 ;
    END
  END rd[68]
  PIN rd[69]
    DIRECTION OUTPUT ;
    USE SIGNAL ;
    PORT
      LAYER M5 ;
        RECT  29.424 86.208 29.448 86.4 ;
    END
  END rd[69]
  PIN rd[6]
    DIRECTION OUTPUT ;
    USE SIGNAL ;
    PORT
      LAYER M3 ;
        RECT  24.912 86.256 24.93 86.4 ;
    END
  END rd[6]
  PIN rd[70]
    DIRECTION OUTPUT ;
    USE SIGNAL ;
    PORT
      LAYER M3 ;
        RECT  29.52 86.256 29.538 86.4 ;
    END
  END rd[70]
  PIN rd[71]
    DIRECTION OUTPUT ;
    USE SIGNAL ;
    PORT
      LAYER M5 ;
        RECT  29.568 86.208 29.592 86.4 ;
    END
  END rd[71]
  PIN rd[72]
    DIRECTION OUTPUT ;
    USE SIGNAL ;
    PORT
      LAYER M3 ;
        RECT  29.664 86.256 29.682 86.4 ;
    END
  END rd[72]
  PIN rd[73]
    DIRECTION OUTPUT ;
    USE SIGNAL ;
    PORT
      LAYER M5 ;
        RECT  29.712 86.208 29.736 86.4 ;
    END
  END rd[73]
  PIN rd[74]
    DIRECTION OUTPUT ;
    USE SIGNAL ;
    PORT
      LAYER M3 ;
        RECT  29.808 86.256 29.826 86.4 ;
    END
  END rd[74]
  PIN rd[75]
    DIRECTION OUTPUT ;
    USE SIGNAL ;
    PORT
      LAYER M5 ;
        RECT  29.856 86.208 29.88 86.4 ;
    END
  END rd[75]
  PIN rd[76]
    DIRECTION OUTPUT ;
    USE SIGNAL ;
    PORT
      LAYER M3 ;
        RECT  29.952 86.256 29.97 86.4 ;
    END
  END rd[76]
  PIN rd[77]
    DIRECTION OUTPUT ;
    USE SIGNAL ;
    PORT
      LAYER M5 ;
        RECT  30 86.208 30.024 86.4 ;
    END
  END rd[77]
  PIN rd[78]
    DIRECTION OUTPUT ;
    USE SIGNAL ;
    PORT
      LAYER M3 ;
        RECT  30.096 86.256 30.114 86.4 ;
    END
  END rd[78]
  PIN rd[79]
    DIRECTION OUTPUT ;
    USE SIGNAL ;
    PORT
      LAYER M5 ;
        RECT  30.144 86.208 30.168 86.4 ;
    END
  END rd[79]
  PIN rd[7]
    DIRECTION OUTPUT ;
    USE SIGNAL ;
    PORT
      LAYER M5 ;
        RECT  24.96 86.208 24.984 86.4 ;
    END
  END rd[7]
  PIN rd[80]
    DIRECTION OUTPUT ;
    USE SIGNAL ;
    PORT
      LAYER M3 ;
        RECT  30.24 86.256 30.258 86.4 ;
    END
  END rd[80]
  PIN rd[81]
    DIRECTION OUTPUT ;
    USE SIGNAL ;
    PORT
      LAYER M5 ;
        RECT  30.288 86.208 30.312 86.4 ;
    END
  END rd[81]
  PIN rd[82]
    DIRECTION OUTPUT ;
    USE SIGNAL ;
    PORT
      LAYER M3 ;
        RECT  30.384 86.256 30.402 86.4 ;
    END
  END rd[82]
  PIN rd[83]
    DIRECTION OUTPUT ;
    USE SIGNAL ;
    PORT
      LAYER M5 ;
        RECT  30.432 86.208 30.456 86.4 ;
    END
  END rd[83]
  PIN rd[84]
    DIRECTION OUTPUT ;
    USE SIGNAL ;
    PORT
      LAYER M3 ;
        RECT  30.528 86.256 30.546 86.4 ;
    END
  END rd[84]
  PIN rd[85]
    DIRECTION OUTPUT ;
    USE SIGNAL ;
    PORT
      LAYER M5 ;
        RECT  30.576 86.208 30.6 86.4 ;
    END
  END rd[85]
  PIN rd[86]
    DIRECTION OUTPUT ;
    USE SIGNAL ;
    PORT
      LAYER M3 ;
        RECT  30.672 86.256 30.69 86.4 ;
    END
  END rd[86]
  PIN rd[87]
    DIRECTION OUTPUT ;
    USE SIGNAL ;
    PORT
      LAYER M5 ;
        RECT  30.72 86.208 30.744 86.4 ;
    END
  END rd[87]
  PIN rd[88]
    DIRECTION OUTPUT ;
    USE SIGNAL ;
    PORT
      LAYER M3 ;
        RECT  30.816 86.256 30.834 86.4 ;
    END
  END rd[88]
  PIN rd[89]
    DIRECTION OUTPUT ;
    USE SIGNAL ;
    PORT
      LAYER M5 ;
        RECT  30.864 86.208 30.888 86.4 ;
    END
  END rd[89]
  PIN rd[8]
    DIRECTION OUTPUT ;
    USE SIGNAL ;
    PORT
      LAYER M3 ;
        RECT  25.056 86.256 25.074 86.4 ;
    END
  END rd[8]
  PIN rd[90]
    DIRECTION OUTPUT ;
    USE SIGNAL ;
    PORT
      LAYER M3 ;
        RECT  30.96 86.256 30.978 86.4 ;
    END
  END rd[90]
  PIN rd[91]
    DIRECTION OUTPUT ;
    USE SIGNAL ;
    PORT
      LAYER M5 ;
        RECT  31.008 86.208 31.032 86.4 ;
    END
  END rd[91]
  PIN rd[92]
    DIRECTION OUTPUT ;
    USE SIGNAL ;
    PORT
      LAYER M3 ;
        RECT  31.104 86.256 31.122 86.4 ;
    END
  END rd[92]
  PIN rd[93]
    DIRECTION OUTPUT ;
    USE SIGNAL ;
    PORT
      LAYER M5 ;
        RECT  31.152 86.208 31.176 86.4 ;
    END
  END rd[93]
  PIN rd[94]
    DIRECTION OUTPUT ;
    USE SIGNAL ;
    PORT
      LAYER M3 ;
        RECT  31.248 86.256 31.266 86.4 ;
    END
    PORT
      LAYER M3 ;
        RECT  31.212 86.268 31.338 86.333 ;
    END
  END rd[94]
  PIN rd[95]
    DIRECTION OUTPUT ;
    USE SIGNAL ;
    PORT
      LAYER M5 ;
        RECT  31.296 86.208 31.32 86.4 ;
    END
  END rd[95]
  PIN rd[96]
    DIRECTION OUTPUT ;
    USE SIGNAL ;
    PORT
      LAYER M3 ;
        RECT  31.392 86.256 31.41 86.4 ;
    END
  END rd[96]
  PIN rd[97]
    DIRECTION OUTPUT ;
    USE SIGNAL ;
    PORT
      LAYER M5 ;
        RECT  31.44 86.208 31.464 86.4 ;
    END
  END rd[97]
  PIN rd[98]
    DIRECTION OUTPUT ;
    USE SIGNAL ;
    PORT
      LAYER M3 ;
        RECT  31.536 86.256 31.554 86.4 ;
    END
  END rd[98]
  PIN rd[99]
    DIRECTION OUTPUT ;
    USE SIGNAL ;
    PORT
      LAYER M5 ;
        RECT  31.584 86.208 31.608 86.4 ;
    END
  END rd[99]
  PIN rd[9]
    DIRECTION OUTPUT ;
    USE SIGNAL ;
    PORT
      LAYER M5 ;
        RECT  25.104 86.208 25.128 86.4 ;
    END
  END rd[9]
  PIN rq0
    DIRECTION INPUT ;
    USE SIGNAL ;
    PORT
      LAYER M4 ;
        RECT  0 38.736 0.192 38.76 ;
    END
  END rq0
  PIN rq1
    DIRECTION INPUT ;
    USE SIGNAL ;
    PORT
      LAYER M4 ;
        RECT  0 38.592 0.192 38.616 ;
    END
  END rq1
  PIN rst_n
    DIRECTION INPUT ;
    USE SIGNAL ;
    PORT
      LAYER M4 ;
        RECT  0 51.024 0.192 51.048 ;
    END
    PORT
      LAYER M4 ;
        RECT  0.156 51.024 0.181 51.048 ;
    END
    PORT
      LAYER M4 ;
        RECT  0.181 50.592 0.227 51.048 ;
    END
  END rst_n
  PIN w0[0]
    DIRECTION INPUT ;
    USE SIGNAL ;
    PORT
      LAYER M4 ;
        RECT  0 38.88 0.192 38.904 ;
    END
  END w0[0]
  PIN w0[1]
    DIRECTION INPUT ;
    USE SIGNAL ;
    PORT
      LAYER M4 ;
        RECT  0 39.024 0.192 39.048 ;
    END
  END w0[1]
  PIN w0[2]
    DIRECTION INPUT ;
    USE SIGNAL ;
    PORT
      LAYER M4 ;
        RECT  0 39.168 0.192 39.192 ;
    END
  END w0[2]
  PIN w0[3]
    DIRECTION INPUT ;
    USE SIGNAL ;
    PORT
      LAYER M4 ;
        RECT  0 39.312 0.192 39.336 ;
    END
  END w0[3]
  PIN w0[4]
    DIRECTION INPUT ;
    USE SIGNAL ;
    PORT
      LAYER M4 ;
        RECT  0 39.456 0.192 39.48 ;
    END
  END w0[4]
  PIN w0[5]
    DIRECTION INPUT ;
    USE SIGNAL ;
    PORT
      LAYER M4 ;
        RECT  0 39.6 0.192 39.624 ;
    END
  END w0[5]
  PIN w0[6]
    DIRECTION INPUT ;
    USE SIGNAL ;
    PORT
      LAYER M4 ;
        RECT  0 39.744 0.192 39.768 ;
    END
  END w0[6]
  PIN w0[7]
    DIRECTION INPUT ;
    USE SIGNAL ;
    PORT
      LAYER M4 ;
        RECT  0 39.888 0.192 39.912 ;
    END
  END w0[7]
  PIN w0[8]
    DIRECTION INPUT ;
    USE SIGNAL ;
    PORT
      LAYER M4 ;
        RECT  0 40.032 0.192 40.056 ;
    END
  END w0[8]
  PIN w1[0]
    DIRECTION INPUT ;
    USE SIGNAL ;
    PORT
      LAYER M4 ;
        RECT  0 40.176 0.192 40.2 ;
    END
  END w1[0]
  PIN w1[1]
    DIRECTION INPUT ;
    USE SIGNAL ;
    PORT
      LAYER M4 ;
        RECT  0 40.32 0.192 40.344 ;
    END
  END w1[1]
  PIN w1[2]
    DIRECTION INPUT ;
    USE SIGNAL ;
    PORT
      LAYER M4 ;
        RECT  0 40.464 0.192 40.488 ;
    END
  END w1[2]
  PIN w1[3]
    DIRECTION INPUT ;
    USE SIGNAL ;
    PORT
      LAYER M4 ;
        RECT  0 40.608 0.192 40.632 ;
    END
  END w1[3]
  PIN w1[4]
    DIRECTION INPUT ;
    USE SIGNAL ;
    PORT
      LAYER M4 ;
        RECT  0 40.752 0.192 40.776 ;
    END
  END w1[4]
  PIN w1[5]
    DIRECTION INPUT ;
    USE SIGNAL ;
    PORT
      LAYER M4 ;
        RECT  0 40.896 0.192 40.92 ;
    END
  END w1[5]
  PIN w1[6]
    DIRECTION INPUT ;
    USE SIGNAL ;
    PORT
      LAYER M4 ;
        RECT  0 41.04 0.192 41.064 ;
    END
  END w1[6]
  PIN w1[7]
    DIRECTION INPUT ;
    USE SIGNAL ;
    PORT
      LAYER M4 ;
        RECT  0 41.184 0.192 41.208 ;
    END
  END w1[7]
  PIN w1[8]
    DIRECTION INPUT ;
    USE SIGNAL ;
    PORT
      LAYER M4 ;
        RECT  0 41.328 0.192 41.352 ;
    END
  END w1[8]
  PIN wv
    DIRECTION INPUT ;
    USE SIGNAL ;
    PORT
      LAYER M4 ;
        RECT  0 41.472 0.192 41.496 ;
    END
  END wv
  PIN VDD
    DIRECTION INOUT ;
    USE POWER ;
    PORT
      LAYER M5 ;
        RECT  137.592 2.151 137.712 84.249 ;
        RECT  132.192 2.151 132.312 84.249 ;
        RECT  126.792 2.151 126.912 84.249 ;
        RECT  121.392 2.151 121.512 84.249 ;
        RECT  115.992 2.151 116.112 84.249 ;
        RECT  110.592 2.151 110.712 84.249 ;
        RECT  105.192 2.151 105.312 84.249 ;
        RECT  99.792 2.151 99.912 84.249 ;
        RECT  94.392 2.151 94.512 84.249 ;
        RECT  88.992 2.151 89.112 84.249 ;
        RECT  83.592 2.151 83.712 84.249 ;
        RECT  78.192 2.151 78.312 84.249 ;
        RECT  72.792 2.151 72.912 84.249 ;
        RECT  67.392 2.151 67.512 84.249 ;
        RECT  61.992 2.151 62.112 84.249 ;
        RECT  56.592 2.151 56.712 84.249 ;
        RECT  51.192 2.151 51.312 84.249 ;
        RECT  45.792 2.151 45.912 84.249 ;
        RECT  40.392 2.151 40.512 84.249 ;
        RECT  34.992 2.151 35.112 84.249 ;
        RECT  29.592 2.151 29.712 84.249 ;
        RECT  24.192 2.151 24.312 84.249 ;
        RECT  18.792 2.151 18.912 84.249 ;
        RECT  13.392 2.151 13.512 84.249 ;
        RECT  7.992 2.151 8.112 84.249 ;
        RECT  2.592 2.151 2.712 84.249 ;
    END
  END VDD
  PIN VSS
    DIRECTION INOUT ;
    USE GROUND ;
    PORT
      LAYER M5 ;
        RECT  137.4 2.137 137.52 84.263 ;
        RECT  132 2.137 132.12 84.263 ;
        RECT  126.6 2.137 126.72 84.263 ;
        RECT  121.2 2.137 121.32 84.263 ;
        RECT  115.8 2.137 115.92 84.263 ;
        RECT  110.4 2.137 110.52 84.263 ;
        RECT  105 2.137 105.12 84.263 ;
        RECT  99.6 2.137 99.72 84.263 ;
        RECT  94.2 2.137 94.32 84.263 ;
        RECT  88.8 2.137 88.92 84.263 ;
        RECT  83.4 2.137 83.52 84.263 ;
        RECT  78 2.137 78.12 84.263 ;
        RECT  72.6 2.137 72.72 84.263 ;
        RECT  67.2 2.137 67.32 84.263 ;
        RECT  61.8 2.137 61.92 84.263 ;
        RECT  56.4 2.137 56.52 84.263 ;
        RECT  51 2.137 51.12 84.263 ;
        RECT  45.6 2.137 45.72 84.263 ;
        RECT  40.2 2.137 40.32 84.263 ;
        RECT  34.8 2.137 34.92 84.263 ;
        RECT  29.4 2.137 29.52 84.263 ;
        RECT  24 2.137 24.12 84.263 ;
        RECT  18.6 2.137 18.72 84.263 ;
        RECT  13.2 2.137 13.32 84.263 ;
        RECT  7.8 2.137 7.92 84.263 ;
        RECT  2.4 2.137 2.52 84.263 ;
    END
  END VSS
  # OT_OBS_CLOSED layer=M5 d_um=1.536 added=452
  OBS
    LAYER RVTN ;
     RECT  2.16 2.16 140.4 2.295 ;
     RECT  2.16 2.565 140.4 2.835 ;
     RECT  2.16 3.105 140.4 3.375 ;
     RECT  2.16 3.645 140.4 3.915 ;
     RECT  2.16 4.185 140.4 4.455 ;
     RECT  2.16 4.725 140.4 4.995 ;
     RECT  2.16 5.265 140.4 5.535 ;
     RECT  2.16 5.805 140.4 6.075 ;
     RECT  2.16 6.345 140.4 6.615 ;
     RECT  2.16 6.885 140.4 7.155 ;
     RECT  2.16 7.425 140.4 7.695 ;
     RECT  2.16 7.965 140.4 8.235 ;
     RECT  2.16 8.505 140.4 8.775 ;
     RECT  2.16 9.045 140.4 9.315 ;
     RECT  2.16 9.585 140.4 9.855 ;
     RECT  2.16 10.125 140.4 10.395 ;
     RECT  2.16 10.665 140.4 10.935 ;
     RECT  2.16 11.205 140.4 11.475 ;
     RECT  2.16 11.745 140.4 12.015 ;
     RECT  2.16 12.285 140.4 12.555 ;
     RECT  2.16 12.825 140.4 13.095 ;
     RECT  2.16 13.365 140.4 13.635 ;
     RECT  2.16 13.905 140.4 14.175 ;
     RECT  2.16 14.445 140.4 14.715 ;
     RECT  2.16 14.985 140.4 15.255 ;
     RECT  2.16 15.525 140.4 15.795 ;
     RECT  2.16 16.065 140.4 16.335 ;
     RECT  2.16 16.605 140.4 16.875 ;
     RECT  2.16 17.145 140.4 17.415 ;
     RECT  2.16 17.685 140.4 17.955 ;
     RECT  2.16 18.225 140.4 18.495 ;
     RECT  2.16 18.765 140.4 19.035 ;
     RECT  2.16 19.305 140.4 19.575 ;
     RECT  2.16 19.845 140.4 20.115 ;
     RECT  2.16 20.385 20.412 20.655 ;
     RECT  119.34 20.385 140.4 20.655 ;
     RECT  2.16 20.925 20.412 21.195 ;
     RECT  119.34 20.925 140.4 21.195 ;
     RECT  2.16 21.465 20.412 21.735 ;
     RECT  119.34 21.465 140.4 21.735 ;
     RECT  2.16 22.005 20.412 22.275 ;
     RECT  119.34 22.005 140.4 22.275 ;
     RECT  2.16 22.545 20.412 22.815 ;
     RECT  119.34 22.545 140.4 22.815 ;
     RECT  2.16 23.085 20.412 23.355 ;
     RECT  119.34 23.085 140.4 23.355 ;
     RECT  2.16 23.625 20.412 23.895 ;
     RECT  119.34 23.625 140.4 23.895 ;
     RECT  2.16 24.165 20.412 24.435 ;
     RECT  119.34 24.165 140.4 24.435 ;
     RECT  2.16 24.705 20.412 24.975 ;
     RECT  119.34 24.705 140.4 24.975 ;
     RECT  2.16 25.245 20.412 25.515 ;
     RECT  119.34 25.245 140.4 25.515 ;
     RECT  2.16 25.785 20.412 26.055 ;
     RECT  119.34 25.785 140.4 26.055 ;
     RECT  2.16 26.325 20.412 26.595 ;
     RECT  119.34 26.325 140.4 26.595 ;
     RECT  2.16 26.865 20.412 27.135 ;
     RECT  119.34 26.865 140.4 27.135 ;
     RECT  2.16 27.405 20.412 27.675 ;
     RECT  119.34 27.405 140.4 27.675 ;
     RECT  2.16 27.945 20.412 28.215 ;
     RECT  119.34 27.945 140.4 28.215 ;
     RECT  2.16 28.485 20.412 28.755 ;
     RECT  119.34 28.485 140.4 28.755 ;
     RECT  2.16 29.025 20.412 29.295 ;
     RECT  119.34 29.025 140.4 29.295 ;
     RECT  2.16 29.565 20.412 29.835 ;
     RECT  119.34 29.565 140.4 29.835 ;
     RECT  2.16 30.105 20.412 30.375 ;
     RECT  119.34 30.105 140.4 30.375 ;
     RECT  2.16 30.645 20.412 30.915 ;
     RECT  119.34 30.645 140.4 30.915 ;
     RECT  2.16 31.185 20.412 31.455 ;
     RECT  119.34 31.185 140.4 31.455 ;
     RECT  2.16 31.725 20.412 31.995 ;
     RECT  119.34 31.725 140.4 31.995 ;
     RECT  2.16 32.265 20.412 32.535 ;
     RECT  119.34 32.265 140.4 32.535 ;
     RECT  2.16 32.805 20.412 33.075 ;
     RECT  119.34 32.805 140.4 33.075 ;
     RECT  2.16 33.345 20.412 33.615 ;
     RECT  119.34 33.345 140.4 33.615 ;
     RECT  2.16 33.885 20.412 34.155 ;
     RECT  119.34 33.885 140.4 34.155 ;
     RECT  2.16 34.425 20.412 34.695 ;
     RECT  119.34 34.425 140.4 34.695 ;
     RECT  2.16 34.965 20.412 35.235 ;
     RECT  119.34 34.965 140.4 35.235 ;
     RECT  2.16 35.505 20.412 35.775 ;
     RECT  119.34 35.505 140.4 35.775 ;
     RECT  2.16 36.045 20.412 36.315 ;
     RECT  119.34 36.045 140.4 36.315 ;
     RECT  2.16 36.585 20.412 36.855 ;
     RECT  119.34 36.585 140.4 36.855 ;
     RECT  2.16 37.125 20.412 37.395 ;
     RECT  119.34 37.125 140.4 37.395 ;
     RECT  2.16 37.665 20.412 37.935 ;
     RECT  119.34 37.665 140.4 37.935 ;
     RECT  2.16 38.205 20.412 38.475 ;
     RECT  119.34 38.205 140.4 38.475 ;
     RECT  2.16 38.745 20.412 39.015 ;
     RECT  119.34 38.745 140.4 39.015 ;
     RECT  2.16 39.285 20.412 39.555 ;
     RECT  119.34 39.285 140.4 39.555 ;
     RECT  2.16 39.825 20.412 40.095 ;
     RECT  119.34 39.825 140.4 40.095 ;
     RECT  2.16 40.365 20.412 40.635 ;
     RECT  119.34 40.365 140.4 40.635 ;
     RECT  2.16 40.905 20.412 41.175 ;
     RECT  119.34 40.905 140.4 41.175 ;
     RECT  2.16 41.445 20.412 41.715 ;
     RECT  119.34 41.445 140.4 41.715 ;
     RECT  2.16 41.985 20.412 42.255 ;
     RECT  119.34 41.985 140.4 42.255 ;
     RECT  2.16 42.525 20.412 42.795 ;
     RECT  119.34 42.525 140.4 42.795 ;
     RECT  2.16 43.065 20.412 43.335 ;
     RECT  119.34 43.065 140.4 43.335 ;
     RECT  2.16 43.605 20.412 43.875 ;
     RECT  119.34 43.605 140.4 43.875 ;
     RECT  2.16 44.145 20.412 44.415 ;
     RECT  119.34 44.145 140.4 44.415 ;
     RECT  2.16 44.685 20.412 44.955 ;
     RECT  119.34 44.685 140.4 44.955 ;
     RECT  2.16 45.225 20.412 45.495 ;
     RECT  119.34 45.225 140.4 45.495 ;
     RECT  2.16 45.765 20.412 46.035 ;
     RECT  119.34 45.765 140.4 46.035 ;
     RECT  2.16 46.305 20.412 46.575 ;
     RECT  119.34 46.305 140.4 46.575 ;
     RECT  2.16 46.845 20.412 47.115 ;
     RECT  119.34 46.845 140.4 47.115 ;
     RECT  2.16 47.385 20.412 47.655 ;
     RECT  119.34 47.385 140.4 47.655 ;
     RECT  2.16 47.925 20.412 48.195 ;
     RECT  119.34 47.925 140.4 48.195 ;
     RECT  2.16 48.465 20.412 48.735 ;
     RECT  119.34 48.465 140.4 48.735 ;
     RECT  2.16 49.005 20.412 49.275 ;
     RECT  119.34 49.005 140.4 49.275 ;
     RECT  2.16 49.545 20.412 49.815 ;
     RECT  119.34 49.545 140.4 49.815 ;
     RECT  2.16 50.085 20.412 50.355 ;
     RECT  119.34 50.085 140.4 50.355 ;
     RECT  2.16 50.625 20.412 50.895 ;
     RECT  119.34 50.625 140.4 50.895 ;
     RECT  2.16 51.165 20.412 51.435 ;
     RECT  119.34 51.165 140.4 51.435 ;
     RECT  2.16 51.705 20.412 51.975 ;
     RECT  119.34 51.705 140.4 51.975 ;
     RECT  2.16 52.245 20.412 52.515 ;
     RECT  119.34 52.245 140.4 52.515 ;
     RECT  2.16 52.785 20.412 53.055 ;
     RECT  119.34 52.785 140.4 53.055 ;
     RECT  2.16 53.325 20.412 53.595 ;
     RECT  119.34 53.325 140.4 53.595 ;
     RECT  2.16 53.865 20.412 54.135 ;
     RECT  119.34 53.865 140.4 54.135 ;
     RECT  2.16 54.405 20.412 54.675 ;
     RECT  119.34 54.405 140.4 54.675 ;
     RECT  2.16 54.945 20.412 55.215 ;
     RECT  119.34 54.945 140.4 55.215 ;
     RECT  2.16 55.485 20.412 55.755 ;
     RECT  119.34 55.485 140.4 55.755 ;
     RECT  2.16 56.025 20.412 56.295 ;
     RECT  119.34 56.025 140.4 56.295 ;
     RECT  2.16 56.565 20.412 56.835 ;
     RECT  119.34 56.565 140.4 56.835 ;
     RECT  2.16 57.105 20.412 57.375 ;
     RECT  119.34 57.105 140.4 57.375 ;
     RECT  2.16 57.645 20.412 57.915 ;
     RECT  119.34 57.645 140.4 57.915 ;
     RECT  2.16 58.185 20.412 58.455 ;
     RECT  119.34 58.185 140.4 58.455 ;
     RECT  2.16 58.725 20.412 58.995 ;
     RECT  119.34 58.725 140.4 58.995 ;
     RECT  2.16 59.265 20.412 59.535 ;
     RECT  119.34 59.265 140.4 59.535 ;
     RECT  2.16 59.805 20.412 60.075 ;
     RECT  119.34 59.805 140.4 60.075 ;
     RECT  2.16 60.345 20.412 60.615 ;
     RECT  119.34 60.345 140.4 60.615 ;
     RECT  2.16 60.885 20.412 61.155 ;
     RECT  119.34 60.885 140.4 61.155 ;
     RECT  2.16 61.425 20.412 61.695 ;
     RECT  119.34 61.425 140.4 61.695 ;
     RECT  2.16 61.965 20.412 62.235 ;
     RECT  119.34 61.965 140.4 62.235 ;
     RECT  2.16 62.505 20.412 62.775 ;
     RECT  119.34 62.505 140.4 62.775 ;
     RECT  2.16 63.045 20.412 63.315 ;
     RECT  119.34 63.045 140.4 63.315 ;
     RECT  2.16 63.585 20.412 63.855 ;
     RECT  119.34 63.585 140.4 63.855 ;
     RECT  2.16 64.125 20.412 64.395 ;
     RECT  119.34 64.125 140.4 64.395 ;
     RECT  2.16 64.665 20.412 64.935 ;
     RECT  119.34 64.665 140.4 64.935 ;
     RECT  2.16 65.205 20.412 65.475 ;
     RECT  119.34 65.205 140.4 65.475 ;
     RECT  2.16 65.745 140.4 66.015 ;
     RECT  2.16 66.285 140.4 66.555 ;
     RECT  2.16 66.825 140.4 67.095 ;
     RECT  2.16 67.365 140.4 67.635 ;
     RECT  2.16 67.905 140.4 68.175 ;
     RECT  2.16 68.445 140.4 68.715 ;
     RECT  2.16 68.985 140.4 69.255 ;
     RECT  2.16 69.525 140.4 69.795 ;
     RECT  2.16 70.065 140.4 70.335 ;
     RECT  2.16 70.605 140.4 70.875 ;
     RECT  2.16 71.145 140.4 71.415 ;
     RECT  2.16 71.685 140.4 71.955 ;
     RECT  2.16 72.225 140.4 72.495 ;
     RECT  2.16 72.765 140.4 73.035 ;
     RECT  2.16 73.305 140.4 73.575 ;
     RECT  2.16 73.845 140.4 74.115 ;
     RECT  2.16 74.385 140.4 74.655 ;
     RECT  2.16 74.925 140.4 75.195 ;
     RECT  2.16 75.465 140.4 75.735 ;
     RECT  2.16 76.005 140.4 76.275 ;
     RECT  2.16 76.545 140.4 76.815 ;
     RECT  2.16 77.085 140.4 77.355 ;
     RECT  2.16 77.625 140.4 77.895 ;
     RECT  2.16 78.165 140.4 78.435 ;
     RECT  2.16 78.705 140.4 78.975 ;
     RECT  2.16 79.245 140.4 79.515 ;
     RECT  2.16 79.785 140.4 80.055 ;
     RECT  2.16 80.325 140.4 80.595 ;
     RECT  2.16 80.865 140.4 81.135 ;
     RECT  2.16 81.405 140.4 81.675 ;
     RECT  2.16 81.945 140.4 82.215 ;
     RECT  2.16 82.485 140.4 82.755 ;
     RECT  2.16 83.025 140.4 83.295 ;
     RECT  2.16 83.565 140.4 83.835 ;
     RECT  2.16 84.105 140.4 84.24 ;
    LAYER RVTP ;
     RECT  2.16 2.295 140.4 2.565 ;
     RECT  2.16 2.835 140.4 3.105 ;
     RECT  2.16 3.375 140.4 3.645 ;
     RECT  2.16 3.915 140.4 4.185 ;
     RECT  2.16 4.455 140.4 4.725 ;
     RECT  2.16 4.995 140.4 5.265 ;
     RECT  2.16 5.535 140.4 5.805 ;
     RECT  2.16 6.075 140.4 6.345 ;
     RECT  2.16 6.615 140.4 6.885 ;
     RECT  2.16 7.155 140.4 7.425 ;
     RECT  2.16 7.695 140.4 7.965 ;
     RECT  2.16 8.235 140.4 8.505 ;
     RECT  2.16 8.775 140.4 9.045 ;
     RECT  2.16 9.315 140.4 9.585 ;
     RECT  2.16 9.855 140.4 10.125 ;
     RECT  2.16 10.395 140.4 10.665 ;
     RECT  2.16 10.935 140.4 11.205 ;
     RECT  2.16 11.475 140.4 11.745 ;
     RECT  2.16 12.015 140.4 12.285 ;
     RECT  2.16 12.555 140.4 12.825 ;
     RECT  2.16 13.095 140.4 13.365 ;
     RECT  2.16 13.635 140.4 13.905 ;
     RECT  2.16 14.175 140.4 14.445 ;
     RECT  2.16 14.715 140.4 14.985 ;
     RECT  2.16 15.255 140.4 15.525 ;
     RECT  2.16 15.795 140.4 16.065 ;
     RECT  2.16 16.335 140.4 16.605 ;
     RECT  2.16 16.875 140.4 17.145 ;
     RECT  2.16 17.415 140.4 17.685 ;
     RECT  2.16 17.955 140.4 18.225 ;
     RECT  2.16 18.495 140.4 18.765 ;
     RECT  2.16 19.035 140.4 19.305 ;
     RECT  2.16 19.575 140.4 19.845 ;
     RECT  2.16 20.115 140.4 20.25 ;
     RECT  2.16 20.25 20.412 20.385 ;
     RECT  119.34 20.25 140.4 20.385 ;
     RECT  2.16 20.655 20.412 20.925 ;
     RECT  119.34 20.655 140.4 20.925 ;
     RECT  2.16 21.195 20.412 21.465 ;
     RECT  119.34 21.195 140.4 21.465 ;
     RECT  2.16 21.735 20.412 22.005 ;
     RECT  119.34 21.735 140.4 22.005 ;
     RECT  2.16 22.275 20.412 22.545 ;
     RECT  119.34 22.275 140.4 22.545 ;
     RECT  2.16 22.815 20.412 23.085 ;
     RECT  119.34 22.815 140.4 23.085 ;
     RECT  2.16 23.355 20.412 23.625 ;
     RECT  119.34 23.355 140.4 23.625 ;
     RECT  2.16 23.895 20.412 24.165 ;
     RECT  119.34 23.895 140.4 24.165 ;
     RECT  2.16 24.435 20.412 24.705 ;
     RECT  119.34 24.435 140.4 24.705 ;
     RECT  2.16 24.975 20.412 25.245 ;
     RECT  119.34 24.975 140.4 25.245 ;
     RECT  2.16 25.515 20.412 25.785 ;
     RECT  119.34 25.515 140.4 25.785 ;
     RECT  2.16 26.055 20.412 26.325 ;
     RECT  119.34 26.055 140.4 26.325 ;
     RECT  2.16 26.595 20.412 26.865 ;
     RECT  119.34 26.595 140.4 26.865 ;
     RECT  2.16 27.135 20.412 27.405 ;
     RECT  119.34 27.135 140.4 27.405 ;
     RECT  2.16 27.675 20.412 27.945 ;
     RECT  119.34 27.675 140.4 27.945 ;
     RECT  2.16 28.215 20.412 28.485 ;
     RECT  119.34 28.215 140.4 28.485 ;
     RECT  2.16 28.755 20.412 29.025 ;
     RECT  119.34 28.755 140.4 29.025 ;
     RECT  2.16 29.295 20.412 29.565 ;
     RECT  119.34 29.295 140.4 29.565 ;
     RECT  2.16 29.835 20.412 30.105 ;
     RECT  119.34 29.835 140.4 30.105 ;
     RECT  2.16 30.375 20.412 30.645 ;
     RECT  119.34 30.375 140.4 30.645 ;
     RECT  2.16 30.915 20.412 31.185 ;
     RECT  119.34 30.915 140.4 31.185 ;
     RECT  2.16 31.455 20.412 31.725 ;
     RECT  119.34 31.455 140.4 31.725 ;
     RECT  2.16 31.995 20.412 32.265 ;
     RECT  119.34 31.995 140.4 32.265 ;
     RECT  2.16 32.535 20.412 32.805 ;
     RECT  119.34 32.535 140.4 32.805 ;
     RECT  2.16 33.075 20.412 33.345 ;
     RECT  119.34 33.075 140.4 33.345 ;
     RECT  2.16 33.615 20.412 33.885 ;
     RECT  119.34 33.615 140.4 33.885 ;
     RECT  2.16 34.155 20.412 34.425 ;
     RECT  119.34 34.155 140.4 34.425 ;
     RECT  2.16 34.695 20.412 34.965 ;
     RECT  119.34 34.695 140.4 34.965 ;
     RECT  2.16 35.235 20.412 35.505 ;
     RECT  119.34 35.235 140.4 35.505 ;
     RECT  2.16 35.775 20.412 36.045 ;
     RECT  119.34 35.775 140.4 36.045 ;
     RECT  2.16 36.315 20.412 36.585 ;
     RECT  119.34 36.315 140.4 36.585 ;
     RECT  2.16 36.855 20.412 37.125 ;
     RECT  119.34 36.855 140.4 37.125 ;
     RECT  2.16 37.395 20.412 37.665 ;
     RECT  119.34 37.395 140.4 37.665 ;
     RECT  2.16 37.935 20.412 38.205 ;
     RECT  119.34 37.935 140.4 38.205 ;
     RECT  2.16 38.475 20.412 38.745 ;
     RECT  119.34 38.475 140.4 38.745 ;
     RECT  2.16 39.015 20.412 39.285 ;
     RECT  119.34 39.015 140.4 39.285 ;
     RECT  2.16 39.555 20.412 39.825 ;
     RECT  119.34 39.555 140.4 39.825 ;
     RECT  2.16 40.095 20.412 40.365 ;
     RECT  119.34 40.095 140.4 40.365 ;
     RECT  2.16 40.635 20.412 40.905 ;
     RECT  119.34 40.635 140.4 40.905 ;
     RECT  2.16 41.175 20.412 41.445 ;
     RECT  119.34 41.175 140.4 41.445 ;
     RECT  2.16 41.715 20.412 41.985 ;
     RECT  119.34 41.715 140.4 41.985 ;
     RECT  2.16 42.255 20.412 42.525 ;
     RECT  119.34 42.255 140.4 42.525 ;
     RECT  2.16 42.795 20.412 43.065 ;
     RECT  119.34 42.795 140.4 43.065 ;
     RECT  2.16 43.335 20.412 43.605 ;
     RECT  119.34 43.335 140.4 43.605 ;
     RECT  2.16 43.875 20.412 44.145 ;
     RECT  119.34 43.875 140.4 44.145 ;
     RECT  2.16 44.415 20.412 44.685 ;
     RECT  119.34 44.415 140.4 44.685 ;
     RECT  2.16 44.955 20.412 45.225 ;
     RECT  119.34 44.955 140.4 45.225 ;
     RECT  2.16 45.495 20.412 45.765 ;
     RECT  119.34 45.495 140.4 45.765 ;
     RECT  2.16 46.035 20.412 46.305 ;
     RECT  119.34 46.035 140.4 46.305 ;
     RECT  2.16 46.575 20.412 46.845 ;
     RECT  119.34 46.575 140.4 46.845 ;
     RECT  2.16 47.115 20.412 47.385 ;
     RECT  119.34 47.115 140.4 47.385 ;
     RECT  2.16 47.655 20.412 47.925 ;
     RECT  119.34 47.655 140.4 47.925 ;
     RECT  2.16 48.195 20.412 48.465 ;
     RECT  119.34 48.195 140.4 48.465 ;
     RECT  2.16 48.735 20.412 49.005 ;
     RECT  119.34 48.735 140.4 49.005 ;
     RECT  2.16 49.275 20.412 49.545 ;
     RECT  119.34 49.275 140.4 49.545 ;
     RECT  2.16 49.815 20.412 50.085 ;
     RECT  119.34 49.815 140.4 50.085 ;
     RECT  2.16 50.355 20.412 50.625 ;
     RECT  119.34 50.355 140.4 50.625 ;
     RECT  2.16 50.895 20.412 51.165 ;
     RECT  119.34 50.895 140.4 51.165 ;
     RECT  2.16 51.435 20.412 51.705 ;
     RECT  119.34 51.435 140.4 51.705 ;
     RECT  2.16 51.975 20.412 52.245 ;
     RECT  119.34 51.975 140.4 52.245 ;
     RECT  2.16 52.515 20.412 52.785 ;
     RECT  119.34 52.515 140.4 52.785 ;
     RECT  2.16 53.055 20.412 53.325 ;
     RECT  119.34 53.055 140.4 53.325 ;
     RECT  2.16 53.595 20.412 53.865 ;
     RECT  119.34 53.595 140.4 53.865 ;
     RECT  2.16 54.135 20.412 54.405 ;
     RECT  119.34 54.135 140.4 54.405 ;
     RECT  2.16 54.675 20.412 54.945 ;
     RECT  119.34 54.675 140.4 54.945 ;
     RECT  2.16 55.215 20.412 55.485 ;
     RECT  119.34 55.215 140.4 55.485 ;
     RECT  2.16 55.755 20.412 56.025 ;
     RECT  119.34 55.755 140.4 56.025 ;
     RECT  2.16 56.295 20.412 56.565 ;
     RECT  119.34 56.295 140.4 56.565 ;
     RECT  2.16 56.835 20.412 57.105 ;
     RECT  119.34 56.835 140.4 57.105 ;
     RECT  2.16 57.375 20.412 57.645 ;
     RECT  119.34 57.375 140.4 57.645 ;
     RECT  2.16 57.915 20.412 58.185 ;
     RECT  119.34 57.915 140.4 58.185 ;
     RECT  2.16 58.455 20.412 58.725 ;
     RECT  119.34 58.455 140.4 58.725 ;
     RECT  2.16 58.995 20.412 59.265 ;
     RECT  119.34 58.995 140.4 59.265 ;
     RECT  2.16 59.535 20.412 59.805 ;
     RECT  119.34 59.535 140.4 59.805 ;
     RECT  2.16 60.075 20.412 60.345 ;
     RECT  119.34 60.075 140.4 60.345 ;
     RECT  2.16 60.615 20.412 60.885 ;
     RECT  119.34 60.615 140.4 60.885 ;
     RECT  2.16 61.155 20.412 61.425 ;
     RECT  119.34 61.155 140.4 61.425 ;
     RECT  2.16 61.695 20.412 61.965 ;
     RECT  119.34 61.695 140.4 61.965 ;
     RECT  2.16 62.235 20.412 62.505 ;
     RECT  119.34 62.235 140.4 62.505 ;
     RECT  2.16 62.775 20.412 63.045 ;
     RECT  119.34 62.775 140.4 63.045 ;
     RECT  2.16 63.315 20.412 63.585 ;
     RECT  119.34 63.315 140.4 63.585 ;
     RECT  2.16 63.855 20.412 64.125 ;
     RECT  119.34 63.855 140.4 64.125 ;
     RECT  2.16 64.395 20.412 64.665 ;
     RECT  119.34 64.395 140.4 64.665 ;
     RECT  2.16 64.935 20.412 65.205 ;
     RECT  119.34 64.935 140.4 65.205 ;
     RECT  2.16 65.475 20.412 65.61 ;
     RECT  119.34 65.475 140.4 65.61 ;
     RECT  2.16 65.61 140.4 65.745 ;
     RECT  2.16 66.015 140.4 66.285 ;
     RECT  2.16 66.555 140.4 66.825 ;
     RECT  2.16 67.095 140.4 67.365 ;
     RECT  2.16 67.635 140.4 67.905 ;
     RECT  2.16 68.175 140.4 68.445 ;
     RECT  2.16 68.715 140.4 68.985 ;
     RECT  2.16 69.255 140.4 69.525 ;
     RECT  2.16 69.795 140.4 70.065 ;
     RECT  2.16 70.335 140.4 70.605 ;
     RECT  2.16 70.875 140.4 71.145 ;
     RECT  2.16 71.415 140.4 71.685 ;
     RECT  2.16 71.955 140.4 72.225 ;
     RECT  2.16 72.495 140.4 72.765 ;
     RECT  2.16 73.035 140.4 73.305 ;
     RECT  2.16 73.575 140.4 73.845 ;
     RECT  2.16 74.115 140.4 74.385 ;
     RECT  2.16 74.655 140.4 74.925 ;
     RECT  2.16 75.195 140.4 75.465 ;
     RECT  2.16 75.735 140.4 76.005 ;
     RECT  2.16 76.275 140.4 76.545 ;
     RECT  2.16 76.815 140.4 77.085 ;
     RECT  2.16 77.355 140.4 77.625 ;
     RECT  2.16 77.895 140.4 78.165 ;
     RECT  2.16 78.435 140.4 78.705 ;
     RECT  2.16 78.975 140.4 79.245 ;
     RECT  2.16 79.515 140.4 79.785 ;
     RECT  2.16 80.055 140.4 80.325 ;
     RECT  2.16 80.595 140.4 80.865 ;
     RECT  2.16 81.135 140.4 81.405 ;
     RECT  2.16 81.675 140.4 81.945 ;
     RECT  2.16 82.215 140.4 82.485 ;
     RECT  2.16 82.755 140.4 83.025 ;
     RECT  2.16 83.295 140.4 83.565 ;
     RECT  2.16 83.835 140.4 84.105 ;
    LAYER M1 ;
     RECT  2.16 2.151 140.4 20.259 ;
     RECT  22.464 22.464 117.288 63.528 ;
     RECT  2.16 20.259 20.412 65.601 ;
     RECT  119.34 20.259 140.4 65.601 ;
     RECT  2.16 65.601 140.4 84.249 ;
    LAYER M2 ;
     RECT  0.211 38.988 0.247 40.158 ;
     RECT  0.211 41.382 0.247 42.75 ;
     RECT  0.211 37.602 0.535 37.998 ;
     RECT  0.247 38.988 0.535 40.32 ;
     RECT  0.247 41.256 0.535 43.29 ;
     RECT  1.039 64.206 1.075 64.224 ;
     RECT  0.535 38.988 1.471 43.29 ;
     RECT  0.535 37.404 1.543 37.998 ;
     RECT  1.471 38.826 1.543 43.29 ;
     RECT  0.211 32.814 1.723 36.612 ;
     RECT  1.543 37.404 1.723 43.29 ;
     RECT  0.535 44.73 1.723 44.748 ;
     RECT  1.723 37.404 1.795 43.668 ;
     RECT  1.723 44.424 1.795 45.018 ;
     RECT  1.399 27.756 1.975 27.774 ;
     RECT  1.687 22.626 2.16 22.644 ;
     RECT  1.003 23.634 2.16 23.652 ;
     RECT  1.975 27.342 2.16 27.774 ;
     RECT  1.111 31.428 2.16 31.446 ;
     RECT  1.723 32.346 2.16 36.612 ;
     RECT  1.795 37.404 2.16 45.018 ;
     RECT  2.047 54.486 2.16 54.504 ;
     RECT  1.579 56.268 2.16 56.286 ;
     RECT  2.083 58.806 2.16 58.824 ;
     RECT  1.543 59.616 2.16 59.634 ;
     RECT  1.507 61.506 2.16 61.524 ;
     RECT  1.075 64.206 2.16 64.494 ;
     RECT  2.16 2.151 4.099 84.249 ;
     RECT  4.099 2.151 14.251 84.636 ;
     RECT  14.251 2.151 20.412 85.284 ;
     RECT  20.412 51.246 20.435 85.284 ;
     RECT  20.412 24.21 20.471 34.884 ;
     RECT  20.435 51.246 20.471 56.664 ;
     RECT  20.412 2.151 20.507 23.076 ;
     RECT  20.471 51.246 20.507 56.592 ;
     RECT  20.435 57.618 20.507 85.284 ;
     RECT  20.412 35.856 20.543 39.51 ;
     RECT  20.507 54.486 20.543 56.592 ;
     RECT  20.507 57.618 20.543 62.334 ;
     RECT  20.471 26.838 20.579 34.884 ;
     RECT  20.543 38.826 20.579 39.51 ;
     RECT  20.412 40.374 20.615 46.908 ;
     RECT  20.471 24.21 20.687 26.046 ;
     RECT  20.579 26.838 20.723 34.686 ;
     RECT  20.723 26.838 20.831 34.452 ;
     RECT  20.687 25.956 20.867 26.046 ;
     RECT  20.831 26.838 20.867 28.314 ;
     RECT  20.543 57.924 20.867 62.334 ;
     RECT  20.507 51.246 20.939 53.586 ;
     RECT  20.867 61.866 20.975 62.064 ;
     RECT  20.507 2.151 21.011 23.004 ;
     RECT  20.939 51.246 21.011 51.264 ;
     RECT  20.975 62.046 21.011 62.064 ;
     RECT  20.615 40.878 21.047 46.908 ;
     RECT  20.543 54.486 21.047 56.439 ;
     RECT  20.867 57.924 21.047 61.074 ;
     RECT  21.011 2.151 21.091 22.842 ;
     RECT  20.412 47.736 21.119 49.374 ;
     RECT  20.831 29.07 21.155 34.452 ;
     RECT  21.047 54.486 21.155 56.052 ;
     RECT  20.687 24.21 21.191 24.804 ;
     RECT  21.047 57.924 21.191 60.408 ;
     RECT  20.867 26.838 21.227 28.044 ;
     RECT  21.155 30.618 21.227 34.452 ;
     RECT  21.227 30.618 21.263 33.876 ;
     RECT  20.939 52.686 21.263 53.586 ;
     RECT  20.543 35.856 21.271 38.034 ;
     RECT  21.047 41.49 21.299 46.908 ;
     RECT  21.155 54.486 21.299 55.584 ;
     RECT  21.299 41.49 21.335 42.894 ;
     RECT  21.119 48.276 21.335 49.374 ;
     RECT  21.191 60.156 21.335 60.408 ;
     RECT  21.227 27.486 21.371 28.044 ;
     RECT  21.263 31.806 21.407 33.876 ;
     RECT  21.371 27.486 21.443 27.774 ;
     RECT  21.271 35.856 21.479 38.124 ;
     RECT  21.263 52.686 21.515 53.514 ;
     RECT  21.335 41.526 21.551 42.894 ;
     RECT  21.515 52.686 21.551 52.848 ;
     RECT  20.412 50.256 21.559 50.274 ;
     RECT  21.335 60.156 21.623 60.174 ;
     RECT  21.443 27.684 21.659 27.774 ;
     RECT  21.155 29.07 21.659 29.826 ;
     RECT  21.559 50.256 21.659 50.346 ;
     RECT  21.263 30.618 21.695 30.87 ;
     RECT  21.407 31.806 21.695 33.408 ;
     RECT  21.479 36.018 21.695 38.124 ;
     RECT  21.551 41.526 21.695 42.858 ;
     RECT  21.299 43.65 21.695 46.908 ;
     RECT  20.867 26.028 21.731 26.046 ;
     RECT  21.659 29.106 21.731 29.826 ;
     RECT  21.695 43.65 21.731 44.208 ;
     RECT  21.191 24.372 21.775 24.804 ;
     RECT  21.091 1.998 22.099 22.842 ;
     RECT  21.335 48.978 22.207 49.374 ;
     RECT  22.099 1.926 22.279 22.842 ;
     RECT  22.279 1.926 22.464 23.31 ;
     RECT  21.775 24.372 22.464 25.119 ;
     RECT  21.731 29.106 22.464 29.754 ;
     RECT  21.695 30.69 22.464 30.87 ;
     RECT  21.695 31.806 22.464 33.066 ;
     RECT  21.695 36.018 22.464 37.494 ;
     RECT  21.667 39.906 22.464 39.924 ;
     RECT  21.695 41.526 22.464 41.544 ;
     RECT  21.695 42.534 22.464 42.858 ;
     RECT  21.731 43.65 22.464 43.668 ;
     RECT  21.695 45.198 22.464 46.908 ;
     RECT  22.207 48.78 22.464 49.374 ;
     RECT  21.551 52.83 22.464 52.848 ;
     RECT  21.299 54.486 22.464 54.702 ;
     RECT  21.299 55.566 22.464 55.584 ;
     RECT  21.191 57.924 22.464 59.094 ;
     RECT  20.507 63.324 22.464 85.284 ;
     RECT  22.464 1.926 22.639 85.284 ;
     RECT  22.639 1.26 22.675 85.284 ;
     RECT  22.675 1.116 24.331 85.284 ;
     RECT  24.331 0.882 25.123 85.284 ;
     RECT  26.131 86.202 26.231 86.292 ;
     RECT  25.123 0.684 26.239 85.284 ;
     RECT  26.239 0.144 26.815 85.284 ;
     RECT  26.815 0.144 26.951 85.41 ;
     RECT  26.951 0.144 27.383 85.329 ;
     RECT  26.231 86.274 27.463 86.292 ;
     RECT  27.463 86.274 27.499 86.328 ;
     RECT  27.383 0.144 27.599 63.882 ;
     RECT  27.499 86.238 27.599 86.328 ;
     RECT  27.599 0.684 28.363 63.882 ;
     RECT  28.363 0.144 28.427 63.882 ;
     RECT  28.427 0.684 29.299 63.882 ;
     RECT  27.599 86.274 29.759 86.292 ;
     RECT  29.299 0.144 30.911 63.882 ;
     RECT  31.207 86.31 31.243 86.328 ;
     RECT  31.243 86.238 31.343 86.328 ;
     RECT  30.911 0.306 31.675 63.882 ;
     RECT  27.383 64.674 33.367 85.329 ;
     RECT  33.367 64.674 33.691 85.518 ;
     RECT  33.655 86.31 33.691 86.328 ;
     RECT  33.691 64.674 33.791 86.328 ;
     RECT  31.675 0.144 34.115 63.882 ;
     RECT  33.791 64.674 34.583 85.518 ;
     RECT  34.115 0.684 34.987 63.882 ;
     RECT  34.583 64.674 35.303 85.329 ;
     RECT  34.987 0.144 35.699 63.882 ;
     RECT  37.255 86.31 37.291 86.328 ;
     RECT  37.291 86.238 37.391 86.328 ;
     RECT  35.699 0.684 37.723 63.882 ;
     RECT  35.303 64.674 38.039 85.248 ;
     RECT  37.723 0.144 38.119 63.882 ;
     RECT  38.119 0.036 39.047 63.882 ;
     RECT  38.039 85.194 39.479 85.248 ;
     RECT  38.039 64.674 40.099 84.249 ;
     RECT  39.479 85.194 40.199 85.212 ;
     RECT  40.099 64.674 40.343 84.33 ;
     RECT  39.047 0.036 40.739 63.528 ;
     RECT  40.343 64.674 42.359 84.249 ;
     RECT  40.739 0.144 42.439 63.528 ;
     RECT  42.359 64.674 42.503 64.692 ;
     RECT  42.359 65.601 47.299 84.249 ;
     RECT  47.299 65.601 47.831 84.294 ;
     RECT  42.439 0.036 70.439 63.528 ;
     RECT  70.439 0.036 73.499 0.09 ;
     RECT  70.439 0.846 73.751 63.528 ;
     RECT  73.751 1.026 73.823 63.528 ;
     RECT  73.499 0.036 73.967 0.054 ;
     RECT  73.823 1.116 83.903 63.528 ;
     RECT  83.903 2.151 117.288 63.528 ;
     RECT  117.288 23.976 117.419 23.994 ;
     RECT  117.288 26.181 117.419 26.82 ;
     RECT  117.419 26.181 117.851 26.199 ;
     RECT  117.288 27.918 118.427 27.936 ;
     RECT  117.288 30.816 118.571 30.834 ;
     RECT  117.288 2.151 119.34 21.996 ;
     RECT  117.288 29.034 119.34 29.052 ;
     RECT  117.288 33.588 119.34 63 ;
     RECT  47.831 65.601 119.34 84.249 ;
     RECT  83.903 1.116 119.867 1.134 ;
     RECT  119.34 2.151 140.4 84.249 ;
     RECT  140.4 51.786 141.395 51.804 ;
    LAYER M3 ;
     RECT  42.444 0.031 42.462 0.067 ;
     RECT  73.944 0.031 73.962 0.067 ;
     RECT  42.444 0.067 42.678 0.103 ;
     RECT  38.124 0.031 38.142 0.108 ;
     RECT  40.716 0.031 40.734 0.108 ;
     RECT  42.444 0.103 42.822 0.108 ;
     RECT  57.06 0.103 57.078 0.108 ;
     RECT  60.696 0.103 60.714 0.108 ;
     RECT  66.708 0.103 66.726 0.108 ;
     RECT  73.476 0.067 73.962 0.139 ;
     RECT  66.528 0.108 67.842 0.175 ;
     RECT  24.48 0.108 61.218 0.211 ;
     RECT  23.508 0.187 23.526 0.235 ;
     RECT  24.48 0.211 61.29 0.235 ;
     RECT  69.732 0.256 69.75 0.283 ;
     RECT  69.084 0.283 69.75 0.301 ;
     RECT  70.488 0.108 71.082 0.301 ;
     RECT  66.204 0.175 67.842 0.427 ;
     RECT  62.748 0.139 62.766 0.811 ;
     RECT  63.864 0.175 63.882 0.841 ;
     RECT  73.476 0.139 74.25 0.877 ;
     RECT  22.392 0.139 22.41 0.907 ;
     RECT  23.508 0.235 61.29 0.907 ;
     RECT  62.388 0.811 62.766 0.913 ;
     RECT  63.648 0.841 63.882 0.913 ;
     RECT  72.108 0.235 72.126 1.066 ;
     RECT  69.084 0.301 71.082 1.147 ;
     RECT  71.892 1.066 72.126 1.147 ;
     RECT  69.084 1.147 72.126 1.387 ;
     RECT  62.388 0.913 63.882 1.417 ;
     RECT  66.132 0.427 67.842 1.435 ;
     RECT  22.392 0.907 61.29 1.489 ;
     RECT  62.388 1.417 63.99 1.489 ;
     RECT  22.392 1.489 63.99 1.675 ;
     RECT  66.132 1.435 67.986 1.759 ;
     RECT  22.392 1.675 64.242 1.819 ;
     RECT  73.296 0.877 74.25 1.867 ;
     RECT  66.132 1.759 68.13 1.876 ;
     RECT  69.084 1.387 72.198 1.876 ;
     RECT  73.296 1.867 74.682 1.876 ;
     RECT  22.212 1.819 64.242 1.921 ;
     RECT  73.116 1.876 74.682 1.957 ;
     RECT  22.104 1.921 64.242 2.101 ;
     RECT  73.044 1.957 74.754 2.101 ;
     RECT  66.132 1.876 72.198 2.143 ;
     RECT  72.972 2.101 74.754 2.143 ;
     RECT  83.88 1.687 83.898 2.143 ;
     RECT  21.096 1.993 21.114 2.191 ;
     RECT  21.852 2.101 64.242 2.191 ;
     RECT  66.132 2.143 74.754 2.191 ;
     RECT  78.015 2.143 78.105 2.191 ;
     RECT  88.815 2.143 88.905 2.191 ;
     RECT  99.615 2.143 99.705 2.191 ;
     RECT  110.415 2.143 110.505 2.191 ;
     RECT  21.096 2.191 64.242 2.263 ;
     RECT  21.096 2.263 64.962 2.299 ;
     RECT  66.132 2.191 74.79 2.299 ;
     RECT  83.415 2.143 83.898 2.371 ;
     RECT  18.615 2.143 18.705 2.395 ;
     RECT  2.415 2.143 2.505 2.413 ;
     RECT  7.815 2.143 7.905 2.413 ;
     RECT  13.215 2.143 13.305 2.413 ;
     RECT  77.904 2.191 78.21 2.413 ;
     RECT  88.704 2.191 89.01 2.413 ;
     RECT  94.215 2.143 94.305 2.413 ;
     RECT  99.504 2.191 99.81 2.413 ;
     RECT  105.015 2.143 105.105 2.413 ;
     RECT  110.304 2.191 110.61 2.413 ;
     RECT  115.815 2.143 115.905 2.413 ;
     RECT  121.215 2.143 121.305 2.413 ;
     RECT  126.615 2.143 126.705 2.413 ;
     RECT  132.015 2.143 132.105 2.413 ;
     RECT  137.415 2.143 137.505 2.413 ;
     RECT  21.096 2.299 74.79 2.533 ;
     RECT  18.615 2.395 19.098 2.569 ;
     RECT  88.704 2.413 89.097 2.605 ;
     RECT  77.904 2.413 78.297 2.641 ;
     RECT  13.215 2.413 13.497 2.731 ;
     RECT  18.615 2.569 19.206 2.731 ;
     RECT  110.304 2.413 110.697 2.765 ;
     RECT  77.904 2.641 78.786 2.767 ;
     RECT  13.104 2.731 13.497 2.768 ;
     RECT  77.904 2.767 79.254 2.768 ;
     RECT  99.504 2.413 99.897 2.768 ;
     RECT  94.215 2.413 94.497 2.779 ;
     RECT  21.096 2.533 74.934 2.795 ;
     RECT  21.096 2.795 65.214 2.803 ;
     RECT  115.815 2.413 116.097 2.827 ;
     RECT  78.015 2.768 79.254 2.839 ;
     RECT  18.615 2.731 19.242 2.861 ;
     RECT  76.428 2.461 76.446 2.911 ;
     RECT  119.844 1.111 119.862 3.001 ;
     RECT  82.692 2.371 83.898 3.019 ;
     RECT  81.144 2.335 81.162 3.037 ;
     RECT  76.392 2.911 76.446 3.109 ;
     RECT  18.615 2.861 19.206 3.145 ;
     RECT  76.392 3.109 76.986 3.145 ;
     RECT  81.144 3.037 81.486 3.181 ;
     RECT  86.076 2.299 86.094 3.181 ;
     RECT  87.228 2.299 87.246 3.181 ;
     RECT  117.828 3.145 117.846 3.181 ;
     RECT  65.952 2.795 74.934 3.259 ;
     RECT  86.076 3.181 87.246 3.299 ;
     RECT  92.34 2.263 92.358 3.299 ;
     RECT  80.388 1.723 80.406 3.307 ;
     RECT  81.144 3.181 81.522 3.307 ;
     RECT  93.492 2.779 94.497 3.307 ;
     RECT  76.392 3.145 77.022 3.355 ;
     RECT  88.524 2.605 89.097 3.379 ;
     RECT  119.16 3.001 119.862 3.379 ;
     RECT  76.392 3.355 77.094 3.407 ;
     RECT  92.88 3.307 94.497 3.407 ;
     RECT  84.924 3.307 84.942 3.415 ;
     RECT  82.548 3.019 83.898 3.451 ;
     RECT  84.924 3.415 85.086 3.451 ;
     RECT  82.548 3.451 85.158 3.541 ;
     RECT  87.804 3.379 89.097 3.569 ;
     RECT  90.792 3.451 90.81 3.569 ;
     RECT  93.384 3.407 94.497 3.569 ;
     RECT  118.944 3.379 119.862 3.613 ;
     RECT  82.548 3.541 85.554 3.641 ;
     RECT  21.06 2.803 65.214 3.649 ;
     RECT  65.952 3.259 75.258 3.649 ;
     RECT  80.388 3.307 81.522 3.649 ;
     RECT  117.72 3.181 117.846 3.649 ;
     RECT  118.656 3.613 119.862 3.649 ;
     RECT  114.588 2.059 114.606 3.677 ;
     RECT  21.06 3.649 75.258 3.811 ;
     RECT  76.392 3.407 77.058 3.811 ;
     RECT  21.06 3.811 77.058 3.839 ;
     RECT  76.968 3.839 77.058 3.875 ;
     RECT  21.06 3.839 75.942 3.911 ;
     RECT  21.996 3.911 75.942 3.917 ;
     RECT  12.204 2.605 12.222 3.919 ;
     RECT  21.06 3.911 21.186 3.947 ;
     RECT  80.352 3.649 81.522 3.979 ;
     RECT  22.14 3.917 75.942 3.983 ;
     RECT  15.408 2.875 15.426 3.991 ;
     RECT  80.172 3.979 81.522 3.991 ;
     RECT  82.548 3.641 85.374 3.991 ;
     RECT  91.044 3.721 91.062 4.081 ;
     RECT  74.484 3.983 75.942 4.109 ;
     RECT  78.015 2.839 79.326 4.109 ;
     RECT  80.172 3.991 85.374 4.109 ;
     RECT  86.616 4.081 86.634 4.117 ;
     RECT  117.72 3.649 119.862 4.117 ;
     RECT  13.215 2.768 13.497 4.153 ;
     RECT  86.544 4.117 86.634 4.217 ;
     RECT  18.468 3.145 19.206 4.225 ;
     RECT  80.172 4.109 80.442 4.225 ;
     RECT  117.72 4.117 119.898 4.225 ;
     RECT  78.015 4.109 78.714 4.261 ;
     RECT  117.72 4.225 120.042 4.261 ;
     RECT  121.215 2.413 121.497 4.261 ;
     RECT  91.044 4.081 91.242 4.387 ;
     RECT  77.4 4.261 78.714 4.451 ;
     RECT  91.044 4.387 91.494 4.459 ;
     RECT  79.524 4.225 80.442 4.487 ;
     RECT  81.468 4.109 85.374 4.507 ;
     RECT  89.82 3.955 89.838 4.531 ;
     RECT  22.14 3.983 73.602 4.559 ;
     RECT  81.468 4.507 85.446 4.559 ;
     RECT  91.008 4.459 91.494 4.559 ;
     RECT  93.384 3.569 93.402 4.621 ;
     RECT  94.215 3.569 94.497 4.621 ;
     RECT  93.384 4.621 94.497 4.657 ;
     RECT  89.82 4.531 89.946 4.801 ;
     RECT  91.008 4.559 91.062 4.801 ;
     RECT  93.384 4.657 94.554 4.801 ;
     RECT  81.468 4.559 82.278 4.829 ;
     RECT  86.652 4.363 86.67 4.829 ;
     RECT  18.468 4.225 19.638 4.891 ;
     RECT  89.82 4.801 91.062 4.919 ;
     RECT  93.384 4.801 94.626 4.919 ;
     RECT  22.392 4.559 73.602 4.991 ;
     RECT  17.64 3.451 17.658 5.035 ;
     RECT  92.34 4.795 92.358 5.063 ;
     RECT  69.768 4.991 73.602 5.071 ;
     RECT  75.924 4.109 75.942 5.071 ;
     RECT  77.4 4.451 78.642 5.071 ;
     RECT  93.384 4.919 94.497 5.071 ;
     RECT  18.468 4.891 19.746 5.161 ;
     RECT  21.06 3.947 21.078 5.233 ;
     RECT  20.952 5.233 21.078 5.261 ;
     RECT  75.924 5.071 78.642 5.269 ;
     RECT  79.524 4.487 79.542 5.269 ;
     RECT  99.615 2.768 99.897 5.305 ;
     RECT  110.415 2.765 110.697 5.305 ;
     RECT  99.504 5.305 99.897 5.357 ;
     RECT  110.304 5.305 110.697 5.357 ;
     RECT  22.392 4.991 68.994 5.461 ;
     RECT  83.415 4.559 84.906 5.467 ;
     RECT  114.588 5.323 114.606 5.501 ;
     RECT  74.484 4.109 75.114 5.539 ;
     RECT  75.924 5.269 79.542 5.539 ;
     RECT  22.284 5.461 68.994 5.563 ;
     RECT  22.212 5.563 68.994 5.603 ;
     RECT  86.904 5.503 87.21 5.611 ;
     RECT  86.724 5.611 87.21 5.701 ;
     RECT  88.236 3.569 89.097 5.701 ;
     RECT  89.82 4.919 89.946 5.701 ;
     RECT  86.724 5.701 87.354 5.707 ;
     RECT  81.468 4.829 82.242 5.737 ;
     RECT  83.232 5.467 84.906 5.737 ;
     RECT  22.248 5.603 68.994 5.773 ;
     RECT  69.768 5.071 73.746 5.773 ;
     RECT  81.468 5.737 84.906 5.773 ;
     RECT  22.248 5.773 73.746 5.803 ;
     RECT  74.484 5.539 79.542 5.803 ;
     RECT  7.815 2.413 8.097 5.809 ;
     RECT  80.424 4.487 80.442 5.845 ;
     RECT  81.468 5.773 85.014 5.845 ;
     RECT  92.736 5.071 94.497 5.845 ;
     RECT  22.248 5.803 79.542 5.881 ;
     RECT  80.424 5.845 85.086 5.881 ;
     RECT  86.724 5.707 87.462 5.899 ;
     RECT  86.616 5.899 87.462 5.971 ;
     RECT  91.044 4.919 91.062 5.971 ;
     RECT  18.468 5.161 19.782 6.043 ;
     RECT  20.952 5.261 20.97 6.043 ;
     RECT  117.72 4.261 121.497 6.043 ;
     RECT  18.468 6.043 20.97 6.079 ;
     RECT  86.544 5.971 87.462 6.079 ;
     RECT  88.236 5.701 89.946 6.079 ;
     RECT  91.044 5.971 91.494 6.115 ;
     RECT  11.88 3.919 12.222 6.151 ;
     RECT  22.248 5.881 85.698 6.151 ;
     RECT  86.544 6.079 89.946 6.151 ;
     RECT  91.044 6.115 91.566 6.151 ;
     RECT  92.7 5.845 94.497 6.151 ;
     RECT  22.248 6.151 89.946 6.221 ;
     RECT  90.864 6.151 91.566 6.235 ;
     RECT  92.412 6.151 94.497 6.235 ;
     RECT  95.688 5.575 95.706 6.241 ;
     RECT  22.248 6.221 25.938 6.269 ;
     RECT  95.4 6.241 95.706 6.283 ;
     RECT  95.256 6.283 95.706 6.349 ;
     RECT  26.784 6.221 89.946 6.379 ;
     RECT  90.864 6.235 94.497 6.379 ;
     RECT  9.576 5.341 9.594 6.385 ;
     RECT  26.784 6.379 94.497 6.385 ;
     RECT  95.256 6.349 96.03 6.385 ;
     RECT  18.432 6.079 20.97 6.421 ;
     RECT  22.248 6.269 24.966 6.421 ;
     RECT  117.72 6.043 121.554 6.547 ;
     RECT  99.615 5.357 99.897 6.619 ;
     RECT  26.784 6.385 96.03 6.647 ;
     RECT  26.784 6.647 51.678 6.719 ;
     RECT  99.324 6.619 99.897 6.763 ;
     RECT  105.015 2.413 105.297 6.763 ;
     RECT  110.415 5.357 110.697 6.763 ;
     RECT  14.76 3.991 15.426 6.781 ;
     RECT  14.76 6.781 15.786 6.808 ;
     RECT  52.452 6.647 96.03 6.808 ;
     RECT  99.324 6.763 99.99 6.809 ;
     RECT  105.015 6.763 105.39 6.809 ;
     RECT  110.415 6.763 110.79 6.809 ;
     RECT  7.815 5.809 8.658 6.853 ;
     RECT  13.215 4.153 13.77 6.853 ;
     RECT  110.415 6.809 110.697 6.952 ;
     RECT  25.92 6.269 25.938 6.953 ;
     RECT  52.452 6.808 96.426 7.051 ;
     RECT  97.74 7.003 97.758 7.051 ;
     RECT  14.76 6.808 15.858 7.087 ;
     RECT  97.74 7.051 98.046 7.147 ;
     RECT  99.324 6.809 99.897 7.147 ;
     RECT  16.992 5.035 17.658 7.189 ;
     RECT  97.74 7.147 99.897 7.189 ;
     RECT  14.76 7.087 15.966 7.195 ;
     RECT  16.776 7.189 17.658 7.195 ;
     RECT  52.452 7.051 96.462 7.195 ;
     RECT  52.452 7.195 96.534 7.339 ;
     RECT  97.668 7.189 99.897 7.357 ;
     RECT  13.215 6.853 13.806 7.387 ;
     RECT  14.724 7.195 17.658 7.387 ;
     RECT  18.432 6.421 24.966 7.387 ;
     RECT  14.724 7.387 24.966 7.429 ;
     RECT  101.124 7.321 101.142 7.435 ;
     RECT  50.04 6.719 51.678 7.465 ;
     RECT  52.452 7.339 96.642 7.465 ;
     RECT  13.104 7.387 13.806 7.501 ;
     RECT  14.724 7.429 25.002 7.501 ;
     RECT  110.304 6.952 110.697 7.529 ;
     RECT  13.104 7.501 25.038 7.591 ;
     RECT  50.04 7.465 96.642 7.591 ;
     RECT  97.56 7.357 99.897 7.591 ;
     RECT  100.656 7.435 101.142 7.627 ;
     RECT  101.916 7.501 101.934 7.627 ;
     RECT  114.588 6.619 114.606 7.661 ;
     RECT  13.104 7.591 25.11 7.723 ;
     RECT  100.656 7.627 101.934 7.771 ;
     RECT  26.784 6.719 49.302 7.897 ;
     RECT  100.656 7.771 102.006 7.925 ;
     RECT  13.104 7.723 25.83 8.041 ;
     RECT  26.604 7.897 49.302 8.041 ;
     RECT  11.592 6.151 12.222 8.167 ;
     RECT  13.104 8.041 49.302 8.167 ;
     RECT  50.04 7.591 99.897 8.167 ;
     RECT  11.592 8.167 99.897 8.311 ;
     RECT  100.944 7.925 102.006 8.311 ;
     RECT  9.576 6.385 9.738 8.437 ;
     RECT  7.815 6.853 8.73 8.491 ;
     RECT  5.868 8.437 5.886 8.509 ;
     RECT  7.815 8.491 8.802 8.509 ;
     RECT  9.576 8.437 10.35 8.509 ;
     RECT  4.068 8.509 4.554 8.581 ;
     RECT  5.868 8.509 6.066 8.581 ;
     RECT  5.328 8.581 6.894 8.707 ;
     RECT  11.592 8.311 100.206 8.707 ;
     RECT  100.944 8.311 102.042 8.707 ;
     RECT  3.78 8.581 4.554 8.851 ;
     RECT  5.328 8.707 7.002 8.851 ;
     RECT  7.815 8.509 10.566 8.851 ;
     RECT  11.592 8.707 102.042 8.851 ;
     RECT  3.78 8.851 102.042 8.861 ;
     RECT  3.78 8.861 100.062 8.969 ;
     RECT  100.8 8.861 102.042 9.005 ;
     RECT  3.78 8.969 99.99 9.067 ;
     RECT  2.415 2.413 2.697 9.115 ;
     RECT  2.415 9.115 2.826 9.391 ;
     RECT  3.708 9.067 99.99 9.391 ;
     RECT  2.415 9.391 99.99 9.691 ;
     RECT  100.8 9.005 100.962 9.691 ;
     RECT  103.032 9.751 103.05 9.787 ;
     RECT  2.415 9.691 100.962 9.815 ;
     RECT  13.104 9.815 100.962 9.859 ;
     RECT  101.808 9.005 102.042 9.859 ;
     RECT  13.104 9.859 102.078 9.931 ;
     RECT  103.032 9.787 103.23 9.931 ;
     RECT  13.104 9.931 103.23 10.201 ;
     RECT  13.104 10.201 103.77 10.319 ;
     RECT  13.104 10.319 101.178 10.355 ;
     RECT  101.916 10.319 103.77 10.391 ;
     RECT  101.952 10.391 103.77 10.471 ;
     RECT  101.952 10.471 103.914 10.625 ;
     RECT  2.415 9.815 12.222 10.633 ;
     RECT  114.588 10.459 114.606 10.637 ;
     RECT  101.952 10.625 103.842 10.781 ;
     RECT  2.415 10.633 12.33 10.831 ;
     RECT  13.104 10.355 101.07 10.831 ;
     RECT  2.415 10.831 101.07 11.281 ;
     RECT  2.415 11.281 101.25 11.515 ;
     RECT  102.024 10.781 103.41 11.515 ;
     RECT  110.415 7.529 110.697 11.803 ;
     RECT  110.304 11.803 110.697 11.849 ;
     RECT  2.415 11.515 103.446 11.899 ;
     RECT  2.415 11.899 103.77 11.947 ;
     RECT  114.588 11.803 114.606 11.981 ;
     RECT  2.415 11.947 104.202 12.281 ;
     RECT  2.415 12.281 100.926 12.515 ;
     RECT  114.588 12.865 114.606 13.019 ;
     RECT  100.872 12.515 100.926 13.063 ;
     RECT  101.952 12.281 103.662 13.063 ;
     RECT  100.872 13.063 103.662 13.099 ;
     RECT  2.415 12.515 99.99 13.291 ;
     RECT  100.872 13.099 103.77 13.291 ;
     RECT  2.415 13.291 103.77 13.567 ;
     RECT  2.415 13.567 104.274 13.711 ;
     RECT  105.015 6.809 105.297 13.711 ;
     RECT  2.415 13.711 105.297 13.757 ;
     RECT  2.415 13.757 104.274 14.791 ;
     RECT  105.015 13.757 105.297 14.791 ;
     RECT  2.415 14.791 105.297 14.945 ;
     RECT  2.415 14.945 104.094 15.215 ;
     RECT  105.015 14.945 105.297 15.835 ;
     RECT  2.415 15.215 103.806 15.863 ;
     RECT  27.756 15.863 103.806 15.979 ;
     RECT  27.756 15.979 103.842 16.027 ;
     RECT  27.756 16.027 103.986 16.411 ;
     RECT  104.76 15.835 105.297 16.411 ;
     RECT  2.415 15.863 26.946 16.645 ;
     RECT  27.756 16.411 105.297 16.645 ;
     RECT  2.415 16.645 105.297 17.681 ;
     RECT  100.98 17.681 105.297 18.023 ;
     RECT  104.976 18.023 105.297 18.149 ;
     RECT  2.415 17.681 100.206 18.221 ;
     RECT  100.98 18.023 104.238 18.293 ;
     RECT  3.6 18.221 100.206 18.499 ;
     RECT  100.98 18.293 103.806 18.499 ;
     RECT  2.415 18.221 2.697 19.003 ;
     RECT  2.415 19.003 2.754 19.111 ;
     RECT  3.6 18.499 103.806 19.111 ;
     RECT  2.415 19.111 103.878 19.301 ;
     RECT  2.415 19.301 103.734 19.373 ;
     RECT  47.664 19.373 102.798 19.499 ;
     RECT  103.644 19.373 103.662 19.499 ;
     RECT  96.372 19.499 102.798 19.535 ;
     RECT  75.924 19.499 95.598 19.571 ;
     RECT  96.444 19.535 102.798 19.571 ;
     RECT  47.664 19.499 74.97 19.661 ;
     RECT  2.415 19.373 46.746 19.769 ;
     RECT  49.896 19.661 74.97 19.769 ;
     RECT  75.924 19.571 77.058 19.769 ;
     RECT  77.904 19.571 95.598 19.769 ;
     RECT  49.896 19.769 69.57 19.805 ;
     RECT  70.308 19.769 74.97 19.805 ;
     RECT  78.015 19.769 95.598 19.805 ;
     RECT  50.328 19.805 66.33 19.811 ;
     RECT  70.344 19.805 74.97 19.811 ;
     RECT  50.328 19.811 66.222 19.841 ;
     RECT  78.015 19.805 78.39 19.841 ;
     RECT  51.015 19.841 66.222 19.877 ;
     RECT  59.832 19.877 66.222 19.901 ;
     RECT  110.415 11.849 110.697 19.912 ;
     RECT  2.415 19.769 46.026 19.913 ;
     RECT  59.832 19.901 64.314 19.913 ;
     RECT  67.14 19.805 69.57 19.913 ;
     RECT  79.308 19.805 95.598 19.913 ;
     RECT  96.444 19.571 101.034 19.913 ;
     RECT  2.415 19.913 44.622 19.949 ;
     RECT  47.664 19.661 47.682 19.949 ;
     RECT  51.015 19.877 59.094 19.949 ;
     RECT  81.792 19.913 84.078 19.949 ;
     RECT  84.816 19.913 94.698 19.949 ;
     RECT  101.916 19.571 102.798 19.949 ;
     RECT  110.304 19.912 110.697 19.949 ;
     RECT  114.588 19.819 114.606 19.949 ;
     RECT  51.015 19.949 52.218 19.997 ;
     RECT  78.015 19.841 78.297 19.997 ;
     RECT  83.415 19.949 84.078 19.997 ;
     RECT  105.015 18.149 105.297 19.997 ;
     RECT  110.415 19.949 110.697 19.997 ;
     RECT  115.815 2.827 116.55 19.997 ;
     RECT  2.415 19.949 33.354 20.039 ;
     RECT  45.396 19.913 46.026 20.039 ;
     RECT  53.028 19.949 59.094 20.039 ;
     RECT  59.868 19.913 64.314 20.039 ;
     RECT  65.16 19.901 66.222 20.039 ;
     RECT  70.344 19.811 71.154 20.039 ;
     RECT  72.396 19.811 74.97 20.039 ;
     RECT  85.572 19.949 87.21 20.039 ;
     RECT  88.344 19.949 91.53 20.039 ;
     RECT  96.624 19.913 101.034 20.039 ;
     RECT  102.24 19.949 102.798 20.039 ;
     RECT  53.028 20.039 55.638 20.075 ;
     RECT  59.868 20.039 64.098 20.075 ;
     RECT  65.736 20.039 66.006 20.075 ;
     RECT  88.344 20.039 89.097 20.075 ;
     RECT  92.376 19.949 94.554 20.075 ;
     RECT  97.128 20.039 100.71 20.075 ;
     RECT  92.88 20.075 94.554 20.093 ;
     RECT  100.692 20.075 100.71 20.093 ;
     RECT  102.24 20.039 102.366 20.093 ;
     RECT  45.396 20.039 45.954 20.111 ;
     RECT  73.872 20.039 74.97 20.111 ;
     RECT  97.128 20.075 99.897 20.111 ;
     RECT  56.607 20.039 59.094 20.141 ;
     RECT  28.764 20.039 29.697 20.183 ;
     RECT  30.636 20.039 33.354 20.183 ;
     RECT  65.736 20.075 65.754 20.183 ;
     RECT  2.415 20.039 27.99 20.189 ;
     RECT  51.156 19.997 52.218 20.219 ;
     RECT  67.14 19.913 68.994 20.219 ;
     RECT  72.396 20.039 72.897 20.219 ;
     RECT  85.608 20.039 86.49 20.219 ;
     RECT  97.92 20.111 99.897 20.219 ;
     RECT  28.944 20.183 29.697 20.267 ;
     RECT  45.396 20.111 45.897 20.267 ;
     RECT  56.607 20.141 57.042 20.267 ;
     RECT  67.14 20.219 68.598 20.267 ;
     RECT  72.576 20.219 72.897 20.267 ;
     RECT  78.207 19.997 78.297 20.267 ;
     RECT  88.92 20.075 89.097 20.267 ;
     RECT  93.996 20.093 94.497 20.267 ;
     RECT  99.807 20.219 99.897 20.267 ;
     RECT  105.207 19.997 105.297 20.267 ;
     RECT  110.607 19.997 110.697 20.267 ;
     RECT  116.007 19.997 116.55 20.267 ;
     RECT  56.772 20.267 57.042 20.285 ;
     RECT  60.084 20.075 63.99 20.285 ;
     RECT  30.996 20.183 33.354 20.309 ;
     RECT  93.996 20.267 94.014 20.309 ;
     RECT  97.92 20.219 98.622 20.309 ;
     RECT  102.348 20.093 102.366 20.309 ;
     RECT  48.456 19.661 49.158 20.333 ;
     RECT  2.415 20.189 27.846 20.345 ;
     RECT  31.464 20.309 33.354 20.345 ;
     RECT  51.156 20.219 51.57 20.345 ;
     RECT  81.792 19.949 82.674 20.345 ;
     RECT  2.415 20.345 27.378 20.381 ;
     RECT  42.732 19.949 44.622 20.381 ;
     RECT  51.372 20.345 51.57 20.381 ;
     RECT  56.772 20.285 56.79 20.381 ;
     RECT  62.316 20.285 63.99 20.381 ;
     RECT  68.184 20.267 68.598 20.381 ;
     RECT  44.568 20.381 44.622 20.417 ;
     RECT  51.552 20.381 51.57 20.417 ;
     RECT  88.92 20.267 88.938 20.417 ;
     RECT  89.892 20.039 91.242 20.417 ;
     RECT  57.96 20.141 59.094 20.429 ;
     RECT  39.492 19.949 41.922 20.453 ;
     RECT  44.604 20.417 44.622 20.453 ;
     RECT  39.492 20.453 40.662 20.477 ;
     RECT  39.492 20.477 40.554 20.489 ;
     RECT  79.308 19.913 81.018 20.489 ;
     RECT  63.288 20.381 63.99 20.525 ;
     RECT  24.984 20.381 27.378 20.534 ;
     RECT  97.92 20.309 98.154 20.534 ;
     RECT  80.532 20.489 81.018 20.579 ;
     RECT  91.044 20.417 91.242 20.615 ;
     RECT  41.472 20.453 41.922 20.651 ;
     RECT  89.892 20.417 89.91 20.651 ;
     RECT  25.02 20.534 25.578 20.687 ;
     RECT  95.58 19.913 95.598 20.687 ;
     RECT  45.396 20.267 45.414 20.723 ;
     RECT  83.556 19.997 84.078 20.723 ;
     RECT  28.944 20.267 29.574 20.759 ;
     RECT  53.028 20.075 55.206 20.759 ;
     RECT  75.924 19.769 76.626 20.759 ;
     RECT  97.128 20.111 97.146 20.804 ;
     RECT  34.164 19.949 38.502 20.813 ;
     RECT  62.316 20.381 62.442 20.849 ;
     RECT  60.084 20.285 61.506 20.861 ;
     RECT  81.792 20.345 82.35 20.885 ;
     RECT  25.02 20.687 25.038 20.909 ;
     RECT  81.9 20.885 82.35 20.921 ;
     RECT  84.816 19.949 84.834 20.957 ;
     RECT  91.044 20.615 91.062 20.993 ;
     RECT  34.164 20.813 37.206 21.029 ;
     RECT  71.136 20.039 71.154 21.046 ;
     RECT  38.196 20.813 38.502 21.074 ;
     RECT  42.732 20.381 43.65 21.074 ;
     RECT  58.572 20.429 59.094 21.074 ;
     RECT  70.992 21.046 71.154 21.074 ;
     RECT  98.136 20.534 98.154 21.119 ;
     RECT  83.916 20.723 84.078 21.149 ;
     RECT  85.608 20.219 85.626 21.155 ;
     RECT  34.2 21.029 37.206 21.191 ;
     RECT  79.308 20.489 79.326 21.191 ;
     RECT  34.344 21.191 37.206 21.227 ;
     RECT  82.332 20.921 82.35 21.227 ;
     RECT  41.58 20.651 41.922 21.263 ;
     RECT  86.4 20.219 86.418 21.263 ;
     RECT  63.468 20.525 63.99 21.299 ;
     RECT  31.932 20.345 33.354 21.344 ;
     RECT  68.184 20.381 68.202 21.344 ;
     RECT  38.196 21.074 38.322 21.389 ;
     RECT  49.14 20.333 49.158 21.389 ;
     RECT  61.416 20.861 61.506 21.389 ;
     RECT  63.612 21.299 63.99 21.425 ;
     RECT  34.344 21.227 36.99 21.437 ;
     RECT  62.424 20.849 62.442 21.437 ;
     RECT  42.732 21.074 43.578 21.461 ;
     RECT  67.14 20.267 67.158 21.461 ;
     RECT  31.932 21.344 32.058 21.497 ;
     RECT  63.972 21.425 63.99 21.497 ;
     RECT  72.576 20.267 72.594 21.497 ;
     RECT  116.532 20.267 116.55 21.505 ;
     RECT  117.324 6.547 121.554 21.505 ;
     RECT  75.924 20.759 76.374 21.533 ;
     RECT  35.136 21.437 36.99 21.569 ;
     RECT  80.532 20.579 80.766 21.569 ;
     RECT  83.916 21.149 83.934 21.659 ;
     RECT  116.532 21.505 121.554 21.659 ;
     RECT  39.492 20.489 39.726 21.677 ;
     RECT  116.532 21.659 116.55 21.677 ;
     RECT  32.04 21.497 32.058 21.695 ;
     RECT  74.556 20.111 74.934 21.695 ;
     RECT  2.415 20.381 23.958 21.787 ;
     RECT  1.872 21.787 23.958 22.027 ;
     RECT  1.656 22.027 23.958 22.464 ;
     RECT  27.36 20.534 27.378 22.464 ;
     RECT  29.556 20.759 29.574 22.464 ;
     RECT  33.336 21.344 33.354 22.464 ;
     RECT  34.344 21.437 34.362 22.464 ;
     RECT  35.136 21.569 35.622 22.464 ;
     RECT  36.396 21.569 36.99 22.464 ;
     RECT  38.304 21.389 38.322 22.464 ;
     RECT  39.492 21.677 39.51 22.464 ;
     RECT  41.58 21.263 41.598 22.464 ;
     RECT  42.732 21.461 42.858 22.464 ;
     RECT  53.532 20.759 55.206 22.464 ;
     RECT  58.572 21.074 58.986 22.464 ;
     RECT  60.084 20.861 60.102 22.464 ;
     RECT  61.488 21.389 61.506 22.464 ;
     RECT  70.992 21.074 71.01 22.464 ;
     RECT  74.556 21.695 74.574 22.464 ;
     RECT  75.924 21.533 75.942 22.464 ;
     RECT  80.748 21.569 80.766 22.464 ;
     RECT  117.324 21.659 121.554 22.464 ;
     RECT  1.656 22.464 121.554 23.629 ;
     RECT  1.008 23.629 121.554 26.381 ;
     RECT  1.008 26.381 121.497 27.203 ;
     RECT  1.008 27.203 2.826 28.147 ;
     RECT  3.564 27.203 121.497 28.147 ;
     RECT  1.008 28.147 121.497 31.133 ;
     RECT  1.008 31.133 120.438 31.229 ;
     RECT  1.008 31.229 120.366 32.669 ;
     RECT  1.008 32.669 118.026 32.765 ;
     RECT  118.8 32.669 120.366 33.149 ;
     RECT  118.8 33.149 120.078 33.341 ;
     RECT  0.216 32.809 0.234 33.421 ;
     RECT  1.008 32.765 117.288 33.421 ;
     RECT  0.216 33.421 117.288 33.583 ;
     RECT  119.088 33.341 120.078 34.493 ;
     RECT  119.088 34.493 120.042 34.589 ;
     RECT  0.216 33.583 117.414 34.685 ;
     RECT  119.088 34.589 119.862 34.685 ;
     RECT  119.736 34.685 119.862 34.763 ;
     RECT  119.772 34.763 119.862 35.707 ;
     RECT  118.584 34.699 118.602 35.933 ;
     RECT  119.628 35.707 119.862 36.049 ;
     RECT  119.628 36.049 119.97 36.283 ;
     RECT  0.216 34.685 0.234 36.617 ;
     RECT  119.556 36.283 119.97 36.689 ;
     RECT  1.008 34.685 117.414 36.859 ;
     RECT  119.556 36.689 119.754 36.923 ;
     RECT  119.556 36.923 119.718 36.931 ;
     RECT  119.088 36.931 119.718 37.021 ;
     RECT  118.584 37.021 119.718 37.085 ;
     RECT  119.088 37.085 119.718 37.181 ;
     RECT  1.008 36.859 117.45 37.399 ;
     RECT  0.54 37.399 117.45 37.435 ;
     RECT  119.556 37.181 119.718 37.741 ;
     RECT  0.216 37.435 118.026 37.915 ;
     RECT  0.216 37.915 118.062 38.045 ;
     RECT  119.556 37.741 119.826 38.101 ;
     RECT  119.088 38.101 119.826 38.209 ;
     RECT  119.088 38.209 119.862 38.407 ;
     RECT  0.252 38.045 118.062 38.429 ;
     RECT  119.088 38.407 120.078 38.543 ;
     RECT  1.008 38.429 118.062 38.551 ;
     RECT  119.088 38.543 120.006 38.551 ;
     RECT  1.008 38.551 120.006 38.849 ;
     RECT  0.252 38.429 0.27 38.983 ;
     RECT  118.584 38.849 120.006 39.209 ;
     RECT  0.216 38.983 0.27 39.289 ;
     RECT  1.008 38.849 117.414 39.289 ;
     RECT  118.584 39.209 119.79 39.659 ;
     RECT  119.088 39.659 119.79 39.965 ;
     RECT  0.216 39.289 117.414 40.163 ;
     RECT  119.736 39.965 119.79 40.261 ;
     RECT  119.736 40.261 119.898 40.289 ;
     RECT  0.252 40.163 117.414 40.325 ;
     RECT  0.288 40.325 117.414 40.637 ;
     RECT  119.88 40.289 119.898 40.711 ;
     RECT  1.008 40.637 117.414 40.801 ;
     RECT  119.88 40.711 120.114 40.829 ;
     RECT  1.008 40.801 117.45 41.021 ;
     RECT  119.88 40.829 120.006 41.107 ;
     RECT  119.736 41.107 120.006 41.369 ;
     RECT  119.736 41.369 119.79 41.467 ;
     RECT  0.216 41.179 0.27 41.501 ;
     RECT  119.592 41.467 119.79 41.549 ;
     RECT  119.592 41.549 119.61 41.675 ;
     RECT  119.52 42.139 119.538 42.529 ;
     RECT  118.584 41.917 118.602 42.565 ;
     RECT  119.52 42.529 119.97 42.565 ;
     RECT  0.216 41.501 0.234 42.601 ;
     RECT  118.584 42.565 119.97 42.629 ;
     RECT  0.216 42.601 0.27 42.755 ;
     RECT  0.252 42.755 0.27 43.295 ;
     RECT  118.584 42.629 119.754 43.421 ;
     RECT  119.088 43.421 119.754 43.501 ;
     RECT  119.088 43.501 119.79 43.997 ;
     RECT  1.008 41.021 117.414 44.041 ;
     RECT  119.736 43.997 119.79 44.041 ;
     RECT  119.736 44.041 120.006 44.177 ;
     RECT  1.008 44.041 117.45 44.285 ;
     RECT  1.008 44.285 117.414 44.725 ;
     RECT  119.736 44.177 119.898 44.789 ;
     RECT  0.54 44.725 117.414 44.957 ;
     RECT  118.584 44.419 118.602 45.053 ;
     RECT  1.008 44.957 117.414 45.121 ;
     RECT  1.008 45.121 117.45 45.341 ;
     RECT  119.736 44.789 119.754 45.571 ;
     RECT  119.088 45.571 119.754 45.661 ;
     RECT  119.088 45.661 119.898 46.205 ;
     RECT  119.556 46.205 119.898 46.229 ;
     RECT  119.736 46.229 119.898 46.409 ;
     RECT  119.952 46.507 120.078 46.607 ;
     RECT  1.008 45.341 117.414 46.741 ;
     RECT  119.952 46.607 119.97 47.075 ;
     RECT  1.008 46.741 117.45 47.261 ;
     RECT  118.584 46.813 118.602 47.416 ;
     RECT  118.584 47.416 119.106 47.695 ;
     RECT  118.584 47.695 119.754 47.857 ;
     RECT  118.584 47.857 120.294 47.933 ;
     RECT  1.008 47.261 117.414 48.221 ;
     RECT  118.584 47.933 120.222 48.425 ;
     RECT  118.62 48.425 120.222 48.509 ;
     RECT  119.052 48.509 120.222 49.085 ;
     RECT  119.628 49.085 120.222 49.277 ;
     RECT  119.628 49.277 119.718 49.541 ;
     RECT  119.7 49.541 119.718 49.949 ;
     RECT  118.584 49.513 118.602 50.587 ;
     RECT  118.584 50.587 119.142 50.683 ;
     RECT  118.584 50.683 119.538 51.005 ;
     RECT  119.124 51.005 119.538 51.067 ;
     RECT  1.044 48.221 117.414 51.115 ;
     RECT  119.124 51.067 119.61 51.467 ;
     RECT  1.044 51.115 117.45 51.643 ;
     RECT  139.896 51.691 139.914 51.773 ;
     RECT  1.044 51.643 118.026 51.835 ;
     RECT  141.372 51.781 141.39 52.061 ;
     RECT  1.044 51.835 118.566 52.219 ;
     RECT  119.52 51.467 119.61 52.219 ;
     RECT  1.044 52.219 119.61 52.447 ;
     RECT  1.044 52.447 119.754 52.547 ;
     RECT  119.088 52.547 119.754 52.591 ;
     RECT  119.088 52.591 119.898 52.861 ;
     RECT  119.088 52.861 119.934 53.015 ;
     RECT  119.088 53.015 119.79 53.321 ;
     RECT  1.044 52.547 118.026 53.527 ;
     RECT  119.448 53.321 119.79 53.869 ;
     RECT  1.044 53.527 118.602 54.067 ;
     RECT  1.044 54.067 118.638 54.269 ;
     RECT  119.448 53.869 119.934 54.331 ;
     RECT  1.044 54.269 118.026 55.111 ;
     RECT  119.124 54.331 119.934 55.111 ;
     RECT  1.044 55.111 119.934 55.715 ;
     RECT  1.044 55.715 119.754 56.021 ;
     RECT  1.044 56.021 118.674 56.525 ;
     RECT  119.628 56.021 119.754 56.641 ;
     RECT  119.628 56.641 119.934 56.767 ;
     RECT  119.628 56.767 120.078 56.827 ;
     RECT  119.556 56.827 120.078 56.867 ;
     RECT  118.584 56.525 118.674 56.923 ;
     RECT  119.556 56.867 119.754 56.923 ;
     RECT  1.044 56.525 117.45 57.245 ;
     RECT  118.584 56.923 119.754 57.713 ;
     RECT  118.584 57.713 118.674 58.019 ;
     RECT  119.52 57.713 119.754 58.415 ;
     RECT  119.7 58.415 119.754 59.161 ;
     RECT  119.7 59.161 119.79 59.227 ;
     RECT  118.584 58.019 118.602 59.305 ;
     RECT  119.556 59.227 119.79 59.305 ;
     RECT  118.584 59.305 119.79 59.341 ;
     RECT  118.584 59.341 119.97 59.357 ;
     RECT  119.556 59.357 119.97 59.459 ;
     RECT  118.584 59.357 118.638 59.567 ;
     RECT  1.044 57.245 117.414 60.125 ;
     RECT  119.844 59.459 119.934 60.277 ;
     RECT  119.844 60.277 120.078 60.413 ;
     RECT  118.62 59.567 118.638 60.509 ;
     RECT  119.772 60.511 119.79 60.763 ;
     RECT  1.044 60.125 117.378 60.853 ;
     RECT  119.628 60.763 119.79 60.955 ;
     RECT  119.16 60.955 119.79 61.691 ;
     RECT  119.16 61.691 119.646 61.735 ;
     RECT  1.044 60.853 117.414 61.763 ;
     RECT  3.492 61.763 117.414 61.819 ;
     RECT  118.584 61.735 119.646 61.819 ;
     RECT  3.492 61.819 119.646 62.069 ;
     RECT  119.196 62.069 119.646 62.609 ;
     RECT  119.628 62.609 119.646 62.699 ;
     RECT  1.044 61.763 2.697 62.815 ;
     RECT  3.492 62.069 118.026 62.815 ;
     RECT  1.044 62.815 118.026 62.969 ;
     RECT  3.492 62.969 118.026 63.005 ;
     RECT  3.492 63.005 117.288 63.528 ;
     RECT  39.024 63.528 39.042 63.887 ;
     RECT  1.044 62.969 2.697 63.917 ;
     RECT  2.268 63.917 2.697 64.201 ;
     RECT  3.492 63.528 24.75 64.201 ;
     RECT  1.044 63.917 1.134 64.229 ;
     RECT  26.352 63.528 26.37 64.327 ;
     RECT  27.36 63.528 27.81 64.327 ;
     RECT  26.352 64.327 27.81 64.399 ;
     RECT  1.08 64.229 1.134 64.499 ;
     RECT  33.156 63.528 33.174 64.699 ;
     RECT  42.48 64.669 42.498 64.705 ;
     RECT  25.848 64.399 27.81 64.987 ;
     RECT  28.548 64.741 28.566 64.987 ;
     RECT  33.156 64.699 33.642 65.275 ;
     RECT  2.268 64.201 24.75 65.371 ;
     RECT  25.848 64.987 28.566 65.371 ;
     RECT  25.848 65.371 28.89 65.551 ;
     RECT  32.256 64.651 32.274 65.551 ;
     RECT  25.74 65.551 28.89 65.593 ;
     RECT  35.172 65.551 35.19 65.593 ;
     RECT  30.816 65.467 30.834 65.641 ;
     RECT  38.376 65.275 38.394 65.707 ;
     RECT  30.816 65.641 31.122 65.713 ;
     RECT  35.007 65.593 35.19 65.713 ;
     RECT  25.74 65.593 29.697 65.749 ;
     RECT  33.156 65.275 34.002 65.785 ;
     RECT  35.007 65.713 35.802 65.785 ;
     RECT  38.376 65.707 38.79 65.821 ;
     RECT  40.407 65.593 40.497 65.863 ;
     RECT  45.807 65.593 45.897 65.863 ;
     RECT  51.207 65.593 51.297 65.863 ;
     RECT  56.607 65.593 56.697 65.863 ;
     RECT  62.007 65.593 62.097 65.863 ;
     RECT  67.407 65.593 67.497 65.863 ;
     RECT  72.807 65.593 72.897 65.863 ;
     RECT  78.207 65.593 78.297 65.863 ;
     RECT  83.607 65.593 83.697 65.863 ;
     RECT  89.007 65.593 89.097 65.863 ;
     RECT  94.407 65.593 94.497 65.863 ;
     RECT  99.807 65.593 99.897 65.863 ;
     RECT  105.207 65.593 105.297 65.863 ;
     RECT  110.607 65.593 110.697 65.863 ;
     RECT  116.007 65.593 116.097 65.863 ;
     RECT  2.268 65.371 24.786 66.019 ;
     RECT  25.668 65.749 29.697 66.019 ;
     RECT  2.268 66.019 29.697 66.091 ;
     RECT  30.816 65.713 31.41 66.091 ;
     RECT  33.156 65.785 35.802 66.091 ;
     RECT  36.648 63.528 36.666 66.091 ;
     RECT  2.268 66.091 29.934 66.289 ;
     RECT  30.78 66.091 31.41 66.325 ;
     RECT  2.268 66.289 30.006 66.379 ;
     RECT  30.78 66.325 31.446 66.379 ;
     RECT  32.22 65.551 32.274 66.475 ;
     RECT  33.156 66.091 36.666 66.475 ;
     RECT  2.268 66.379 31.446 66.559 ;
     RECT  32.22 66.475 36.666 66.559 ;
     RECT  2.268 66.559 36.738 66.595 ;
     RECT  2.268 66.595 37.098 66.631 ;
     RECT  2.268 66.631 37.638 67.027 ;
     RECT  38.376 65.821 39.006 67.027 ;
     RECT  40.215 65.863 40.497 67.627 ;
     RECT  40.104 67.627 40.497 69.019 ;
     RECT  2.268 67.027 39.006 72.499 ;
     RECT  40.104 69.019 40.914 72.499 ;
     RECT  2.268 72.499 40.914 72.833 ;
     RECT  41.904 64.705 42.498 72.931 ;
     RECT  41.904 72.931 42.642 73.003 ;
     RECT  41.904 73.003 42.822 73.133 ;
     RECT  41.904 73.133 42.75 73.277 ;
     RECT  2.415 72.833 40.914 74.045 ;
     RECT  10.26 74.045 40.914 74.765 ;
     RECT  2.415 74.045 9.486 74.929 ;
     RECT  10.26 74.765 39.186 74.929 ;
     RECT  41.904 73.277 42.642 75.271 ;
     RECT  2.415 74.929 39.186 75.731 ;
     RECT  40.104 74.765 40.914 75.739 ;
     RECT  41.76 75.271 42.642 75.739 ;
     RECT  3.492 75.731 39.186 75.767 ;
     RECT  38.772 75.767 39.186 76.171 ;
     RECT  40.104 75.739 42.642 76.171 ;
     RECT  38.772 76.171 42.642 76.781 ;
     RECT  3.492 75.767 37.674 76.811 ;
     RECT  12.132 76.811 37.674 76.847 ;
     RECT  3.492 76.811 11.142 76.919 ;
     RECT  12.132 76.847 35.838 77.009 ;
     RECT  12.276 77.009 35.838 77.153 ;
     RECT  3.492 76.919 8.838 77.189 ;
     RECT  12.528 77.153 35.838 77.189 ;
     RECT  7.596 77.189 8.838 77.279 ;
     RECT  45.615 65.863 45.897 77.323 ;
     RECT  12.528 77.189 33.966 77.351 ;
     RECT  3.492 77.189 6.606 77.459 ;
     RECT  7.815 77.279 8.442 77.549 ;
     RECT  9.648 76.919 11.106 77.549 ;
     RECT  3.492 77.459 5.382 77.585 ;
     RECT  6.192 77.459 6.606 77.585 ;
     RECT  34.704 77.189 35.838 77.629 ;
     RECT  36.576 76.847 37.674 77.629 ;
     RECT  3.492 77.585 5.166 77.657 ;
     RECT  6.192 77.585 6.534 77.657 ;
     RECT  12.528 77.351 33.678 77.789 ;
     RECT  6.444 77.657 6.534 77.819 ;
     RECT  34.704 77.629 37.674 77.827 ;
     RECT  6.444 77.819 6.462 77.855 ;
     RECT  39.168 76.781 42.642 77.863 ;
     RECT  34.704 77.827 38.178 77.947 ;
     RECT  26.352 77.789 33.678 78.097 ;
     RECT  34.704 77.947 38.322 78.097 ;
     RECT  26.352 78.097 38.322 78.331 ;
     RECT  39.06 77.863 42.642 78.331 ;
     RECT  3.492 77.657 4.878 79.517 ;
     RECT  26.352 78.331 42.642 79.519 ;
     RECT  47.16 79.411 47.178 79.709 ;
     RECT  26.352 79.519 42.786 79.745 ;
     RECT  45.216 77.323 45.897 79.753 ;
     RECT  12.528 77.789 25.506 79.819 ;
     RECT  26.352 79.745 38.754 79.819 ;
     RECT  44.1 79.717 44.118 80.015 ;
     RECT  45 79.753 45.897 80.221 ;
     RECT  12.528 79.819 38.754 80.285 ;
     RECT  39.528 79.745 42.786 80.321 ;
     RECT  3.672 79.517 4.878 81.239 ;
     RECT  4.86 81.239 4.878 81.329 ;
     RECT  26.352 80.285 38.754 81.337 ;
     RECT  39.6 80.321 42.786 81.337 ;
     RECT  12.528 80.285 25.506 81.401 ;
     RECT  47.664 79.717 47.682 81.571 ;
     RECT  47.124 81.571 47.682 81.841 ;
     RECT  47.124 81.841 47.79 81.905 ;
     RECT  44.712 80.221 45.897 81.949 ;
     RECT  13.215 81.401 25.506 81.965 ;
     RECT  47.664 81.905 47.79 81.985 ;
     RECT  48.672 79.753 48.69 81.985 ;
     RECT  44.712 81.949 46.206 82.111 ;
     RECT  14.256 81.965 25.506 82.205 ;
     RECT  25.488 82.205 25.506 82.267 ;
     RECT  26.352 81.337 42.786 82.267 ;
     RECT  1.116 64.499 1.134 82.445 ;
     RECT  14.256 82.205 24.642 82.445 ;
     RECT  44.712 82.111 46.926 82.445 ;
     RECT  14.256 82.445 22.626 82.517 ;
     RECT  14.256 82.517 22.302 82.589 ;
     RECT  10.584 77.549 10.926 82.949 ;
     RECT  19.764 82.589 22.302 83.021 ;
     RECT  43.884 81.481 43.902 83.219 ;
     RECT  23.364 82.445 24.642 83.227 ;
     RECT  25.488 82.267 42.786 83.227 ;
     RECT  14.256 82.589 18.897 83.363 ;
     RECT  18.216 83.363 18.897 83.399 ;
     RECT  3.672 81.239 4.122 83.501 ;
     RECT  47.664 81.985 48.69 83.641 ;
     RECT  46.908 82.445 46.926 83.839 ;
     RECT  47.664 83.641 48.834 83.839 ;
     RECT  18.615 83.399 18.897 83.851 ;
     RECT  44.712 82.445 45.897 83.867 ;
     RECT  14.256 83.363 16.974 83.885 ;
     RECT  10.584 82.949 10.602 83.903 ;
     RECT  14.256 83.885 16.182 83.939 ;
     RECT  2.415 75.731 2.697 83.987 ;
     RECT  7.815 77.549 8.097 83.987 ;
     RECT  13.215 81.965 13.497 83.987 ;
     RECT  45.324 83.867 45.897 83.987 ;
     RECT  51.015 65.863 51.297 83.987 ;
     RECT  56.415 65.863 56.697 83.987 ;
     RECT  61.815 65.863 62.097 83.987 ;
     RECT  67.215 65.863 67.497 83.987 ;
     RECT  72.615 65.863 72.897 83.987 ;
     RECT  78.015 65.863 78.297 83.987 ;
     RECT  83.415 65.863 83.697 83.987 ;
     RECT  88.815 65.863 89.097 83.987 ;
     RECT  94.215 65.863 94.497 83.987 ;
     RECT  99.615 65.863 99.897 83.987 ;
     RECT  105.015 65.863 105.297 83.987 ;
     RECT  110.415 65.863 110.697 83.987 ;
     RECT  115.815 65.863 116.097 83.987 ;
     RECT  121.215 31.133 121.497 83.987 ;
     RECT  126.615 2.413 126.897 83.987 ;
     RECT  132.015 2.413 132.297 83.987 ;
     RECT  137.415 2.413 137.697 83.987 ;
     RECT  45.324 83.987 45.774 84.065 ;
     RECT  46.908 83.839 48.834 84.065 ;
     RECT  18.615 83.851 18.954 84.125 ;
     RECT  45.615 84.065 45.774 84.137 ;
     RECT  46.98 84.065 48.834 84.137 ;
     RECT  18.615 84.125 18.81 84.221 ;
     RECT  2.415 83.987 2.505 84.257 ;
     RECT  7.815 83.987 7.905 84.257 ;
     RECT  13.215 83.987 13.305 84.257 ;
     RECT  18.615 84.221 18.705 84.257 ;
     RECT  45.615 84.137 45.705 84.257 ;
     RECT  51.015 83.987 51.105 84.257 ;
     RECT  56.415 83.987 56.505 84.257 ;
     RECT  61.815 83.987 61.905 84.257 ;
     RECT  67.215 83.987 67.305 84.257 ;
     RECT  72.615 83.987 72.705 84.257 ;
     RECT  78.015 83.987 78.105 84.257 ;
     RECT  83.415 83.987 83.505 84.257 ;
     RECT  88.815 83.987 88.905 84.257 ;
     RECT  94.215 83.987 94.305 84.257 ;
     RECT  99.615 83.987 99.705 84.257 ;
     RECT  105.015 83.987 105.105 84.257 ;
     RECT  110.415 83.987 110.505 84.257 ;
     RECT  115.815 83.987 115.905 84.257 ;
     RECT  121.215 83.987 121.305 84.257 ;
     RECT  126.615 83.987 126.705 84.257 ;
     RECT  132.015 83.987 132.105 84.257 ;
     RECT  137.415 83.987 137.505 84.257 ;
     RECT  47.304 84.137 48.834 84.299 ;
     RECT  23.364 83.227 42.786 84.407 ;
     RECT  20.268 83.021 22.302 84.605 ;
     RECT  4.104 83.501 4.122 84.641 ;
     RECT  14.256 83.939 15.894 84.653 ;
     RECT  14.256 84.653 14.994 84.677 ;
     RECT  15.804 84.653 15.894 84.713 ;
     RECT  23.364 84.407 23.706 84.749 ;
     RECT  21.6 84.605 22.302 84.794 ;
     RECT  21.6 84.794 21.618 84.797 ;
     RECT  20.268 84.605 20.862 85.181 ;
     RECT  16.956 83.885 16.974 85.217 ;
     RECT  20.268 85.181 20.286 85.253 ;
     RECT  15.876 84.713 15.894 85.277 ;
     RECT  14.256 84.677 14.274 85.289 ;
     RECT  23.688 84.749 23.706 85.517 ;
     RECT  24.48 84.407 42.786 86.268 ;
     RECT  47.52 84.299 48.834 86.268 ;
     RECT  26.136 86.268 26.154 86.297 ;
     RECT  29.736 86.268 29.754 86.297 ;
    LAYER M4 ;
     RECT  0.156 32.256 0.281 42.792 ;
     RECT  0.227 50.592 1.465 50.616 ;
     RECT  1.645 22.032 1.861 22.056 ;
     RECT  1.645 49.584 1.861 49.608 ;
     RECT  1.465 50.592 1.861 50.952 ;
     RECT  0.997 48.192 1.957 48.216 ;
     RECT  2.053 18.48 2.101 18.504 ;
     RECT  1.069 25.008 2.149 25.032 ;
     RECT  1.033 26.352 2.149 26.376 ;
     RECT  1.957 47.664 2.149 48.216 ;
     RECT  2.101 59.184 2.185 59.208 ;
     RECT  2.149 25.008 2.197 26.376 ;
     RECT  2.149 71.472 2.197 71.496 ;
     RECT  2.101 18.48 2.245 19.32 ;
     RECT  0.281 32.256 2.293 42.36 ;
     RECT  1.861 49.584 2.365 50.952 ;
     RECT  1.681 52.032 2.365 52.296 ;
     RECT  2.245 18.48 2.408 19.56 ;
     RECT  1.861 21.792 2.408 22.056 ;
     RECT  2.197 24.384 2.408 26.376 ;
     RECT  2.293 31.92 2.408 42.36 ;
     RECT  0.156 44.064 2.408 45.096 ;
     RECT  2.149 46.848 2.408 48.216 ;
     RECT  2.365 49.488 2.408 50.952 ;
     RECT  2.365 52.032 2.408 52.488 ;
     RECT  2.365 58.128 2.408 58.152 ;
     RECT  2.185 59.184 2.408 59.592 ;
     RECT  2.113 60.576 2.408 60.6 ;
     RECT  2.293 62.16 2.408 62.184 ;
     RECT  1.609 63.888 2.408 63.912 ;
     RECT  2.245 69.312 2.408 69.336 ;
     RECT  2.197 71.472 2.408 71.976 ;
     RECT  1.105 82.416 2.408 82.44 ;
     RECT  2.408 2.148 2.512 84.252 ;
     RECT  2.512 2.418 2.704 83.982 ;
     RECT  2.704 11.28 2.909 14.904 ;
     RECT  2.704 46.752 3.011 50.952 ;
     RECT  2.704 58.128 3.089 61.176 ;
     RECT  2.909 14.208 3.395 14.904 ;
     RECT  3.089 58.368 3.443 61.176 ;
     RECT  2.704 74.688 3.629 75.432 ;
     RECT  3.685 76.704 3.697 76.728 ;
     RECT  2.909 11.28 3.701 13.032 ;
     RECT  3.629 75.216 3.731 75.432 ;
     RECT  2.704 10.176 3.733 10.2 ;
     RECT  3.701 11.28 3.733 12.744 ;
     RECT  2.704 9.072 3.769 9.144 ;
     RECT  3.697 76.704 3.772 76.968 ;
     RECT  3.769 8.976 3.805 9.144 ;
     RECT  3.733 10.176 3.805 12.744 ;
     RECT  2.704 83.472 3.829 83.496 ;
     RECT  3.011 46.848 3.877 50.952 ;
     RECT  2.704 16.08 3.913 17.064 ;
     RECT  2.704 18.192 3.913 26.808 ;
     RECT  2.704 68.208 3.925 71.928 ;
     RECT  2.704 72.912 3.925 73.512 ;
     RECT  2.704 52.224 4.021 52.584 ;
     RECT  2.704 53.952 4.021 57.048 ;
     RECT  3.805 8.976 4.061 12.744 ;
     RECT  2.704 62.16 4.165 63.912 ;
     RECT  3.925 68.208 4.165 73.512 ;
     RECT  2.704 43.344 4.213 45.72 ;
     RECT  4.213 43.344 4.237 45.816 ;
     RECT  2.704 29.04 4.309 42.216 ;
     RECT  4.237 43.296 4.309 45.816 ;
     RECT  3.443 58.368 4.405 60.6 ;
     RECT  4.165 61.584 4.405 63.912 ;
     RECT  2.704 65.136 4.549 66.888 ;
     RECT  4.165 68.208 4.549 74.136 ;
     RECT  4.057 75.648 4.565 75.672 ;
     RECT  4.061 11.52 4.643 12.744 ;
     RECT  3.913 16.08 4.669 27.336 ;
     RECT  4.309 29.04 4.669 45.816 ;
     RECT  3.395 14.88 4.693 14.904 ;
     RECT  4.021 52.224 4.777 57.048 ;
     RECT  4.669 16.08 4.921 45.816 ;
     RECT  2.704 82.416 4.981 82.488 ;
     RECT  3.829 83.472 4.981 83.544 ;
     RECT  4.777 52.176 4.993 57.048 ;
     RECT  4.405 58.368 4.993 63.912 ;
     RECT  4.693 14.784 5.029 14.904 ;
     RECT  4.921 15.936 5.029 45.816 ;
     RECT  2.704 79.488 5.029 79.512 ;
     RECT  5.029 14.784 5.077 45.816 ;
     RECT  4.549 65.136 5.137 74.136 ;
     RECT  5.077 14.688 5.317 45.816 ;
     RECT  3.877 46.848 5.317 51.192 ;
     RECT  4.993 52.176 5.533 63.912 ;
     RECT  5.533 52.176 5.557 64.104 ;
     RECT  5.137 65.136 5.557 74.664 ;
     RECT  5.317 14.688 5.677 51.192 ;
     RECT  5.557 52.176 5.677 74.664 ;
     RECT  5.173 75.792 5.701 75.96 ;
     RECT  3.772 76.944 5.701 76.968 ;
     RECT  4.061 8.976 5.852 10.392 ;
     RECT  4.643 11.52 5.857 12.552 ;
     RECT  5.701 75.792 5.861 76.968 ;
     RECT  5.852 8.448 5.939 10.392 ;
     RECT  5.677 14.688 5.965 74.664 ;
     RECT  4.981 82.416 6.181 83.544 ;
     RECT  6.085 13.68 6.277 13.704 ;
     RECT  5.965 14.688 6.277 74.952 ;
     RECT  6.277 13.68 6.293 74.952 ;
     RECT  5.939 8.736 6.689 10.392 ;
     RECT  6.689 8.832 6.721 10.392 ;
     RECT  5.029 79.488 6.757 80.088 ;
     RECT  5.857 11.424 6.853 12.552 ;
     RECT  6.293 13.92 6.853 74.952 ;
     RECT  5.861 75.936 6.853 76.968 ;
     RECT  6.721 8.832 6.901 10.44 ;
     RECT  6.853 11.424 6.901 12.84 ;
     RECT  6.853 13.92 7.237 76.968 ;
     RECT  6.373 84.816 7.429 84.84 ;
     RECT  6.901 8.832 7.585 12.84 ;
     RECT  7.237 13.92 7.585 77.304 ;
     RECT  6.181 82.416 7.621 83.592 ;
     RECT  3.733 3.888 7.808 3.912 ;
     RECT  5.461 5.76 7.808 5.784 ;
     RECT  7.585 8.832 7.808 77.304 ;
     RECT  6.757 79.488 7.808 80.664 ;
     RECT  7.621 82.272 7.808 83.592 ;
     RECT  7.429 84.816 7.808 85.224 ;
     RECT  7.808 2.148 7.912 85.224 ;
     RECT  7.912 2.418 8.104 85.224 ;
     RECT  8.104 65.712 8.281 77.544 ;
     RECT  8.281 65.712 9.173 77.4 ;
     RECT  8.104 8.496 9.301 64.728 ;
     RECT  9.173 65.712 9.301 74.616 ;
     RECT  9.173 75.792 9.461 77.4 ;
     RECT  9.301 8.496 9.713 74.616 ;
     RECT  8.104 5.76 10.021 5.784 ;
     RECT  10.021 5.76 10.261 6.696 ;
     RECT  9.713 8.88 10.361 74.616 ;
     RECT  8.104 3.888 10.405 3.912 ;
     RECT  8.104 84.816 10.549 85.224 ;
     RECT  10.361 8.976 10.933 74.616 ;
     RECT  8.104 79.488 11.317 80.664 ;
     RECT  10.549 84.816 11.893 85.32 ;
     RECT  10.933 8.976 12.373 75.528 ;
     RECT  12.373 8.784 12.589 75.528 ;
     RECT  10.405 3.888 12.901 4.44 ;
     RECT  12.901 3.888 12.949 4.776 ;
     RECT  10.261 5.76 12.949 7.272 ;
     RECT  11.317 79.488 13.045 80.808 ;
     RECT  12.949 3.888 13.093 7.272 ;
     RECT  8.104 2.736 13.208 2.76 ;
     RECT  13.093 3.888 13.208 7.416 ;
     RECT  12.589 8.496 13.208 75.528 ;
     RECT  9.461 76.752 13.208 77.4 ;
     RECT  13.045 79.008 13.208 80.808 ;
     RECT  8.104 82.272 13.208 83.592 ;
     RECT  11.893 84.72 13.208 85.32 ;
     RECT  13.208 2.148 13.312 85.32 ;
     RECT  13.312 2.418 13.504 85.32 ;
     RECT  13.504 76.752 14.581 77.4 ;
     RECT  13.504 2.736 14.785 75 ;
     RECT  14.581 76.464 14.785 77.4 ;
     RECT  11.365 1.104 14.869 1.128 ;
     RECT  13.504 78.768 15.001 85.32 ;
     RECT  15.001 78.48 15.109 85.32 ;
     RECT  14.785 2.736 15.505 77.4 ;
     RECT  15.109 78.384 15.505 85.32 ;
     RECT  15.505 2.736 15.877 85.32 ;
     RECT  14.869 1.056 16.309 1.128 ;
     RECT  16.309 1.056 17.077 1.656 ;
     RECT  15.877 2.736 17.077 85.464 ;
     RECT  17.077 1.056 17.269 85.464 ;
     RECT  17.269 1.056 17.561 86.232 ;
     RECT  17.561 1.056 18.608 62.04 ;
     RECT  17.561 63.072 18.608 86.232 ;
     RECT  18.608 1.056 18.904 86.232 ;
     RECT  18.904 63.264 19.757 86.232 ;
     RECT  19.757 63.312 19.829 86.232 ;
     RECT  18.904 1.056 19.868 62.04 ;
     RECT  19.868 1.056 19.955 62.136 ;
     RECT  19.955 1.056 21.397 61.944 ;
     RECT  19.829 63.504 22.165 86.232 ;
     RECT  21.397 1.056 22.213 62.136 ;
     RECT  22.165 63.264 22.213 86.232 ;
     RECT  22.213 1.056 22.381 86.232 ;
     RECT  22.381 0.144 25.553 86.232 ;
     RECT  25.553 0.192 27.587 86.232 ;
     RECT  27.587 0.576 27.731 86.232 ;
     RECT  27.731 1.008 29.005 86.232 ;
     RECT  29.005 0.576 29.173 86.232 ;
     RECT  29.173 0.288 29.843 86.232 ;
     RECT  29.843 1.056 30.803 86.232 ;
     RECT  30.803 1.056 31.409 70.632 ;
     RECT  31.409 0.24 31.453 70.632 ;
     RECT  31.453 0.144 31.763 70.632 ;
     RECT  31.763 67.44 31.849 70.632 ;
     RECT  30.803 71.712 31.849 86.232 ;
     RECT  31.763 0.144 32.785 66.408 ;
     RECT  31.849 67.44 32.785 86.232 ;
     RECT  32.785 0.144 35.273 86.232 ;
     RECT  35.273 0.144 36.137 74.184 ;
     RECT  36.137 0.192 36.533 74.184 ;
     RECT  35.273 75.168 36.569 86.232 ;
     RECT  36.533 0.192 36.677 74.136 ;
     RECT  36.677 0.192 37.073 73.752 ;
     RECT  37.073 0.192 37.181 73.416 ;
     RECT  37.181 71.472 37.613 73.416 ;
     RECT  37.181 0.192 37.973 70.344 ;
     RECT  37.973 0.24 38.291 70.344 ;
     RECT  36.569 75.264 38.329 86.232 ;
     RECT  38.291 67.44 38.333 70.344 ;
     RECT  38.333 70.08 38.701 70.344 ;
     RECT  38.333 67.44 38.801 69.048 ;
     RECT  38.329 74.736 38.801 86.232 ;
     RECT  37.613 71.472 38.869 72.888 ;
     RECT  38.801 74.736 38.963 86.136 ;
     RECT  38.291 0.24 39.013 66.36 ;
     RECT  38.801 67.584 39.107 69.048 ;
     RECT  39.013 0.144 40.208 66.36 ;
     RECT  39.107 67.584 40.208 67.656 ;
     RECT  39.107 69.024 40.208 69.048 ;
     RECT  38.701 70.32 40.208 70.344 ;
     RECT  38.869 71.472 40.208 73.272 ;
     RECT  38.963 74.736 40.208 78.984 ;
     RECT  38.963 80.016 40.208 86.136 ;
     RECT  40.208 0.144 40.403 86.136 ;
     RECT  40.403 0.144 40.504 85.368 ;
     RECT  40.504 84.384 40.547 85.368 ;
     RECT  40.504 75.504 40.565 78.984 ;
     RECT  40.504 80.256 40.637 81.192 ;
     RECT  40.565 75.504 40.691 76.824 ;
     RECT  40.547 84.624 40.835 85.368 ;
     RECT  40.504 69.024 40.925 69.048 ;
     RECT  40.691 75.504 40.979 76.776 ;
     RECT  40.835 85.344 41.069 85.368 ;
     RECT  40.504 0.144 41.075 66.36 ;
     RECT  40.504 70.32 41.123 70.344 ;
     RECT  40.565 77.856 41.141 78.984 ;
     RECT  40.637 80.256 41.267 80.28 ;
     RECT  41.141 77.904 41.411 78.984 ;
     RECT  40.504 67.584 41.555 67.608 ;
     RECT  41.075 0.144 41.603 65.736 ;
     RECT  40.504 82.464 41.699 83.016 ;
     RECT  40.979 75.504 41.987 76.296 ;
     RECT  41.987 76.224 42.131 76.296 ;
     RECT  41.603 0.144 42.227 65.688 ;
     RECT  42.131 76.224 42.275 76.248 ;
     RECT  42.227 0.144 42.419 64.152 ;
     RECT  42.227 65.232 42.563 65.688 ;
     RECT  41.699 82.992 42.707 83.016 ;
     RECT  40.504 71.472 42.761 73.272 ;
     RECT  42.761 71.472 42.833 73.128 ;
     RECT  41.411 77.904 42.851 78.456 ;
     RECT  42.851 77.904 43.379 77.928 ;
     RECT  42.833 71.472 43.715 73.032 ;
     RECT  43.715 71.472 44.483 71.496 ;
     RECT  42.563 65.28 44.723 65.688 ;
     RECT  44.723 65.664 45.608 65.688 ;
     RECT  43.715 72.48 45.608 73.032 ;
     RECT  45.608 65.664 45.712 84.252 ;
     RECT  45.712 65.664 45.8 83.982 ;
     RECT  45.8 65.598 45.904 83.982 ;
     RECT  45.904 73.008 46.211 73.032 ;
     RECT  45.904 65.664 51.008 65.688 ;
     RECT  51.008 65.664 51.112 84.252 ;
     RECT  51.112 65.664 51.2 83.982 ;
     RECT  51.2 65.598 51.304 83.982 ;
     RECT  51.304 65.664 56.408 65.688 ;
     RECT  56.408 65.664 56.512 84.252 ;
     RECT  56.512 65.664 56.6 83.982 ;
     RECT  56.6 65.598 56.704 83.982 ;
     RECT  42.419 0.144 59.717 63.528 ;
     RECT  59.717 0.192 60.973 63.528 ;
     RECT  56.704 65.664 61.808 65.688 ;
     RECT  61.808 65.664 61.912 84.252 ;
     RECT  61.912 65.664 62 83.982 ;
     RECT  62 65.598 62.104 83.982 ;
     RECT  62.104 65.664 67.208 65.688 ;
     RECT  67.208 65.664 67.312 84.252 ;
     RECT  67.312 65.664 67.4 83.982 ;
     RECT  67.4 65.598 67.504 83.982 ;
     RECT  60.973 0.144 69.509 63.528 ;
     RECT  69.509 0.144 69.581 0.36 ;
     RECT  69.581 0.144 70.933 0.264 ;
     RECT  69.509 1.392 70.933 63.528 ;
     RECT  70.933 0.144 71.273 63.528 ;
     RECT  71.273 0.144 72.137 0.264 ;
     RECT  71.273 1.392 72.209 63.528 ;
     RECT  67.504 65.664 72.608 65.688 ;
     RECT  72.608 65.664 72.712 84.252 ;
     RECT  72.712 65.664 72.8 83.982 ;
     RECT  72.8 65.598 72.904 83.982 ;
     RECT  72.137 0.144 74.261 0.168 ;
     RECT  72.209 1.872 74.693 63.528 ;
     RECT  74.693 2.208 78.008 63.528 ;
     RECT  72.904 65.664 78.008 65.688 ;
     RECT  78.008 2.148 78.112 63.528 ;
     RECT  78.008 65.664 78.112 84.252 ;
     RECT  78.112 65.664 78.2 83.982 ;
     RECT  78.2 65.598 78.304 83.982 ;
     RECT  78.112 2.208 83.408 63.528 ;
     RECT  78.304 65.664 83.408 65.688 ;
     RECT  83.408 2.148 83.512 63.528 ;
     RECT  83.408 65.664 83.512 84.252 ;
     RECT  83.512 65.664 83.6 83.982 ;
     RECT  83.6 65.598 83.704 83.982 ;
     RECT  83.512 2.208 88.808 63.528 ;
     RECT  83.704 65.664 88.808 65.688 ;
     RECT  88.808 2.148 88.912 63.528 ;
     RECT  88.808 65.664 88.912 84.252 ;
     RECT  88.912 65.664 89 83.982 ;
     RECT  89 65.598 89.104 83.982 ;
     RECT  88.912 2.208 94.208 63.528 ;
     RECT  89.104 65.664 94.208 65.688 ;
     RECT  94.208 2.148 94.312 63.528 ;
     RECT  94.208 65.664 94.312 84.252 ;
     RECT  94.312 65.664 94.4 83.982 ;
     RECT  94.4 65.598 94.504 83.982 ;
     RECT  94.312 2.208 99.608 63.528 ;
     RECT  94.504 65.664 99.608 65.688 ;
     RECT  99.608 2.148 99.712 63.528 ;
     RECT  99.608 65.664 99.712 84.252 ;
     RECT  99.712 65.664 99.8 83.982 ;
     RECT  99.8 65.598 99.904 83.982 ;
     RECT  99.712 2.208 100.403 63.528 ;
     RECT  100.403 2.208 100.883 13.944 ;
     RECT  100.403 14.928 101.369 63.528 ;
     RECT  100.883 2.208 101.843 13.896 ;
     RECT  101.843 8.832 101.884 13.896 ;
     RECT  101.884 8.832 102.083 9.096 ;
     RECT  101.884 10.272 102.161 13.896 ;
     RECT  102.083 9.072 102.467 9.096 ;
     RECT  102.161 10.32 102.593 13.896 ;
     RECT  101.369 15.264 102.841 63.528 ;
     RECT  102.841 14.976 102.877 63.528 ;
     RECT  102.593 10.32 102.917 10.776 ;
     RECT  102.593 11.808 103.457 13.848 ;
     RECT  103.457 12.96 103.637 13.848 ;
     RECT  102.877 14.832 103.637 63.528 ;
     RECT  103.637 17.664 103.745 63.528 ;
     RECT  103.457 11.808 103.781 11.928 ;
     RECT  103.637 13.104 103.781 13.848 ;
     RECT  103.781 13.728 103.849 13.848 ;
     RECT  103.637 14.832 103.849 16.68 ;
     RECT  102.917 10.464 103.853 10.776 ;
     RECT  103.745 17.664 103.889 17.928 ;
     RECT  103.849 13.728 103.955 16.68 ;
     RECT  103.955 15.264 103.997 16.68 ;
     RECT  101.843 2.208 105.008 7.752 ;
     RECT  103.853 10.464 105.008 10.728 ;
     RECT  103.781 11.808 105.008 11.832 ;
     RECT  103.955 13.728 105.008 13.848 ;
     RECT  103.997 15.264 105.008 15.768 ;
     RECT  103.889 17.664 105.008 17.688 ;
     RECT  103.745 19.056 105.008 63.528 ;
     RECT  99.904 65.664 105.008 65.688 ;
     RECT  105.008 2.148 105.112 63.528 ;
     RECT  105.008 65.664 105.112 84.252 ;
     RECT  105.112 65.664 105.2 83.982 ;
     RECT  105.112 2.208 105.304 63.528 ;
     RECT  105.2 65.598 105.304 83.982 ;
     RECT  105.304 2.208 110.408 7.752 ;
     RECT  105.304 10.464 110.408 10.728 ;
     RECT  105.304 11.808 110.408 11.832 ;
     RECT  105.304 13.824 110.408 13.848 ;
     RECT  105.304 15.264 110.408 15.768 ;
     RECT  105.304 19.056 110.408 63.528 ;
     RECT  105.304 65.664 110.408 65.688 ;
     RECT  110.408 2.148 110.512 63.528 ;
     RECT  110.408 65.664 110.512 84.252 ;
     RECT  110.512 65.664 110.6 83.982 ;
     RECT  110.512 2.208 110.704 63.528 ;
     RECT  110.6 65.598 110.704 83.982 ;
     RECT  110.704 2.208 114.577 7.752 ;
     RECT  110.704 11.808 114.577 11.832 ;
     RECT  110.704 10.464 114.617 10.728 ;
     RECT  114.577 11.808 114.617 11.976 ;
     RECT  114.577 2.064 115.808 7.752 ;
     RECT  114.617 10.608 115.808 10.728 ;
     RECT  114.617 11.952 115.808 11.976 ;
     RECT  110.704 13.824 115.808 13.848 ;
     RECT  110.704 15.264 115.808 15.768 ;
     RECT  110.704 19.056 115.808 63.528 ;
     RECT  110.704 65.664 115.808 65.688 ;
     RECT  115.808 65.664 115.912 84.252 ;
     RECT  115.912 65.664 116 83.982 ;
     RECT  115.808 2.064 116.104 63.528 ;
     RECT  116 65.598 116.104 83.982 ;
     RECT  116.104 2.064 116.561 7.752 ;
     RECT  116.104 19.056 117.216 63.528 ;
     RECT  117.216 19.056 117.389 62.424 ;
     RECT  116.561 2.064 117.395 2.088 ;
     RECT  116.104 65.664 117.395 65.688 ;
     RECT  117.389 19.056 117.425 62.328 ;
     RECT  117.425 40.992 117.461 46.2 ;
     RECT  117.425 47.232 117.461 58.2 ;
     RECT  116.104 15.264 117.539 15.768 ;
     RECT  117.425 19.056 117.587 39.96 ;
     RECT  116.104 10.608 117.605 10.728 ;
     RECT  117.587 20.352 117.821 39.96 ;
     RECT  117.821 20.352 117.827 27.96 ;
     RECT  117.827 23.424 117.875 27.96 ;
     RECT  117.875 23.52 117.893 27.96 ;
     RECT  117.827 20.352 117.923 22.392 ;
     RECT  117.923 20.352 117.965 22.248 ;
     RECT  117.893 23.712 118.019 27.96 ;
     RECT  116.104 11.952 118.115 11.976 ;
     RECT  117.539 15.744 118.163 15.768 ;
     RECT  116.104 13.824 118.289 13.848 ;
     RECT  117.821 29.088 118.397 39.96 ;
     RECT  117.965 20.352 118.595 22.2 ;
     RECT  117.461 41.472 118.613 46.2 ;
     RECT  117.461 47.328 118.613 58.2 ;
     RECT  118.595 20.352 118.643 21.96 ;
     RECT  117.425 60.48 118.649 62.136 ;
     RECT  118.397 30.768 118.691 39.96 ;
     RECT  117.605 10.608 118.739 10.632 ;
     RECT  118.643 21.936 118.787 21.96 ;
     RECT  116.561 3.648 118.835 7.752 ;
     RECT  118.835 4.224 118.883 7.752 ;
     RECT  118.691 31.104 118.973 39.96 ;
     RECT  118.973 32.928 119.117 39.96 ;
     RECT  118.613 41.472 119.117 44.568 ;
     RECT  118.613 45.6 119.117 46.2 ;
     RECT  118.613 47.424 119.117 58.104 ;
     RECT  117.425 59.232 119.117 59.352 ;
     RECT  119.117 53.76 119.153 58.104 ;
     RECT  118.643 20.352 119.173 20.856 ;
     RECT  118.649 60.768 119.225 62.136 ;
     RECT  119.153 55.2 119.261 58.104 ;
     RECT  118.883 5.184 119.267 7.752 ;
     RECT  119.117 49.248 119.297 52.632 ;
     RECT  119.261 55.2 119.297 56.856 ;
     RECT  119.173 20.304 119.315 20.856 ;
     RECT  119.117 32.928 119.333 39 ;
     RECT  119.315 20.352 119.459 20.856 ;
     RECT  119.333 32.928 119.549 38.04 ;
     RECT  119.117 41.472 119.549 42.168 ;
     RECT  119.297 49.248 119.549 51.768 ;
     RECT  119.153 53.76 119.549 54.072 ;
     RECT  119.261 57.888 119.549 58.104 ;
     RECT  119.549 34.464 119.585 38.04 ;
     RECT  119.117 46.08 119.585 46.104 ;
     RECT  119.549 54.048 119.585 54.072 ;
     RECT  119.297 56.352 119.585 56.856 ;
     RECT  119.117 59.232 119.585 59.256 ;
     RECT  119.585 36.96 119.621 38.04 ;
     RECT  119.549 41.472 119.621 41.496 ;
     RECT  119.549 51.072 119.621 51.72 ;
     RECT  119.549 57.888 119.621 57.912 ;
     RECT  119.585 34.464 119.657 35.736 ;
     RECT  119.621 37.248 119.657 38.04 ;
     RECT  119.297 55.2 119.657 55.224 ;
     RECT  119.585 56.352 119.657 56.376 ;
     RECT  119.225 60.768 119.657 62.04 ;
     RECT  119.657 38.016 119.693 38.04 ;
     RECT  119.549 49.248 119.729 49.944 ;
     RECT  119.549 32.928 119.801 33.144 ;
     RECT  119.657 61.152 119.801 61.176 ;
     RECT  118.973 31.104 119.837 31.512 ;
     RECT  119.117 44.544 119.837 44.568 ;
     RECT  119.459 20.784 119.843 20.856 ;
     RECT  119.657 34.464 119.873 35.448 ;
     RECT  118.019 24 119.909 27.96 ;
     RECT  118.397 29.088 119.981 29.592 ;
     RECT  119.873 34.464 120.053 34.584 ;
     RECT  120.053 34.464 120.089 34.488 ;
     RECT  119.729 49.248 120.233 49.272 ;
     RECT  119.267 5.184 121.208 7.704 ;
     RECT  117.587 19.056 121.208 19.08 ;
     RECT  119.843 20.784 121.208 20.808 ;
     RECT  119.909 24 121.208 27.864 ;
     RECT  119.981 29.376 121.208 29.592 ;
     RECT  119.837 31.104 121.208 31.224 ;
     RECT  119.801 33.12 121.208 33.144 ;
     RECT  119.117 47.904 121.208 47.928 ;
     RECT  119.621 51.696 121.208 51.72 ;
     RECT  121.208 2.148 121.312 84.252 ;
     RECT  121.312 2.418 121.504 83.982 ;
     RECT  121.504 26.352 121.565 26.376 ;
     RECT  121.504 51.696 126.608 51.72 ;
     RECT  126.608 2.148 126.712 84.252 ;
     RECT  126.712 2.418 126.904 83.982 ;
     RECT  126.904 51.696 132.008 51.72 ;
     RECT  132.008 2.148 132.112 84.252 ;
     RECT  132.112 2.418 132.304 83.982 ;
     RECT  132.304 51.696 137.408 51.72 ;
     RECT  137.408 2.148 137.512 84.252 ;
     RECT  137.512 2.418 137.704 83.982 ;
     RECT  137.704 51.696 139.925 51.72 ;
    LAYER M5 ;
     RECT  24.528 0.144 61.272 1.475 ;
     RECT  24.528 1.475 41.16 1.763 ;
     RECT  42.192 1.475 61.272 1.763 ;
     RECT  70.512 0.144 71.112 1.763 ;
     RECT  42.288 1.763 52.2 1.859 ;
     RECT  42.288 1.859 49.32 1.955 ;
     RECT  24.528 1.763 24.984 2.137 ;
     RECT  53.472 1.763 61.272 2.137 ;
     RECT  2.4 2.137 2.52 2.151 ;
     RECT  7.8 2.137 7.92 2.151 ;
     RECT  13.2 2.137 13.32 2.151 ;
     RECT  18.6 2.137 18.72 2.151 ;
     RECT  53.472 2.137 61.92 2.151 ;
     RECT  72.6 2.137 72.72 2.151 ;
     RECT  78 2.137 78.12 2.151 ;
     RECT  83.4 2.137 83.52 2.151 ;
     RECT  88.8 2.137 88.92 2.151 ;
     RECT  94.2 2.137 94.32 2.151 ;
     RECT  99.6 2.137 99.72 2.151 ;
     RECT  105 2.137 105.12 2.151 ;
     RECT  110.4 2.137 110.52 2.151 ;
     RECT  115.8 2.137 115.92 2.151 ;
     RECT  121.2 2.137 121.32 2.151 ;
     RECT  126.6 2.137 126.72 2.151 ;
     RECT  132 2.137 132.12 2.151 ;
     RECT  137.4 2.137 137.52 2.151 ;
     RECT  42.384 1.955 49.32 2.291 ;
     RECT  50.304 1.859 52.2 2.291 ;
     RECT  24 2.137 24.984 2.293 ;
     RECT  23.184 2.293 24.984 2.341 ;
     RECT  18.6 2.151 18.912 2.485 ;
     RECT  25.968 1.763 41.16 2.531 ;
     RECT  53.472 2.151 62.112 2.531 ;
     RECT  16.32 1.621 16.344 2.581 ;
     RECT  7.8 2.151 8.112 2.725 ;
     RECT  14.88 1.045 14.904 2.773 ;
     RECT  22.8 2.341 24.984 2.773 ;
     RECT  25.968 2.531 40.92 2.773 ;
     RECT  53.472 2.531 59.88 2.819 ;
     RECT  16.32 2.581 17.112 2.821 ;
     RECT  42.384 2.291 43.272 2.867 ;
     RECT  22.8 2.773 40.92 2.915 ;
     RECT  53.472 2.819 57.24 2.915 ;
     RECT  66.576 0.144 67.896 2.915 ;
     RECT  70.656 1.763 71.112 2.915 ;
     RECT  44.4 2.291 48.744 2.963 ;
     RECT  50.88 2.291 51.768 2.963 ;
     RECT  71.088 2.915 71.112 2.963 ;
     RECT  14.688 2.773 14.904 2.965 ;
     RECT  16.32 2.821 17.256 2.965 ;
     RECT  14.688 2.965 17.256 3.013 ;
     RECT  20.544 2.725 20.568 3.013 ;
     RECT  21.648 2.533 21.672 3.013 ;
     RECT  22.8 2.915 27.144 3.013 ;
     RECT  13.2 2.151 13.512 3.061 ;
     RECT  14.688 3.013 17.496 3.061 ;
     RECT  13.2 3.061 17.496 3.109 ;
     RECT  18.6 2.485 19.368 3.109 ;
     RECT  65.04 2.965 65.064 3.155 ;
     RECT  20.544 3.013 27.144 3.203 ;
     RECT  42.384 2.867 42.936 3.203 ;
     RECT  44.4 2.963 48.6 3.203 ;
     RECT  72.6 2.151 72.912 3.205 ;
     RECT  28.224 2.915 40.92 3.299 ;
     RECT  61.536 2.531 62.112 3.299 ;
     RECT  72.6 3.205 73.848 3.347 ;
     RECT  58.272 2.819 59.88 3.443 ;
     RECT  63.168 2.821 63.192 3.443 ;
     RECT  13.2 3.109 19.368 3.541 ;
     RECT  20.544 3.203 21.672 3.541 ;
     RECT  42.384 3.203 42.888 3.683 ;
     RECT  32.88 3.299 40.92 3.827 ;
     RECT  118.8 3.637 118.824 3.829 ;
     RECT  32.88 3.827 40.824 3.875 ;
     RECT  61.8 3.299 62.112 3.877 ;
     RECT  44.544 3.203 48.6 4.019 ;
     RECT  58.272 3.443 58.296 4.019 ;
     RECT  66.576 2.915 67.512 4.067 ;
     RECT  61.8 3.877 62.76 4.115 ;
     RECT  11.376 1.093 11.4 4.117 ;
     RECT  22.8 3.203 27.144 4.163 ;
     RECT  118.656 3.829 118.824 4.213 ;
     RECT  61.8 4.115 62.664 4.259 ;
     RECT  34.608 3.875 40.824 4.307 ;
     RECT  42.384 3.683 42.792 4.357 ;
     RECT  11.328 4.117 11.4 4.405 ;
     RECT  25.824 4.163 27.144 4.405 ;
     RECT  28.224 3.299 31.896 4.405 ;
     RECT  25.824 4.405 31.896 4.451 ;
     RECT  59.712 3.443 59.88 4.451 ;
     RECT  13.2 3.541 21.672 4.453 ;
     RECT  22.8 4.163 24.648 4.453 ;
     RECT  42.288 4.357 42.792 4.499 ;
     RECT  44.544 4.019 47.016 4.547 ;
     RECT  26.448 4.451 31.896 4.595 ;
     RECT  32.88 3.875 33.336 4.595 ;
     RECT  44.544 4.547 45.912 4.595 ;
     RECT  32.88 4.595 33.096 4.643 ;
     RECT  42.384 4.499 42.792 4.645 ;
     RECT  13.2 4.453 24.648 4.741 ;
     RECT  51 2.963 51.312 4.741 ;
     RECT  53.472 2.915 57.096 4.885 ;
     RECT  67.056 4.067 67.512 4.931 ;
     RECT  72.6 3.347 72.912 5.077 ;
     RECT  42.384 4.645 42.888 5.123 ;
     RECT  48.144 4.019 48.6 5.123 ;
     RECT  53.472 4.885 57.624 5.123 ;
     RECT  48.576 5.123 48.6 5.171 ;
     RECT  54.72 5.123 57.624 5.171 ;
     RECT  59.712 4.451 59.736 5.219 ;
     RECT  64.416 4.501 64.44 5.267 ;
     RECT  12.912 4.741 24.648 5.269 ;
     RECT  29.184 4.595 30.792 5.411 ;
     RECT  48.624 5.317 48.648 5.459 ;
     RECT  115.8 2.151 116.112 5.461 ;
     RECT  117.36 2.053 117.384 5.461 ;
     RECT  12.912 5.269 25.032 5.509 ;
     RECT  26.448 4.595 27.48 5.509 ;
     RECT  115.8 5.461 117.384 5.509 ;
     RECT  40.08 4.307 40.824 5.557 ;
     RECT  115.8 5.509 117.624 5.557 ;
     RECT  118.656 4.213 118.872 5.557 ;
     RECT  32.88 4.643 32.904 5.605 ;
     RECT  12.912 5.509 27.48 5.699 ;
     RECT  31.008 5.557 31.032 5.699 ;
     RECT  48.96 5.461 48.984 5.699 ;
     RECT  72.6 5.077 73.752 5.701 ;
     RECT  76.032 5.077 76.056 5.701 ;
     RECT  29.184 5.411 30.024 5.747 ;
     RECT  32.88 5.605 33.192 5.747 ;
     RECT  44.688 4.595 45.912 5.747 ;
     RECT  54.912 5.171 54.936 5.747 ;
     RECT  67.2 4.931 67.512 5.749 ;
     RECT  53.568 5.123 53.592 5.795 ;
     RECT  56.4 5.171 57.624 5.795 ;
     RECT  50.736 4.741 51.312 5.845 ;
     RECT  115.8 5.557 118.872 5.845 ;
     RECT  67.2 5.749 68.328 5.891 ;
     RECT  78 2.151 78.312 5.893 ;
     RECT  27.456 5.699 27.48 5.939 ;
     RECT  50.736 5.845 51.816 6.035 ;
     RECT  115.8 5.845 119.352 6.085 ;
     RECT  67.2 5.891 68.232 6.131 ;
     RECT  77.664 5.893 78.312 6.133 ;
     RECT  115.8 6.085 119.88 6.133 ;
     RECT  121.2 2.151 121.512 6.133 ;
     RECT  81.84 5.605 81.864 6.229 ;
     RECT  83.4 2.151 83.712 6.229 ;
     RECT  85.44 4.501 85.464 6.229 ;
     RECT  40.08 5.557 41.064 6.275 ;
     RECT  44.976 5.747 45.912 6.275 ;
     RECT  56.4 5.795 57 6.323 ;
     RECT  75.312 5.701 76.056 6.325 ;
     RECT  77.664 6.133 78.408 6.325 ;
     RECT  92.928 6.181 92.952 6.325 ;
     RECT  94.2 2.151 94.512 6.325 ;
     RECT  88.8 2.151 89.112 6.373 ;
     RECT  85.44 6.229 85.848 6.421 ;
     RECT  87.072 5.605 87.096 6.421 ;
     RECT  91.392 6.229 91.416 6.421 ;
     RECT  85.44 6.421 87.096 6.469 ;
     RECT  72.6 5.701 74.088 6.565 ;
     RECT  90.624 6.421 91.416 6.565 ;
     RECT  92.928 6.325 94.512 6.565 ;
     RECT  79.776 6.133 79.8 6.611 ;
     RECT  71.76 6.565 74.088 6.613 ;
     RECT  75.312 6.325 78.408 6.613 ;
     RECT  69.936 6.373 69.96 6.659 ;
     RECT  10.416 4.405 11.4 6.661 ;
     RECT  61.8 4.259 62.112 6.661 ;
     RECT  88.704 6.373 89.112 6.661 ;
     RECT  29.28 5.747 30.024 6.707 ;
     RECT  29.4 6.707 30.024 6.757 ;
     RECT  33.024 5.747 33.192 6.757 ;
     RECT  71.76 6.613 78.408 6.805 ;
     RECT  88.704 6.661 89.256 6.805 ;
     RECT  95.616 6.373 95.64 6.805 ;
     RECT  65.376 5.845 65.4 6.851 ;
     RECT  71.76 6.805 79.032 6.851 ;
     RECT  12.912 5.699 26.472 6.853 ;
     RECT  81.84 6.229 83.712 6.853 ;
     RECT  90.624 6.565 94.512 6.899 ;
     RECT  29.4 6.757 30.312 6.947 ;
     RECT  88.32 6.805 89.256 6.997 ;
     RECT  99.6 2.151 99.912 7.045 ;
     RECT  67.2 6.131 67.608 7.093 ;
     RECT  10.032 6.661 11.4 7.141 ;
     RECT  60.96 6.661 62.112 7.141 ;
     RECT  99.504 7.045 99.912 7.141 ;
     RECT  34.608 4.307 39.048 7.187 ;
     RECT  32.976 6.757 33.192 7.189 ;
     RECT  93.456 6.899 94.512 7.189 ;
     RECT  95.616 6.805 96.456 7.189 ;
     RECT  99.504 7.141 100.872 7.189 ;
     RECT  32.448 7.189 33.192 7.237 ;
     RECT  90.624 6.899 92.472 7.283 ;
     RECT  98.64 7.189 100.872 7.285 ;
     RECT  93.456 7.189 96.456 7.333 ;
     RECT  60.288 7.141 62.112 7.379 ;
     RECT  47.616 7.285 47.64 7.381 ;
     RECT  56.4 6.323 56.712 7.381 ;
     RECT  64.224 5.653 64.248 7.381 ;
     RECT  67.2 7.093 68.232 7.381 ;
     RECT  69.552 6.805 69.576 7.381 ;
     RECT  85.44 6.469 87.192 7.381 ;
     RECT  88.224 6.997 89.256 7.381 ;
     RECT  98.592 7.285 100.872 7.381 ;
     RECT  63.264 7.381 64.248 7.475 ;
     RECT  80.352 6.805 80.376 7.571 ;
     RECT  34.704 7.187 39.048 7.667 ;
     RECT  45.6 6.275 45.912 7.669 ;
     RECT  56.112 7.381 56.712 7.669 ;
     RECT  27.792 6.565 27.816 7.765 ;
     RECT  98.496 7.381 100.872 7.765 ;
     RECT  60.768 7.379 62.112 7.811 ;
     RECT  12.912 6.853 26.808 7.909 ;
     RECT  27.792 7.765 27.912 7.909 ;
     RECT  51 6.035 51.312 7.909 ;
     RECT  76.896 6.851 76.92 7.909 ;
     RECT  77.904 6.851 79.032 7.909 ;
     RECT  98.496 7.765 100.92 7.909 ;
     RECT  32.016 7.237 33.192 7.957 ;
     RECT  34.8 7.667 39.048 7.957 ;
     RECT  40.08 6.275 40.824 7.957 ;
     RECT  71.76 6.851 75.768 7.957 ;
     RECT  76.896 7.909 79.032 7.957 ;
     RECT  81.84 6.853 83.88 7.957 ;
     RECT  71.76 7.957 79.032 8.051 ;
     RECT  31.344 7.957 33.336 8.243 ;
     RECT  43.824 8.053 43.848 8.243 ;
     RECT  65.232 7.429 65.256 8.293 ;
     RECT  67.2 7.381 69.576 8.293 ;
     RECT  47.568 7.381 47.64 8.341 ;
     RECT  74.064 8.051 79.032 8.341 ;
     RECT  81.744 7.957 83.88 8.387 ;
     RECT  48.816 7.429 48.936 8.435 ;
     RECT  53.76 7.621 53.784 8.435 ;
     RECT  5.472 5.749 5.496 8.437 ;
     RECT  45.6 7.669 46.008 8.437 ;
     RECT  74.064 8.341 79.08 8.483 ;
     RECT  12.912 7.909 27.912 8.485 ;
     RECT  98.016 7.909 100.92 8.485 ;
     RECT  48.912 8.435 48.936 8.531 ;
     RECT  74.064 8.483 79.032 8.531 ;
     RECT  42.384 5.123 42.408 8.579 ;
     RECT  50.88 7.909 51.312 8.579 ;
     RECT  91.056 7.283 92.472 8.579 ;
     RECT  45.504 8.437 46.008 8.675 ;
     RECT  12.672 8.485 27.912 8.723 ;
     RECT  56.112 7.669 56.808 8.723 ;
     RECT  5.472 8.437 5.928 8.821 ;
     RECT  7.8 2.725 9.048 8.821 ;
     RECT  10.032 7.141 11.496 8.821 ;
     RECT  12.672 8.723 26.856 8.821 ;
     RECT  98.016 8.485 101.832 8.821 ;
     RECT  45.6 8.675 46.008 8.917 ;
     RECT  54.768 8.485 54.792 8.965 ;
     RECT  91.056 8.579 91.704 9.059 ;
     RECT  2.4 2.151 2.712 9.061 ;
     RECT  3.744 3.877 3.768 9.061 ;
     RECT  98.016 8.821 102.072 9.061 ;
     RECT  5.472 8.821 9.048 9.109 ;
     RECT  10.032 8.821 26.856 9.109 ;
     RECT  61.8 7.811 62.112 9.109 ;
     RECT  63.264 7.475 63.864 9.109 ;
     RECT  45.6 8.917 46.056 9.155 ;
     RECT  34.8 7.957 40.824 9.157 ;
     RECT  56.16 8.723 56.808 9.205 ;
     RECT  58.368 8.869 58.392 9.205 ;
     RECT  61.8 9.109 63.864 9.251 ;
     RECT  71.76 8.051 72.912 9.253 ;
     RECT  80.592 7.765 80.616 9.253 ;
     RECT  65.232 8.293 69.576 9.301 ;
     RECT  34.8 9.157 40.968 9.347 ;
     RECT  43.248 9.061 43.368 9.347 ;
     RECT  5.472 9.109 26.856 9.395 ;
     RECT  31.344 8.243 33.288 9.443 ;
     RECT  63.504 9.251 63.864 9.445 ;
     RECT  65.232 9.301 69.768 9.445 ;
     RECT  71.088 9.253 72.912 9.539 ;
     RECT  56.16 9.205 58.392 9.541 ;
     RECT  49.296 9.445 49.56 9.587 ;
     RECT  74.448 8.531 79.032 9.635 ;
     RECT  5.472 9.395 6.312 9.637 ;
     RECT  93.456 7.333 96.936 9.637 ;
     RECT  98.016 9.061 102.456 9.637 ;
     RECT  40.2 9.347 40.968 9.781 ;
     RECT  85.44 7.381 89.256 9.781 ;
     RECT  51 8.579 51.312 9.877 ;
     RECT  56.16 9.541 59.256 9.923 ;
     RECT  45.6 9.155 46.008 9.925 ;
     RECT  63.504 9.445 69.768 9.971 ;
     RECT  93.456 9.637 102.456 9.971 ;
     RECT  93.456 9.971 97.272 9.973 ;
     RECT  40.2 9.781 41.736 10.117 ;
     RECT  44.736 9.925 46.008 10.117 ;
     RECT  60.768 7.811 60.792 10.117 ;
     RECT  61.8 9.251 62.328 10.117 ;
     RECT  56.16 9.923 58.392 10.163 ;
     RECT  53.856 8.965 54.792 10.213 ;
     RECT  7.8 9.395 26.856 10.355 ;
     RECT  91.056 9.059 91.464 10.355 ;
     RECT  98.496 9.971 102.456 10.355 ;
     RECT  56.16 10.163 57.72 10.357 ;
     RECT  60.768 10.117 62.328 10.405 ;
     RECT  63.504 9.971 65.928 10.405 ;
     RECT  91.392 10.355 91.464 10.405 ;
     RECT  34.8 9.347 39.096 10.453 ;
     RECT  40.2 10.117 42.12 10.453 ;
     RECT  27.888 8.723 27.912 10.499 ;
     RECT  91.392 10.405 91.56 10.547 ;
     RECT  7.8 10.355 26.808 10.595 ;
     RECT  71.76 9.539 72.912 10.741 ;
     RECT  59.664 10.645 59.688 10.787 ;
     RECT  51 9.877 52.152 10.789 ;
     RECT  92.976 9.973 97.272 10.835 ;
     RECT  7.8 10.595 26.472 10.837 ;
     RECT  55.824 10.357 57.72 10.883 ;
     RECT  80.4 9.253 80.616 10.931 ;
     RECT  31.824 9.443 33.288 10.933 ;
     RECT  74.448 9.635 78.936 10.933 ;
     RECT  80.4 10.931 80.424 10.933 ;
     RECT  49.296 9.587 49.32 11.077 ;
     RECT  53.28 10.213 54.792 11.077 ;
     RECT  55.824 10.883 57.624 11.077 ;
     RECT  70.896 10.741 72.912 11.077 ;
     RECT  74.448 10.933 80.424 11.077 ;
     RECT  98.736 10.355 102.456 11.123 ;
     RECT  50.448 10.789 52.152 11.125 ;
     RECT  53.28 11.077 57.624 11.125 ;
     RECT  92.976 10.835 96.888 11.171 ;
     RECT  44.736 10.117 46.2 11.173 ;
     RECT  47.28 8.341 47.64 11.173 ;
     RECT  48.816 11.077 49.32 11.173 ;
     RECT  67.2 9.971 69.768 11.173 ;
     RECT  85.296 9.781 89.256 11.173 ;
     RECT  47.28 11.173 49.32 11.219 ;
     RECT  70.896 11.077 80.424 11.221 ;
     RECT  85.296 11.173 89.496 11.221 ;
     RECT  50.448 11.125 57.624 11.269 ;
     RECT  44.592 11.173 46.2 11.317 ;
     RECT  91.392 10.547 91.464 11.411 ;
     RECT  67.104 11.173 69.768 11.413 ;
     RECT  50.304 11.269 57.624 11.459 ;
     RECT  60.768 10.405 65.928 11.459 ;
     RECT  70.8 11.221 80.424 11.459 ;
     RECT  92.976 11.171 95.64 11.459 ;
     RECT  44.592 11.317 46.296 11.507 ;
     RECT  67.008 11.413 69.768 11.507 ;
     RECT  70.8 11.459 73.8 11.507 ;
     RECT  79.776 11.459 80.424 11.507 ;
     RECT  82.656 8.387 83.88 11.507 ;
     RECT  2.4 9.061 3.768 11.509 ;
     RECT  4.8 9.637 6.312 11.509 ;
     RECT  91.44 11.411 91.464 11.509 ;
     RECT  44.592 11.507 46.2 11.653 ;
     RECT  34.8 10.453 42.12 11.699 ;
     RECT  67.008 11.507 68.088 11.699 ;
     RECT  98.736 11.123 102.072 11.699 ;
     RECT  69.744 11.507 69.768 11.701 ;
     RECT  70.8 11.507 70.92 11.701 ;
     RECT  44.448 11.653 46.2 11.843 ;
     RECT  53.04 11.459 57.624 11.843 ;
     RECT  50.304 11.459 51.576 11.939 ;
     RECT  47.328 11.219 49.32 11.987 ;
     RECT  85.104 11.221 89.496 11.987 ;
     RECT  53.184 11.843 57.624 12.035 ;
     RECT  75.408 11.459 78.552 12.035 ;
     RECT  83.232 11.507 83.88 12.035 ;
     RECT  85.104 11.987 85.944 12.035 ;
     RECT  98.736 11.699 101.592 12.083 ;
     RECT  31.44 10.933 33.288 12.085 ;
     RECT  47.328 11.987 48.264 12.179 ;
     RECT  101.568 12.083 101.592 12.227 ;
     RECT  61.584 11.459 65.928 12.275 ;
     RECT  98.736 12.083 100.536 12.275 ;
     RECT  7.68 10.837 26.472 12.277 ;
     RECT  47.328 12.179 48.216 12.371 ;
     RECT  40.032 11.699 42.12 12.373 ;
     RECT  34.8 11.699 39.048 12.421 ;
     RECT  96.624 11.171 96.888 12.421 ;
     RECT  7.632 12.277 26.472 12.467 ;
     RECT  44.592 11.843 46.2 12.469 ;
     RECT  69.744 11.701 70.92 12.563 ;
     RECT  72.432 11.507 73.8 12.563 ;
     RECT  87.168 11.987 89.496 12.563 ;
     RECT  31.008 12.085 33.288 12.565 ;
     RECT  34.704 12.421 39.048 12.565 ;
     RECT  87.168 12.563 89.256 12.611 ;
     RECT  96.624 12.421 97.512 12.611 ;
     RECT  31.008 12.565 39.048 12.659 ;
     RECT  65.904 12.275 65.928 12.755 ;
     RECT  91.44 11.509 91.752 12.755 ;
     RECT  96.624 12.611 96.648 12.755 ;
     RECT  2.4 11.509 6.312 12.805 ;
     RECT  7.632 12.467 9.048 12.805 ;
     RECT  75.408 12.035 76.92 12.899 ;
     RECT  92.976 11.459 95.496 12.949 ;
     RECT  69.744 12.563 70.824 12.995 ;
     RECT  67.008 11.699 68.04 13.043 ;
     RECT  80.4 11.507 80.424 13.043 ;
     RECT  53.184 12.035 53.64 13.045 ;
     RECT  85.104 12.035 85.848 13.045 ;
     RECT  44.592 12.469 46.344 13.091 ;
     RECT  10.032 12.467 26.472 13.093 ;
     RECT  34.8 12.659 39.048 13.093 ;
     RECT  40.032 12.373 42.264 13.093 ;
     RECT  61.584 12.275 64.488 13.139 ;
     RECT  87.168 12.611 89.112 13.139 ;
     RECT  29.4 6.947 30.024 13.141 ;
     RECT  72.48 12.563 73.8 13.187 ;
     RECT  92.976 12.949 95.592 13.187 ;
     RECT  49.296 11.987 49.32 13.285 ;
     RECT  78 12.035 78.552 13.285 ;
     RECT  85.008 13.045 85.848 13.285 ;
     RECT  34.8 13.093 42.264 13.331 ;
     RECT  53.04 13.045 53.64 13.331 ;
     RECT  91.728 12.755 91.752 13.331 ;
     RECT  28.896 13.141 30.024 13.429 ;
     RECT  48.96 13.285 49.32 13.475 ;
     RECT  81.696 12.325 81.72 13.475 ;
     RECT  44.592 13.091 46.2 13.573 ;
     RECT  72.6 13.187 73.8 13.573 ;
     RECT  49.296 13.475 49.32 13.619 ;
     RECT  53.184 13.331 53.64 13.619 ;
     RECT  61.584 13.139 64.344 13.619 ;
     RECT  67.2 13.043 68.04 13.621 ;
     RECT  90.48 12.853 90.504 13.667 ;
     RECT  65.952 13.045 65.976 13.715 ;
     RECT  28.656 13.429 30.024 13.859 ;
     RECT  87.84 13.139 89.112 13.861 ;
     RECT  10.032 13.093 26.568 13.909 ;
     RECT  98.736 12.275 100.104 13.909 ;
     RECT  43.344 9.347 43.368 13.957 ;
     RECT  44.448 13.573 46.2 13.957 ;
     RECT  61.584 13.619 64.2 14.003 ;
     RECT  59.472 13.573 59.496 14.005 ;
     RECT  10.032 13.909 27.096 14.051 ;
     RECT  47.328 12.371 47.352 14.053 ;
     RECT  85.008 13.285 86.616 14.195 ;
     RECT  54.624 12.035 57.624 14.197 ;
     RECT  83.232 12.035 83.712 14.197 ;
     RECT  59.472 14.005 60.264 14.293 ;
     RECT  61.584 14.003 63.528 14.293 ;
     RECT  54.624 14.197 58.488 14.339 ;
     RECT  83.232 14.197 83.832 14.389 ;
     RECT  85.008 14.195 85.848 14.389 ;
     RECT  49.344 14.293 49.368 14.483 ;
     RECT  53.184 13.619 53.448 14.485 ;
     RECT  72.6 13.573 74.424 14.485 ;
     RECT  90.576 14.389 90.6 14.579 ;
     RECT  83.232 14.389 85.848 14.627 ;
     RECT  93.216 13.187 95.592 14.627 ;
     RECT  98.736 13.909 100.872 14.627 ;
     RECT  65.856 13.957 65.88 14.629 ;
     RECT  53.136 14.485 53.448 14.675 ;
     RECT  59.472 14.293 63.528 14.675 ;
     RECT  83.232 14.627 83.832 14.723 ;
     RECT  65.568 14.629 65.88 14.773 ;
     RECT  67.2 13.621 68.328 14.773 ;
     RECT  59.472 14.675 62.112 14.819 ;
     RECT  2.4 12.805 9.048 14.821 ;
     RECT  10.032 14.051 26.568 14.821 ;
     RECT  53.232 14.675 53.448 14.821 ;
     RECT  47.328 14.053 47.4 14.917 ;
     RECT  54.624 14.339 57.48 14.963 ;
     RECT  81.984 14.869 82.008 15.013 ;
     RECT  83.232 14.723 83.712 15.013 ;
     RECT  47.328 14.917 47.88 15.059 ;
     RECT  65.568 14.773 68.376 15.157 ;
     RECT  72.48 14.485 74.424 15.205 ;
     RECT  31.008 12.659 33.816 15.251 ;
     RECT  50.4 11.939 51.576 15.251 ;
     RECT  97.728 13.141 97.752 15.251 ;
     RECT  53.232 14.821 53.496 15.299 ;
     RECT  58.464 14.339 58.488 15.301 ;
     RECT  99.024 14.627 100.872 15.301 ;
     RECT  58.464 15.301 59.016 15.347 ;
     RECT  91.152 14.917 91.32 15.347 ;
     RECT  43.344 13.957 46.2 15.349 ;
     RECT  72.24 15.205 74.424 15.349 ;
     RECT  75.408 12.899 76.68 15.349 ;
     RECT  102.48 13.621 102.504 15.349 ;
     RECT  28.752 13.859 30.024 15.397 ;
     RECT  63.264 14.675 63.528 15.445 ;
     RECT  36.816 13.331 42.264 15.491 ;
     RECT  64.944 15.157 68.376 15.491 ;
     RECT  81.984 15.013 83.712 15.491 ;
     RECT  102.384 15.349 102.504 15.493 ;
     RECT  103.92 14.773 103.944 15.493 ;
     RECT  85.008 14.627 85.848 15.539 ;
     RECT  81.312 15.493 81.336 15.635 ;
     RECT  55.488 14.963 57.48 15.683 ;
     RECT  63.264 15.445 63.864 15.731 ;
     RECT  42.192 15.491 42.264 15.829 ;
     RECT  43.344 15.349 46.248 15.829 ;
     RECT  49.968 15.637 49.992 15.829 ;
     RECT  42.192 15.829 46.248 15.875 ;
     RECT  48.864 15.685 48.888 15.875 ;
     RECT  28.656 15.397 30.024 15.877 ;
     RECT  31.008 15.251 33.384 15.877 ;
     RECT  42.816 15.875 46.248 15.971 ;
     RECT  36.816 15.491 41.208 15.973 ;
     RECT  51 15.251 51.576 15.973 ;
     RECT  64.944 15.491 67.992 16.019 ;
     RECT  72.24 15.349 76.68 16.019 ;
     RECT  102.384 15.493 103.944 16.019 ;
     RECT  60.24 14.819 62.112 16.021 ;
     RECT  63.264 15.731 63.384 16.021 ;
     RECT  91.152 15.347 91.176 16.021 ;
     RECT  99.024 15.301 101.352 16.021 ;
     RECT  70.128 12.995 70.824 16.115 ;
     RECT  60.24 16.021 63.384 16.163 ;
     RECT  102.384 16.019 103.368 16.163 ;
     RECT  34.8 13.331 35.784 16.261 ;
     RECT  36.768 15.973 41.208 16.261 ;
     RECT  90.624 16.021 91.176 16.307 ;
     RECT  43.92 15.971 46.248 16.355 ;
     RECT  49.872 15.829 49.992 16.405 ;
     RECT  51 15.973 51.864 16.405 ;
     RECT  72.24 16.019 76.488 16.405 ;
     RECT  55.488 15.683 57.432 16.499 ;
     RECT  71.808 16.405 76.488 16.547 ;
     RECT  82.608 15.491 83.712 16.549 ;
     RECT  85.008 15.539 85.608 16.549 ;
     RECT  34.8 16.261 41.208 16.595 ;
     RECT  64.992 16.019 67.992 16.595 ;
     RECT  47.52 15.059 47.544 16.643 ;
     RECT  28.656 15.877 33.384 16.787 ;
     RECT  60.72 16.163 63.384 16.787 ;
     RECT  72.6 16.547 73.8 16.835 ;
     RECT  96.912 15.349 96.936 16.883 ;
     RECT  58.992 15.347 59.016 16.885 ;
     RECT  80.64 16.501 80.664 16.931 ;
     RECT  27.648 16.789 27.672 16.933 ;
     RECT  28.656 16.787 31.656 16.933 ;
     RECT  87.84 13.861 89.496 17.027 ;
     RECT  2.4 14.821 26.568 17.029 ;
     RECT  27.648 16.933 31.656 17.029 ;
     RECT  64.992 16.595 67.848 17.029 ;
     RECT  2.4 17.029 31.656 17.075 ;
     RECT  34.8 16.595 39.048 17.075 ;
     RECT  53.232 15.299 53.352 17.077 ;
     RECT  55.488 16.499 57.048 17.077 ;
     RECT  98.784 16.021 101.352 17.077 ;
     RECT  32.784 16.787 33.384 17.123 ;
     RECT  45.024 16.355 46.248 17.123 ;
     RECT  53.232 17.077 53.64 17.125 ;
     RECT  58.512 16.885 59.016 17.171 ;
     RECT  102.48 16.163 103.368 17.171 ;
     RECT  45.072 17.123 46.248 17.173 ;
     RECT  49.872 16.405 51.864 17.173 ;
     RECT  47.808 17.029 47.832 17.219 ;
     RECT  49.392 17.173 51.864 17.219 ;
     RECT  53.04 17.125 53.64 17.267 ;
     RECT  68.976 15.685 69 17.267 ;
     RECT  49.392 17.219 49.416 17.269 ;
     RECT  55.344 17.077 57.048 17.315 ;
     RECT  60.72 16.787 62.112 17.315 ;
     RECT  49.104 17.269 49.416 17.365 ;
     RECT  34.8 17.075 35.784 17.461 ;
     RECT  48.192 17.365 49.416 17.507 ;
     RECT  48.768 17.507 49.416 17.603 ;
     RECT  32.928 17.123 33.384 17.605 ;
     RECT  98.784 17.077 101.448 17.605 ;
     RECT  102.48 17.171 103.176 17.605 ;
     RECT  42.816 15.971 42.888 17.653 ;
     RECT  43.92 16.355 44.04 17.653 ;
     RECT  64.368 17.029 67.848 17.653 ;
     RECT  49.008 17.603 49.416 17.699 ;
     RECT  50.496 17.219 51.864 17.699 ;
     RECT  63.36 16.787 63.384 17.749 ;
     RECT  64.368 17.653 67.944 17.749 ;
     RECT  58.944 17.171 59.016 17.795 ;
     RECT  91.152 16.307 91.176 17.795 ;
     RECT  98.784 17.605 103.176 17.795 ;
     RECT  70.8 16.115 70.824 17.797 ;
     RECT  82.608 16.549 85.608 17.891 ;
     RECT  93.744 14.627 95.592 17.893 ;
     RECT  82.608 17.891 85.128 17.939 ;
     RECT  32.928 17.605 33.624 17.987 ;
     RECT  78 13.285 79.224 17.989 ;
     RECT  53.184 17.267 53.64 18.035 ;
     RECT  63.36 17.749 67.944 18.035 ;
     RECT  45.072 17.173 46.296 18.179 ;
     RECT  78 17.989 79.8 18.179 ;
     RECT  99.12 17.795 103.176 18.179 ;
     RECT  2.4 17.075 31.032 18.181 ;
     RECT  40.08 16.595 41.208 18.181 ;
     RECT  55.392 17.315 57.048 18.227 ;
     RECT  68.496 18.037 68.52 18.227 ;
     RECT  75.216 16.547 76.488 18.275 ;
     RECT  40.08 18.181 41.256 18.371 ;
     RECT  53.184 18.035 53.352 18.371 ;
     RECT  34.704 17.461 35.784 18.421 ;
     RECT  36.816 17.075 39.048 18.421 ;
     RECT  99.264 18.179 103.176 18.467 ;
     RECT  2.4 18.181 31.08 18.469 ;
     RECT  93.744 17.893 95.736 18.515 ;
     RECT  40.2 18.371 41.256 18.517 ;
     RECT  42.816 17.653 44.04 18.517 ;
     RECT  34.704 18.421 39.048 18.563 ;
     RECT  99.36 18.467 101.112 18.563 ;
     RECT  51 17.699 51.864 18.565 ;
     RECT  70.56 17.797 70.824 18.565 ;
     RECT  63.36 18.035 67.512 18.611 ;
     RECT  70.32 18.565 70.824 18.611 ;
     RECT  53.184 18.371 53.304 18.613 ;
     RECT  2.064 18.469 31.08 18.659 ;
     RECT  42.816 18.517 44.136 18.659 ;
     RECT  45.6 18.179 46.104 18.659 ;
     RECT  82.608 17.939 84.408 18.707 ;
     RECT  93.744 18.515 95.592 18.707 ;
     RECT  49.392 17.699 49.416 18.709 ;
     RECT  53.136 18.613 53.304 18.709 ;
     RECT  2.064 18.659 26.808 18.755 ;
     RECT  34.704 18.563 35.784 18.755 ;
     RECT  49.152 18.709 49.416 18.755 ;
     RECT  32.976 17.987 33.624 18.757 ;
     RECT  34.704 18.755 35.688 18.757 ;
     RECT  40.2 18.517 41.592 18.757 ;
     RECT  82.608 18.707 84.168 18.803 ;
     RECT  102.24 18.467 103.176 18.803 ;
     RECT  55.488 18.227 57.048 18.851 ;
     RECT  88.32 17.027 89.496 18.851 ;
     RECT  42.816 18.659 43.272 18.995 ;
     RECT  78 18.179 79.32 19.091 ;
     RECT  72.6 16.835 73.464 19.187 ;
     RECT  91.776 19.045 91.8 19.187 ;
     RECT  27.936 18.659 31.08 19.235 ;
     RECT  99.504 18.563 100.68 19.235 ;
     RECT  64.368 18.611 67.512 19.283 ;
     RECT  75.744 18.275 76.056 19.283 ;
     RECT  31.008 19.235 31.08 19.333 ;
     RECT  32.976 18.757 35.688 19.333 ;
     RECT  36.816 18.563 39.048 19.333 ;
     RECT  40.2 18.757 41.64 19.333 ;
     RECT  56.4 18.851 57.048 19.333 ;
     RECT  93.744 18.707 95.208 19.333 ;
     RECT  82.944 18.803 84.168 19.379 ;
     RECT  93.6 19.333 95.208 19.379 ;
     RECT  60.72 17.315 60.744 19.427 ;
     RECT  43.248 18.995 43.272 19.523 ;
     RECT  96.624 18.661 96.648 19.571 ;
     RECT  2.064 18.755 26.472 19.619 ;
     RECT  88.8 18.851 89.496 19.619 ;
     RECT  93.6 19.379 94.632 19.619 ;
     RECT  99.504 19.235 99.912 19.619 ;
     RECT  102.24 18.803 102.264 19.619 ;
     RECT  49.152 18.755 49.176 19.667 ;
     RECT  51 18.565 52.008 19.667 ;
     RECT  70.32 18.611 70.584 19.667 ;
     RECT  78 19.091 79.128 19.667 ;
     RECT  93.6 19.619 94.512 19.667 ;
     RECT  52.992 18.709 53.304 19.763 ;
     RECT  78 19.667 78.696 19.763 ;
     RECT  31.008 19.333 31.896 19.765 ;
     RECT  32.88 19.333 35.688 19.765 ;
     RECT  60.528 19.573 60.552 19.811 ;
     RECT  64.368 19.283 65.784 19.811 ;
     RECT  75.744 19.283 75.768 19.811 ;
     RECT  31.008 19.765 35.688 19.859 ;
     RECT  64.368 19.811 64.392 19.859 ;
     RECT  74.352 19.285 74.376 19.859 ;
     RECT  32.16 19.859 35.688 19.861 ;
     RECT  36.816 19.333 41.64 19.861 ;
     RECT  90.864 19.765 90.888 19.907 ;
     RECT  52.992 19.763 53.016 20.003 ;
     RECT  56.4 19.333 57.144 20.003 ;
     RECT  58.944 17.795 58.968 20.003 ;
     RECT  70.32 19.667 70.344 20.003 ;
     RECT  82.944 19.379 83.712 20.003 ;
     RECT  27.936 19.235 28.008 20.195 ;
     RECT  29.4 19.235 30.024 20.197 ;
     RECT  43.68 20.149 43.704 20.245 ;
     RECT  43.68 20.245 43.896 20.293 ;
     RECT  45.6 18.659 45.912 20.293 ;
     RECT  65.76 19.811 65.784 20.579 ;
     RECT  6.864 19.619 26.472 20.725 ;
     RECT  28.512 20.197 30.024 20.821 ;
     RECT  31.008 19.859 31.032 20.821 ;
     RECT  2.064 19.619 5.688 20.867 ;
     RECT  6.864 20.725 27.288 21.251 ;
     RECT  43.68 20.293 45.912 21.349 ;
     RECT  32.16 19.861 41.64 21.397 ;
     RECT  6.864 21.251 25.032 21.493 ;
     RECT  63.36 18.611 63.384 21.587 ;
     RECT  2.064 20.867 5.496 21.973 ;
     RECT  6.672 21.493 25.032 21.973 ;
     RECT  2.064 21.973 25.032 22.019 ;
     RECT  43.68 21.349 46.2 22.117 ;
     RECT  32.16 21.397 42.216 22.213 ;
     RECT  115.8 6.133 121.512 22.403 ;
     RECT  117.144 22.403 121.512 27.395 ;
     RECT  117.144 27.395 119.832 27.491 ;
     RECT  117.144 27.491 118.872 33.539 ;
     RECT  117.144 33.539 118.776 33.731 ;
     RECT  118.752 33.731 118.776 34.307 ;
     RECT  0.288 36.277 0.312 38.435 ;
     RECT  0.528 38.869 0.552 39.539 ;
     RECT  2.064 22.019 24.936 47.653 ;
     RECT  0.192 50.581 0.216 51.059 ;
     RECT  117.144 33.731 117.24 51.109 ;
     RECT  1.968 47.653 24.936 52.067 ;
     RECT  2.064 52.067 24.936 52.259 ;
     RECT  2.112 52.259 24.936 59.219 ;
     RECT  117.144 51.109 117.384 63.528 ;
     RECT  26.448 21.251 27.288 64.115 ;
     RECT  32.16 22.213 42.264 64.117 ;
     RECT  43.344 22.117 46.2 64.117 ;
     RECT  32.16 64.117 46.2 64.355 ;
     RECT  33.888 64.355 46.2 64.451 ;
     RECT  33.888 64.451 37.032 64.547 ;
     RECT  28.512 20.821 31.032 64.595 ;
     RECT  38.4 64.451 46.2 65.123 ;
     RECT  33.888 64.547 36.456 65.171 ;
     RECT  117.36 63.528 117.384 65.699 ;
     RECT  32.16 64.355 32.904 66.085 ;
     RECT  33.888 65.171 35.112 66.085 ;
     RECT  39.168 65.123 46.2 66.371 ;
     RECT  2.16 59.219 24.936 66.613 ;
     RECT  36.192 65.171 36.456 66.613 ;
     RECT  32.16 66.085 35.112 66.757 ;
     RECT  2.16 66.613 25.56 67.093 ;
     RECT  27.264 64.115 27.288 67.093 ;
     RECT  28.512 64.595 30.408 67.285 ;
     RECT  31.728 66.757 35.112 67.285 ;
     RECT  39.168 66.371 40.512 67.285 ;
     RECT  36.192 66.613 37.128 67.331 ;
     RECT  41.616 66.371 46.2 67.573 ;
     RECT  2.16 67.093 27.288 67.715 ;
     RECT  28.512 67.285 35.208 68.101 ;
     RECT  36.192 67.331 37.032 68.101 ;
     RECT  6.192 67.715 27.288 68.629 ;
     RECT  28.512 68.101 37.032 68.963 ;
     RECT  28.512 68.963 36.504 69.587 ;
     RECT  38.256 67.285 40.512 69.683 ;
     RECT  34.08 69.587 36.504 70.069 ;
     RECT  37.632 69.829 37.656 70.069 ;
     RECT  2.16 67.715 5.16 70.163 ;
     RECT  38.64 69.683 40.512 70.309 ;
     RECT  41.52 67.573 46.2 70.309 ;
     RECT  2.16 70.163 5.064 71.221 ;
     RECT  2.16 71.221 5.112 71.507 ;
     RECT  38.64 70.309 46.2 71.507 ;
     RECT  6.192 68.629 27.432 71.749 ;
     RECT  28.512 69.587 33.096 71.749 ;
     RECT  34.08 70.069 37.656 71.797 ;
     RECT  38.64 71.507 43.944 71.797 ;
     RECT  34.08 71.797 43.944 71.891 ;
     RECT  2.208 71.507 5.112 71.987 ;
     RECT  2.4 71.987 5.112 71.989 ;
     RECT  6.192 71.749 33.096 71.989 ;
     RECT  2.4 71.989 33.096 72.419 ;
     RECT  34.08 71.891 35.208 72.467 ;
     RECT  45.024 71.507 46.2 72.515 ;
     RECT  10.416 72.419 33.096 72.563 ;
     RECT  36.192 71.891 43.944 72.611 ;
     RECT  39.072 72.611 43.944 72.707 ;
     RECT  2.4 72.419 9.384 72.803 ;
     RECT  28.512 72.563 33.096 72.803 ;
     RECT  34.128 72.467 35.208 72.949 ;
     RECT  36.192 72.611 37.656 72.949 ;
     RECT  2.4 72.803 9.144 72.995 ;
     RECT  4.992 72.995 9.144 73.043 ;
     RECT  45.6 72.515 46.2 73.043 ;
     RECT  10.416 72.563 27.432 73.811 ;
     RECT  6.192 73.043 9.144 73.955 ;
     RECT  10.56 73.811 27.432 73.957 ;
     RECT  4.992 73.043 5.112 74.147 ;
     RECT  28.512 72.803 33 74.147 ;
     RECT  10.56 73.957 27.48 74.291 ;
     RECT  32.928 74.147 33 74.723 ;
     RECT  34.128 72.949 37.656 74.915 ;
     RECT  34.224 74.915 37.656 74.963 ;
     RECT  34.56 74.963 37.656 75.203 ;
     RECT  34.56 75.203 35.112 75.491 ;
     RECT  28.512 74.147 31.848 75.733 ;
     RECT  4.992 74.147 5.064 75.925 ;
     RECT  6.192 73.955 9 75.925 ;
     RECT  10.56 74.291 27.432 76.021 ;
     RECT  28.416 75.733 31.848 76.021 ;
     RECT  4.992 75.925 9 76.739 ;
     RECT  10.56 76.021 31.848 76.789 ;
     RECT  10.56 76.789 31.944 76.931 ;
     RECT  32.928 74.723 32.952 76.979 ;
     RECT  34.8 75.491 35.112 77.173 ;
     RECT  6.192 76.739 9 77.269 ;
     RECT  10.56 76.931 31.752 77.269 ;
     RECT  6.192 77.269 31.752 77.411 ;
     RECT  10.56 77.411 31.752 77.893 ;
     RECT  39.072 72.707 43.368 77.939 ;
     RECT  39.072 77.939 42.84 78.131 ;
     RECT  36.192 75.203 37.656 78.421 ;
     RECT  39.072 78.131 39.096 78.421 ;
     RECT  36.192 78.421 39.096 78.707 ;
     RECT  10.56 77.893 32.472 79.141 ;
     RECT  33.888 77.173 35.112 79.141 ;
     RECT  10.56 79.141 35.112 79.717 ;
     RECT  36.192 78.707 36.216 79.717 ;
     RECT  10.56 79.717 36.216 79.813 ;
     RECT  10.56 79.813 36.648 80.003 ;
     RECT  37.632 78.707 39.096 80.005 ;
     RECT  40.2 78.131 42.84 80.005 ;
     RECT  4.992 76.739 5.064 80.099 ;
     RECT  22.608 80.003 36.648 80.533 ;
     RECT  37.632 80.005 42.84 80.533 ;
     RECT  6.192 77.411 9 80.675 ;
     RECT  10.56 80.003 21.384 80.819 ;
     RECT  2.4 72.995 3.864 82.499 ;
     RECT  4.992 80.099 5.016 82.547 ;
     RECT  11.904 80.819 21.384 83.075 ;
     RECT  11.904 83.075 14.232 83.363 ;
     RECT  3.84 82.499 3.864 83.555 ;
     RECT  6.192 80.675 6.408 83.603 ;
     RECT  13.2 83.363 14.232 83.795 ;
     RECT  15.216 83.075 21.384 83.939 ;
     RECT  15.216 83.939 19.608 84.131 ;
     RECT  15.216 84.131 15.912 84.179 ;
     RECT  2.4 82.499 2.712 84.249 ;
     RECT  7.44 80.675 9 84.249 ;
     RECT  13.2 83.795 13.512 84.249 ;
     RECT  45.6 73.043 45.912 84.249 ;
     RECT  51 19.667 51.312 84.249 ;
     RECT  56.4 20.003 56.712 84.249 ;
     RECT  61.8 17.315 62.112 84.249 ;
     RECT  67.2 19.283 67.512 84.249 ;
     RECT  72.6 19.187 72.912 84.249 ;
     RECT  78 19.763 78.312 84.249 ;
     RECT  83.4 20.003 83.712 84.249 ;
     RECT  88.8 19.619 89.112 84.249 ;
     RECT  94.2 19.667 94.512 84.249 ;
     RECT  99.6 19.619 99.912 84.249 ;
     RECT  105 2.151 105.312 84.249 ;
     RECT  110.4 2.151 110.712 84.249 ;
     RECT  115.8 22.403 116.112 84.249 ;
     RECT  121.2 27.395 121.512 84.249 ;
     RECT  126.6 2.151 126.912 84.249 ;
     RECT  132 2.151 132.312 84.249 ;
     RECT  137.4 2.151 137.712 84.249 ;
     RECT  2.4 84.249 2.52 84.263 ;
     RECT  7.44 84.249 7.92 84.263 ;
     RECT  13.2 84.249 13.32 84.263 ;
     RECT  17.28 84.131 19.608 84.263 ;
     RECT  22.608 80.533 42.84 84.263 ;
     RECT  45.6 84.249 45.72 84.263 ;
     RECT  51 84.249 51.12 84.263 ;
     RECT  56.4 84.249 56.52 84.263 ;
     RECT  61.8 84.249 61.92 84.263 ;
     RECT  67.2 84.249 67.32 84.263 ;
     RECT  72.6 84.249 72.72 84.263 ;
     RECT  78 84.249 78.12 84.263 ;
     RECT  83.4 84.249 83.52 84.263 ;
     RECT  88.8 84.249 88.92 84.263 ;
     RECT  94.2 84.249 94.32 84.263 ;
     RECT  99.6 84.249 99.72 84.263 ;
     RECT  105 84.249 105.12 84.263 ;
     RECT  110.4 84.249 110.52 84.263 ;
     RECT  115.8 84.249 115.92 84.263 ;
     RECT  121.2 84.249 121.32 84.263 ;
     RECT  126.6 84.249 126.72 84.263 ;
     RECT  132 84.249 132.12 84.263 ;
     RECT  137.4 84.249 137.52 84.263 ;
     RECT  19.584 84.263 19.608 84.323 ;
     RECT  11.904 83.363 11.928 84.755 ;
     RECT  6.384 83.603 6.408 84.851 ;
     RECT  8.976 84.249 9 84.899 ;
     RECT  22.608 84.263 23.544 84.947 ;
     RECT  22.608 84.947 22.632 85.139 ;
     RECT  7.44 84.263 7.464 85.235 ;
     RECT  10.56 80.819 10.584 85.331 ;
     RECT  15.888 84.179 15.912 85.475 ;
     RECT  20.928 83.939 21.384 86.051 ;
     RECT  21.36 86.051 21.384 86.147 ;
     RECT  17.28 84.263 18.168 86.195 ;
     RECT  24.528 84.263 42.84 86.224 ;
     RECT  17.28 86.195 17.304 86.243 ;
     RECT  41.16 1.475 42.192 1.763 ;
     RECT  14.904 1.621 16.32 2.965 ;
     RECT  24.984 1.763 25.968 2.773 ;
     RECT  41.16 1.763 42.288 1.955 ;
     RECT  52.2 1.763 53.472 2.291 ;
     RECT  49.32 1.859 50.304 2.291 ;
     RECT  41.16 1.955 42.384 2.531 ;
     RECT  71.112 2.137 72.6 2.963 ;
     RECT  115.92 2.137 117.36 2.151 ;
     RECT  13.512 2.151 14.88 2.773 ;
     RECT  116.112 2.151 117.36 5.461 ;
     RECT  43.272 2.291 44.4 2.867 ;
     RECT  40.92 2.531 42.384 3.827 ;
     RECT  21.672 2.533 22.8 3.013 ;
     RECT  17.112 2.581 18.6 2.821 ;
     RECT  19.368 2.725 20.544 3.541 ;
     RECT  20.568 2.725 21.648 3.013 ;
     RECT  13.512 2.773 14.688 3.061 ;
     RECT  57.24 2.819 58.272 2.915 ;
     RECT  17.256 2.821 18.6 3.013 ;
     RECT  62.112 2.821 63.168 3.443 ;
     RECT  42.936 2.867 44.4 3.203 ;
     RECT  27.144 2.915 28.224 4.405 ;
     RECT  57.096 2.915 58.272 4.019 ;
     RECT  65.064 2.965 66.576 3.155 ;
     RECT  17.496 3.013 18.6 3.109 ;
     RECT  21.672 3.203 22.8 4.453 ;
     RECT  31.896 3.299 32.88 4.595 ;
     RECT  58.296 3.443 59.712 4.019 ;
     RECT  62.112 3.443 62.76 3.877 ;
     RECT  117.384 3.637 118.8 3.829 ;
     RECT  42.792 3.683 42.888 4.645 ;
     RECT  40.824 3.827 42.384 4.357 ;
     RECT  117.384 3.829 118.656 5.509 ;
     RECT  33.336 3.875 34.608 4.595 ;
     RECT  2.712 3.877 3.744 9.061 ;
     RECT  47.016 4.019 48.144 4.547 ;
     RECT  57.096 4.019 57.624 4.885 ;
     RECT  24.648 4.163 25.824 4.451 ;
     RECT  39.048 4.307 40.08 7.957 ;
     RECT  40.824 4.357 42.288 4.499 ;
     RECT  9.048 4.405 10.416 6.661 ;
     RECT  24.648 4.451 26.448 5.269 ;
     RECT  40.824 4.499 42.384 5.557 ;
     RECT  30.792 4.595 31.032 5.411 ;
     RECT  33.096 4.595 34.608 4.643 ;
     RECT  32.904 4.643 34.608 5.605 ;
     RECT  11.4 4.741 12.912 7.141 ;
     RECT  53.592 5.123 54.72 5.171 ;
     RECT  53.592 5.171 54.912 5.747 ;
     RECT  54.936 5.171 56.4 5.747 ;
     RECT  64.416 5.267 64.44 5.653 ;
     RECT  25.032 5.269 26.448 5.509 ;
     RECT  30.024 5.411 31.032 5.557 ;
     RECT  117.624 5.509 118.656 5.557 ;
     RECT  30.024 5.557 31.008 5.699 ;
     RECT  41.064 5.557 42.384 6.275 ;
     RECT  33.192 5.605 34.608 7.187 ;
     RECT  64.248 5.653 64.44 5.845 ;
     RECT  26.472 5.699 27.456 5.939 ;
     RECT  30.024 5.699 30.312 6.757 ;
     RECT  74.088 5.701 75.312 6.613 ;
     RECT  29.184 5.747 29.28 6.565 ;
     RECT  32.88 5.747 33.024 6.757 ;
     RECT  64.248 5.845 65.376 6.851 ;
     RECT  68.232 5.891 68.328 6.131 ;
     RECT  26.472 5.939 27.48 6.565 ;
     RECT  119.88 6.085 121.2 6.133 ;
     RECT  67.608 6.131 68.328 6.805 ;
     RECT  78.408 6.133 79.776 6.611 ;
     RECT  92.952 6.181 94.2 6.325 ;
     RECT  85.848 6.229 87.072 6.421 ;
     RECT  91.416 6.229 92.928 6.565 ;
     RECT  56.712 6.323 56.808 7.669 ;
     RECT  94.512 6.373 95.616 7.189 ;
     RECT  89.112 6.421 90.624 6.661 ;
     RECT  87.192 6.469 88.704 6.805 ;
     RECT  26.472 6.565 27.792 6.853 ;
     RECT  27.816 6.565 29.28 6.707 ;
     RECT  78.408 6.611 79.8 6.805 ;
     RECT  9.048 6.661 10.032 9.109 ;
     RECT  89.256 6.661 90.624 7.283 ;
     RECT  27.816 6.707 29.4 7.765 ;
     RECT  32.88 6.757 32.976 7.189 ;
     RECT  67.608 6.805 69.552 7.093 ;
     RECT  79.032 6.805 80.352 7.571 ;
     RECT  80.376 6.805 81.84 7.571 ;
     RECT  87.192 6.805 88.32 6.997 ;
     RECT  64.248 6.851 65.4 7.429 ;
     RECT  75.768 6.851 76.896 7.957 ;
     RECT  76.92 6.851 77.904 7.909 ;
     RECT  26.808 6.853 27.792 7.909 ;
     RECT  92.472 6.899 93.456 8.579 ;
     RECT  30.024 6.947 30.312 7.957 ;
     RECT  87.192 6.997 88.224 7.381 ;
     RECT  68.232 7.093 69.552 7.381 ;
     RECT  11.496 7.141 12.912 8.485 ;
     RECT  33.192 7.187 34.704 7.667 ;
     RECT  62.112 7.381 63.264 9.109 ;
     RECT  47.64 7.429 48.816 8.435 ;
     RECT  64.248 7.429 65.232 7.475 ;
     RECT  65.256 7.429 65.4 8.293 ;
     RECT  63.864 7.475 65.232 9.445 ;
     RECT  79.032 7.571 81.84 7.765 ;
     RECT  33.192 7.667 34.8 7.957 ;
     RECT  27.912 7.765 29.4 10.499 ;
     RECT  79.032 7.765 80.592 8.341 ;
     RECT  80.616 7.765 81.84 7.957 ;
     RECT  60.792 7.811 61.8 10.117 ;
     RECT  96.936 7.909 98.016 9.637 ;
     RECT  30.024 7.957 31.344 9.443 ;
     RECT  33.336 7.957 34.8 8.243 ;
     RECT  80.616 7.957 81.744 8.387 ;
     RECT  72.912 8.051 74.064 8.531 ;
     RECT  42.408 8.053 43.824 8.243 ;
     RECT  33.288 8.243 34.8 12.421 ;
     RECT  42.408 8.243 43.368 8.579 ;
     RECT  46.008 8.341 47.28 8.917 ;
     RECT  79.08 8.341 80.592 8.483 ;
     RECT  47.64 8.435 48.912 8.531 ;
     RECT  79.032 8.483 80.592 9.253 ;
     RECT  11.496 8.485 12.672 8.821 ;
     RECT  54.792 8.485 56.112 8.723 ;
     RECT  42.384 8.579 43.368 9.061 ;
     RECT  50.88 8.579 51 9.445 ;
     RECT  91.704 8.579 93.456 9.059 ;
     RECT  45.504 8.675 45.6 9.925 ;
     RECT  26.856 8.723 27.888 10.355 ;
     RECT  54.792 8.723 56.16 10.357 ;
     RECT  46.056 8.917 47.28 9.155 ;
     RECT  91.464 9.059 93.456 9.973 ;
     RECT  42.384 9.061 43.248 9.157 ;
     RECT  46.008 9.155 47.28 10.117 ;
     RECT  40.968 9.157 43.248 9.347 ;
     RECT  62.328 9.251 63.504 10.405 ;
     RECT  69.576 9.253 71.088 9.301 ;
     RECT  79.032 9.253 80.4 9.635 ;
     RECT  69.768 9.301 71.088 9.539 ;
     RECT  39.096 9.347 40.2 10.453 ;
     RECT  40.968 9.347 43.344 9.781 ;
     RECT  6.312 9.395 7.8 10.837 ;
     RECT  30.024 9.443 31.824 10.933 ;
     RECT  49.56 9.445 51 9.587 ;
     RECT  69.768 9.539 71.76 10.741 ;
     RECT  59.256 9.541 60.768 9.923 ;
     RECT  49.32 9.587 51 10.789 ;
     RECT  78.936 9.635 80.4 10.933 ;
     RECT  3.768 9.637 4.8 11.509 ;
     RECT  41.736 9.781 43.344 10.117 ;
     RECT  83.88 9.781 85.296 11.221 ;
     RECT  58.392 9.923 60.768 10.163 ;
     RECT  43.368 9.925 44.736 11.173 ;
     RECT  65.928 9.971 67.2 11.173 ;
     RECT  97.272 9.971 98.496 10.355 ;
     RECT  91.464 9.973 92.976 10.405 ;
     RECT  42.12 10.117 43.344 12.373 ;
     RECT  46.2 10.117 47.28 11.219 ;
     RECT  59.664 10.163 60.768 10.645 ;
     RECT  52.152 10.213 53.28 11.125 ;
     RECT  26.808 10.355 27.888 10.499 ;
     RECT  97.272 10.355 98.736 10.835 ;
     RECT  54.792 10.357 55.824 11.077 ;
     RECT  91.56 10.405 92.976 10.547 ;
     RECT  91.464 10.547 92.976 11.509 ;
     RECT  59.688 10.645 60.768 10.787 ;
     RECT  69.768 10.741 70.896 11.221 ;
     RECT  49.32 10.789 50.448 11.269 ;
     RECT  6.312 10.837 7.68 12.277 ;
     RECT  80.424 10.931 80.616 12.325 ;
     RECT  30.024 10.933 31.44 12.085 ;
     RECT  47.64 11.077 48.816 11.173 ;
     RECT  95.64 11.171 96.624 11.459 ;
     RECT  43.368 11.173 44.592 11.653 ;
     RECT  65.928 11.173 67.104 11.413 ;
     RECT  46.2 11.219 47.328 11.317 ;
     RECT  69.768 11.221 70.8 11.701 ;
     RECT  83.88 11.221 85.104 12.035 ;
     RECT  49.32 11.269 50.304 11.939 ;
     RECT  46.296 11.317 47.328 11.507 ;
     RECT  91.392 11.411 91.44 12.755 ;
     RECT  65.928 11.413 67.008 12.755 ;
     RECT  51.576 11.459 53.04 11.843 ;
     RECT  78.552 11.459 79.776 11.507 ;
     RECT  95.496 11.459 96.624 12.755 ;
     RECT  46.2 11.507 47.328 12.469 ;
     RECT  70.92 11.507 72.432 12.563 ;
     RECT  82.656 11.507 83.232 12.325 ;
     RECT  91.752 11.509 92.976 13.187 ;
     RECT  43.368 11.653 44.448 11.843 ;
     RECT  39.048 11.699 40.032 13.093 ;
     RECT  43.368 11.843 44.592 13.573 ;
     RECT  51.576 11.843 53.184 13.045 ;
     RECT  49.32 11.939 50.4 13.619 ;
     RECT  48.264 11.987 49.296 12.179 ;
     RECT  85.944 11.987 87.168 12.035 ;
     RECT  53.64 12.035 54.624 13.619 ;
     RECT  76.92 12.035 78 12.899 ;
     RECT  83.712 12.035 85.104 13.045 ;
     RECT  85.848 12.035 87.168 13.139 ;
     RECT  100.536 12.083 101.568 12.227 ;
     RECT  30.024 12.085 31.008 15.877 ;
     RECT  48.216 12.179 49.296 12.371 ;
     RECT  64.488 12.275 65.904 12.755 ;
     RECT  6.312 12.277 7.632 12.805 ;
     RECT  80.424 12.325 81.696 13.043 ;
     RECT  81.72 12.325 83.232 13.475 ;
     RECT  48.96 12.371 49.296 13.285 ;
     RECT  42.264 12.373 43.344 15.829 ;
     RECT  33.288 12.421 34.704 12.565 ;
     RECT  97.512 12.421 98.736 12.611 ;
     RECT  9.048 12.467 10.032 14.821 ;
     RECT  46.344 12.469 47.328 13.091 ;
     RECT  89.256 12.563 89.496 12.611 ;
     RECT  89.112 12.611 89.496 12.853 ;
     RECT  96.648 12.611 98.736 12.755 ;
     RECT  33.816 12.659 34.8 15.251 ;
     RECT  64.488 12.755 67.008 13.043 ;
     RECT  91.392 12.755 91.728 12.853 ;
     RECT  95.496 12.755 95.592 12.949 ;
     RECT  97.728 12.755 98.736 13.141 ;
     RECT  89.112 12.853 90.48 13.667 ;
     RECT  90.504 12.853 91.728 13.331 ;
     RECT  76.68 12.899 78 16.019 ;
     RECT  64.488 13.043 67.2 13.045 ;
     RECT  51.576 13.045 53.04 13.331 ;
     RECT  64.488 13.045 65.952 13.139 ;
     RECT  65.976 13.045 67.2 13.715 ;
     RECT  83.712 13.045 85.008 14.197 ;
     RECT  46.2 13.091 47.328 15.059 ;
     RECT  64.344 13.139 65.952 13.619 ;
     RECT  85.848 13.139 87.84 13.285 ;
     RECT  97.752 13.141 98.736 14.627 ;
     RECT  72.48 13.187 72.6 14.485 ;
     RECT  91.752 13.187 93.216 13.331 ;
     RECT  86.616 13.285 87.84 14.195 ;
     RECT  35.784 13.331 36.816 15.973 ;
     RECT  53.136 13.331 53.184 14.485 ;
     RECT  90.504 13.331 90.6 13.667 ;
     RECT  48.96 13.475 49.296 13.619 ;
     RECT  81.984 13.475 83.232 14.869 ;
     RECT  43.368 13.573 44.448 13.957 ;
     RECT  74.424 13.573 75.408 15.349 ;
     RECT  48.96 13.619 50.4 14.293 ;
     RECT  53.448 13.619 54.624 14.821 ;
     RECT  64.2 13.619 65.952 13.715 ;
     RECT  89.112 13.667 90.6 13.861 ;
     RECT  64.2 13.715 67.2 13.957 ;
     RECT  89.496 13.861 90.6 14.389 ;
     RECT  64.2 13.957 65.856 14.003 ;
     RECT  65.88 13.957 67.2 14.773 ;
     RECT  63.528 14.003 65.856 14.629 ;
     RECT  60.264 14.005 61.584 14.293 ;
     RECT  58.488 14.197 59.472 14.819 ;
     RECT  83.832 14.197 85.008 14.389 ;
     RECT  48.96 14.293 49.344 14.483 ;
     RECT  49.368 14.293 50.4 14.483 ;
     RECT  57.48 14.339 58.464 15.347 ;
     RECT  89.496 14.389 90.576 14.579 ;
     RECT  48.96 14.483 50.4 14.917 ;
     RECT  89.496 14.579 90.6 14.917 ;
     RECT  83.832 14.627 85.008 14.723 ;
     RECT  97.752 14.627 99.024 15.251 ;
     RECT  63.528 14.629 65.568 15.157 ;
     RECT  53.136 14.675 53.232 15.973 ;
     RECT  62.112 14.675 63.264 16.021 ;
     RECT  83.712 14.723 85.008 16.549 ;
     RECT  102.504 14.773 103.92 15.493 ;
     RECT  103.944 14.773 105 16.019 ;
     RECT  58.488 14.819 60.24 15.301 ;
     RECT  53.496 14.821 54.624 14.963 ;
     RECT  82.008 14.869 83.232 15.013 ;
     RECT  47.88 14.917 50.4 15.059 ;
     RECT  89.496 14.917 91.152 16.021 ;
     RECT  46.2 15.059 47.52 15.349 ;
     RECT  47.544 15.059 50.4 15.251 ;
     RECT  63.528 15.157 64.944 15.445 ;
     RECT  70.824 15.205 72.24 16.405 ;
     RECT  33.384 15.251 34.8 17.461 ;
     RECT  47.544 15.251 51 15.637 ;
     RECT  98.784 15.251 99.024 16.021 ;
     RECT  59.016 15.301 60.24 16.163 ;
     RECT  101.352 15.301 102.48 15.349 ;
     RECT  57.48 15.347 58.992 15.683 ;
     RECT  46.248 15.349 47.52 16.643 ;
     RECT  95.592 15.349 96.912 16.883 ;
     RECT  101.352 15.349 102.384 16.163 ;
     RECT  63.864 15.445 64.944 15.731 ;
     RECT  41.208 15.491 42.192 15.875 ;
     RECT  67.992 15.491 68.376 15.685 ;
     RECT  81.984 15.491 82.608 15.493 ;
     RECT  81.336 15.493 82.608 15.635 ;
     RECT  47.544 15.637 49.968 15.685 ;
     RECT  49.992 15.637 51 16.405 ;
     RECT  57.432 15.683 58.992 16.499 ;
     RECT  47.544 15.685 48.864 15.875 ;
     RECT  48.888 15.685 49.968 15.829 ;
     RECT  67.992 15.685 68.976 16.595 ;
     RECT  69 15.685 70.128 16.115 ;
     RECT  63.384 15.731 64.944 16.019 ;
     RECT  48.888 15.829 49.872 15.875 ;
     RECT  47.544 15.875 49.872 16.643 ;
     RECT  42.888 15.971 43.92 17.653 ;
     RECT  35.784 15.973 36.768 16.261 ;
     RECT  51.864 15.973 53.232 17.125 ;
     RECT  63.384 16.019 64.992 17.029 ;
     RECT  76.488 16.019 78 18.275 ;
     RECT  89.496 16.021 90.624 16.307 ;
     RECT  101.352 16.163 102.48 17.077 ;
     RECT  44.04 16.355 45.024 17.123 ;
     RECT  70.824 16.405 71.808 16.547 ;
     RECT  57.048 16.499 58.992 16.885 ;
     RECT  79.224 16.501 80.64 16.931 ;
     RECT  73.8 16.547 75.216 16.835 ;
     RECT  39.048 16.595 40.08 18.371 ;
     RECT  67.848 16.595 68.976 17.267 ;
     RECT  46.248 16.643 49.872 17.029 ;
     RECT  31.656 16.787 32.784 17.075 ;
     RECT  62.112 16.787 63.36 21.587 ;
     RECT  26.568 16.789 27.648 17.029 ;
     RECT  27.672 16.789 28.656 16.933 ;
     RECT  95.592 16.883 95.736 17.893 ;
     RECT  57.048 16.885 58.512 17.171 ;
     RECT  79.224 16.931 79.8 17.989 ;
     RECT  46.248 17.029 47.808 17.173 ;
     RECT  47.832 17.029 49.872 17.173 ;
     RECT  63.384 17.029 64.368 17.749 ;
     RECT  31.032 17.075 31.08 18.181 ;
     RECT  35.784 17.075 36.816 18.421 ;
     RECT  101.448 17.077 102.48 17.605 ;
     RECT  44.04 17.123 45.072 18.179 ;
     RECT  51.864 17.125 53.04 17.267 ;
     RECT  46.296 17.173 47.808 17.219 ;
     RECT  47.832 17.173 49.392 17.219 ;
     RECT  48.192 17.219 49.392 17.269 ;
     RECT  49.416 17.219 50.496 17.699 ;
     RECT  51.864 17.267 53.184 18.565 ;
     RECT  67.848 17.267 68.52 17.653 ;
     RECT  48.192 17.269 49.104 17.365 ;
     RECT  60.744 17.315 61.8 19.427 ;
     RECT  33.384 17.461 34.704 17.605 ;
     RECT  33.624 17.605 34.704 18.757 ;
     RECT  67.944 17.653 68.52 18.035 ;
     RECT  49.152 17.699 49.392 18.709 ;
     RECT  32.928 17.987 32.976 19.333 ;
     RECT  67.512 18.035 68.52 18.037 ;
     RECT  67.512 18.037 68.496 18.227 ;
     RECT  44.04 18.179 45.6 18.517 ;
     RECT  75.216 18.275 75.744 19.285 ;
     RECT  39.048 18.371 40.2 19.333 ;
     RECT  101.112 18.467 102.24 18.563 ;
     RECT  95.592 18.515 95.736 18.661 ;
     RECT  41.592 18.517 42.816 18.757 ;
     RECT  44.136 18.517 45.6 18.659 ;
     RECT  35.784 18.563 36.816 18.755 ;
     RECT  52.008 18.565 53.184 18.613 ;
     RECT  63.384 18.611 64.368 19.859 ;
     RECT  52.008 18.613 53.136 18.709 ;
     RECT  26.808 18.659 27.936 18.755 ;
     RECT  43.272 18.659 43.704 19.523 ;
     RECT  95.592 18.661 96.624 18.707 ;
     RECT  95.208 18.707 96.624 19.379 ;
     RECT  52.008 18.709 52.992 19.667 ;
     RECT  26.472 18.755 27.936 20.195 ;
     RECT  35.688 18.755 36.816 19.861 ;
     RECT  41.64 18.757 42.816 18.995 ;
     RECT  72.912 19.187 73.464 19.285 ;
     RECT  28.008 19.235 29.4 20.195 ;
     RECT  30.024 19.235 31.008 20.821 ;
     RECT  65.784 19.283 67.2 20.579 ;
     RECT  72.912 19.285 74.352 19.859 ;
     RECT  74.376 19.285 75.744 19.811 ;
     RECT  31.896 19.333 32.88 19.765 ;
     RECT  60.72 19.427 61.8 19.573 ;
     RECT  43.68 19.523 43.704 20.149 ;
     RECT  60.552 19.573 61.8 19.811 ;
     RECT  5.688 19.619 6.864 20.867 ;
     RECT  64.392 19.811 65.76 19.859 ;
     RECT  31.032 19.859 32.16 64.595 ;
     RECT  26.472 20.195 29.4 20.197 ;
     RECT  26.472 20.197 28.512 20.725 ;
     RECT  27.288 20.725 28.512 68.629 ;
     RECT  5.496 20.867 6.864 21.493 ;
     RECT  25.032 21.251 26.448 22.019 ;
     RECT  42.216 21.397 43.68 22.117 ;
     RECT  5.496 21.493 6.672 21.973 ;
     RECT  24.936 22.019 26.448 64.115 ;
     RECT  42.216 22.117 43.344 22.213 ;
     RECT  42.264 22.213 43.344 64.117 ;
     RECT  116.112 22.403 117.144 63.528 ;
     RECT  119.832 27.395 121.2 27.491 ;
     RECT  117.24 33.731 118.752 34.307 ;
     RECT  0.552 38.869 2.064 39.539 ;
     RECT  116.112 63.528 117.36 65.699 ;
     RECT  32.904 64.355 33.888 66.085 ;
     RECT  37.032 64.451 38.4 64.547 ;
     RECT  35.112 65.171 36.192 67.285 ;
     RECT  40.512 66.371 41.616 67.573 ;
     RECT  30.408 66.757 31.728 67.285 ;
     RECT  35.208 67.285 36.192 68.101 ;
     RECT  37.128 67.285 38.256 67.331 ;
     RECT  37.032 67.331 38.256 68.963 ;
     RECT  40.512 67.573 41.52 70.309 ;
     RECT  5.16 67.715 6.192 70.163 ;
     RECT  27.432 68.629 28.512 71.749 ;
     RECT  36.504 68.963 38.256 69.683 ;
     RECT  33.096 69.587 34.08 72.467 ;
     RECT  36.504 69.683 38.64 69.829 ;
     RECT  36.504 69.829 37.632 70.069 ;
     RECT  37.656 69.829 38.64 71.797 ;
     RECT  5.064 70.163 6.192 71.221 ;
     RECT  5.112 71.221 6.192 71.989 ;
     RECT  43.944 71.507 45.024 72.515 ;
     RECT  35.208 71.891 36.192 72.949 ;
     RECT  9.384 72.419 10.416 72.803 ;
     RECT  33.096 72.467 34.128 72.803 ;
     RECT  27.432 72.563 28.512 73.957 ;
     RECT  37.656 72.611 39.072 78.421 ;
     RECT  9.144 72.803 10.416 73.811 ;
     RECT  33 72.803 34.128 74.723 ;
     RECT  3.864 72.995 4.992 82.547 ;
     RECT  5.112 73.043 6.192 74.147 ;
     RECT  9.144 73.811 10.56 73.955 ;
     RECT  27.48 73.957 28.512 74.291 ;
     RECT  5.064 74.147 6.192 75.925 ;
     RECT  31.848 74.147 32.928 76.789 ;
     RECT  27.432 74.291 28.512 75.733 ;
     RECT  32.952 74.723 34.128 74.915 ;
     RECT  32.952 74.915 34.224 74.963 ;
     RECT  35.112 75.203 36.192 79.717 ;
     RECT  27.432 75.733 28.416 76.021 ;
     RECT  5.064 76.739 6.192 80.099 ;
     RECT  31.944 76.789 32.928 76.931 ;
     RECT  31.752 76.931 32.928 76.979 ;
     RECT  31.752 76.979 32.952 77.173 ;
     RECT  31.752 77.173 33.888 77.893 ;
     RECT  32.472 77.893 33.888 79.141 ;
     RECT  39.096 78.131 40.2 80.005 ;
     RECT  36.216 78.707 37.632 79.813 ;
     RECT  36.648 79.813 37.632 80.533 ;
     RECT  21.384 80.003 22.608 85.139 ;
     RECT  5.016 80.099 6.192 82.547 ;
     RECT  6.408 80.675 7.44 84.851 ;
     RECT  10.584 80.819 11.904 84.755 ;
     RECT  2.712 82.499 3.84 83.555 ;
     RECT  14.232 83.075 15.216 83.795 ;
     RECT  11.928 83.363 13.2 84.263 ;
     RECT  19.608 83.939 20.928 84.323 ;
     RECT  15.912 84.131 17.28 85.475 ;
     RECT  7.92 84.249 8.976 84.263 ;
     RECT  7.464 84.263 8.976 84.899 ;
     RECT  18.168 84.263 19.584 84.323 ;
     RECT  23.544 84.263 24.528 84.947 ;
  END
END ot_s81_pq_qb_bank2_native
END LIBRARY
